VERSION 5.8 ;
BUSBITCHARS "[]" ;
DIVIDERCHAR "/" ;
UNITS
    DATABASE MICRONS 1000 ;
END UNITS

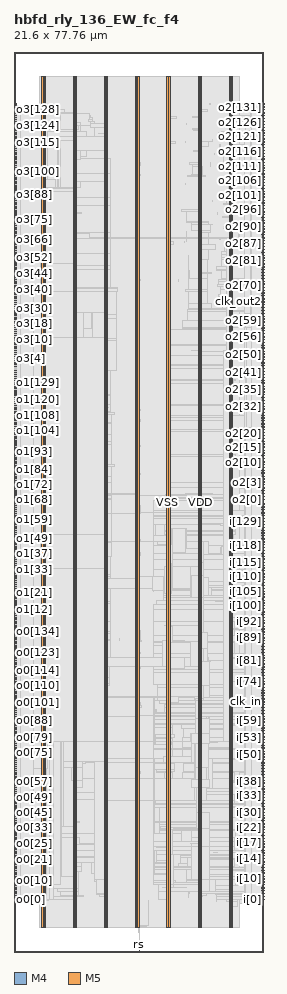
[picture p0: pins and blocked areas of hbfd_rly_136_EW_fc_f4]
MACRO hbfd_rly_136_EW_fc_f4
  FOREIGN hbfd_rly_136_EW_fc_f4 0 0 ;
  CLASS BLOCK ;
  SIZE 21.6 BY 77.76 ;
  PIN clk_in
    DIRECTION INPUT ;
    USE SIGNAL ;
    PORT
      LAYER M4 ;
        RECT  21.408 21.6 21.6 21.624 ;
    END
  END clk_in
  PIN clk_out0
    DIRECTION OUTPUT ;
    USE SIGNAL ;
    PORT
      LAYER M4 ;
        RECT  0 15.84 0.192 15.864 ;
    END
  END clk_out0
  PIN clk_out1
    DIRECTION OUTPUT ;
    USE SIGNAL ;
    PORT
      LAYER M4 ;
        RECT  0 38.88 0.192 38.904 ;
    END
  END clk_out1
  PIN clk_out2
    DIRECTION OUTPUT ;
    USE SIGNAL ;
    PORT
      LAYER M4 ;
        RECT  21.408 56.16 21.6 56.184 ;
    END
  END clk_out2
  PIN clk_out3
    DIRECTION OUTPUT ;
    USE SIGNAL ;
    PORT
      LAYER M4 ;
        RECT  0 61.92 0.192 61.944 ;
    END
  END clk_out3
  PIN i[0]
    DIRECTION INPUT ;
    USE SIGNAL ;
    PORT
      LAYER M4 ;
        RECT  21.408 4.512 21.6 4.536 ;
    END
  END i[0]
  PIN i[100]
    DIRECTION INPUT ;
    USE SIGNAL ;
    PORT
      LAYER M4 ;
        RECT  21.408 29.904 21.6 29.928 ;
    END
  END i[100]
  PIN i[101]
    DIRECTION INPUT ;
    USE SIGNAL ;
    PORT
      LAYER M4 ;
        RECT  21.408 30.144 21.6 30.168 ;
    END
  END i[101]
  PIN i[102]
    DIRECTION INPUT ;
    USE SIGNAL ;
    PORT
      LAYER M4 ;
        RECT  21.408 30.384 21.6 30.408 ;
    END
  END i[102]
  PIN i[103]
    DIRECTION INPUT ;
    USE SIGNAL ;
    PORT
      LAYER M4 ;
        RECT  21.408 30.672 21.6 30.696 ;
    END
  END i[103]
  PIN i[104]
    DIRECTION INPUT ;
    USE SIGNAL ;
    PORT
      LAYER M4 ;
        RECT  21.408 30.912 21.6 30.936 ;
    END
  END i[104]
  PIN i[105]
    DIRECTION INPUT ;
    USE SIGNAL ;
    PORT
      LAYER M4 ;
        RECT  21.408 31.152 21.6 31.176 ;
    END
  END i[105]
  PIN i[106]
    DIRECTION INPUT ;
    USE SIGNAL ;
    PORT
      LAYER M4 ;
        RECT  21.408 31.392 21.6 31.416 ;
    END
  END i[106]
  PIN i[107]
    DIRECTION INPUT ;
    USE SIGNAL ;
    PORT
      LAYER M4 ;
        RECT  21.408 31.68 21.6 31.704 ;
    END
  END i[107]
  PIN i[108]
    DIRECTION INPUT ;
    USE SIGNAL ;
    PORT
      LAYER M4 ;
        RECT  21.408 31.92 21.6 31.944 ;
    END
  END i[108]
  PIN i[109]
    DIRECTION INPUT ;
    USE SIGNAL ;
    PORT
      LAYER M4 ;
        RECT  21.408 32.16 21.6 32.184 ;
    END
  END i[109]
  PIN i[10]
    DIRECTION INPUT ;
    USE SIGNAL ;
    PORT
      LAYER M4 ;
        RECT  21.408 7.056 21.6 7.08 ;
    END
  END i[10]
  PIN i[110]
    DIRECTION INPUT ;
    USE SIGNAL ;
    PORT
      LAYER M4 ;
        RECT  21.408 32.4 21.6 32.424 ;
    END
  END i[110]
  PIN i[111]
    DIRECTION INPUT ;
    USE SIGNAL ;
    PORT
      LAYER M4 ;
        RECT  21.408 32.64 21.6 32.664 ;
    END
  END i[111]
  PIN i[112]
    DIRECTION INPUT ;
    USE SIGNAL ;
    PORT
      LAYER M4 ;
        RECT  21.408 32.928 21.6 32.952 ;
    END
  END i[112]
  PIN i[113]
    DIRECTION INPUT ;
    USE SIGNAL ;
    PORT
      LAYER M4 ;
        RECT  21.408 33.168 21.6 33.192 ;
    END
  END i[113]
  PIN i[114]
    DIRECTION INPUT ;
    USE SIGNAL ;
    PORT
      LAYER M4 ;
        RECT  21.408 33.408 21.6 33.432 ;
    END
  END i[114]
  PIN i[115]
    DIRECTION INPUT ;
    USE SIGNAL ;
    PORT
      LAYER M4 ;
        RECT  21.408 33.648 21.6 33.672 ;
    END
  END i[115]
  PIN i[116]
    DIRECTION INPUT ;
    USE SIGNAL ;
    PORT
      LAYER M4 ;
        RECT  21.408 33.936 21.6 33.96 ;
    END
  END i[116]
  PIN i[117]
    DIRECTION INPUT ;
    USE SIGNAL ;
    PORT
      LAYER M4 ;
        RECT  21.408 34.176 21.6 34.2 ;
    END
  END i[117]
  PIN i[118]
    DIRECTION INPUT ;
    USE SIGNAL ;
    PORT
      LAYER M4 ;
        RECT  21.408 34.416 21.6 34.44 ;
    END
  END i[118]
  PIN i[119]
    DIRECTION INPUT ;
    USE SIGNAL ;
    PORT
      LAYER M4 ;
        RECT  21.408 34.656 21.6 34.68 ;
    END
  END i[119]
  PIN i[11]
    DIRECTION INPUT ;
    USE SIGNAL ;
    PORT
      LAYER M4 ;
        RECT  21.408 7.296 21.6 7.32 ;
    END
  END i[11]
  PIN i[120]
    DIRECTION INPUT ;
    USE SIGNAL ;
    PORT
      LAYER M4 ;
        RECT  21.408 34.944 21.6 34.968 ;
    END
  END i[120]
  PIN i[121]
    DIRECTION INPUT ;
    USE SIGNAL ;
    PORT
      LAYER M4 ;
        RECT  21.408 35.184 21.6 35.208 ;
    END
  END i[121]
  PIN i[122]
    DIRECTION INPUT ;
    USE SIGNAL ;
    PORT
      LAYER M4 ;
        RECT  21.408 35.424 21.6 35.448 ;
    END
  END i[122]
  PIN i[123]
    DIRECTION INPUT ;
    USE SIGNAL ;
    PORT
      LAYER M4 ;
        RECT  21.408 35.664 21.6 35.688 ;
    END
  END i[123]
  PIN i[124]
    DIRECTION INPUT ;
    USE SIGNAL ;
    PORT
      LAYER M4 ;
        RECT  21.408 35.952 21.6 35.976 ;
    END
  END i[124]
  PIN i[125]
    DIRECTION INPUT ;
    USE SIGNAL ;
    PORT
      LAYER M4 ;
        RECT  21.408 36.192 21.6 36.216 ;
    END
  END i[125]
  PIN i[126]
    DIRECTION INPUT ;
    USE SIGNAL ;
    PORT
      LAYER M4 ;
        RECT  21.408 36.432 21.6 36.456 ;
    END
  END i[126]
  PIN i[127]
    DIRECTION INPUT ;
    USE SIGNAL ;
    PORT
      LAYER M4 ;
        RECT  21.408 36.672 21.6 36.696 ;
    END
  END i[127]
  PIN i[128]
    DIRECTION INPUT ;
    USE SIGNAL ;
    PORT
      LAYER M4 ;
        RECT  21.408 36.912 21.6 36.936 ;
    END
  END i[128]
  PIN i[129]
    DIRECTION INPUT ;
    USE SIGNAL ;
    PORT
      LAYER M4 ;
        RECT  21.408 37.2 21.6 37.224 ;
    END
  END i[129]
  PIN i[12]
    DIRECTION INPUT ;
    USE SIGNAL ;
    PORT
      LAYER M4 ;
        RECT  21.408 7.536 21.6 7.56 ;
    END
  END i[12]
  PIN i[130]
    DIRECTION INPUT ;
    USE SIGNAL ;
    PORT
      LAYER M4 ;
        RECT  21.408 37.44 21.6 37.464 ;
    END
  END i[130]
  PIN i[131]
    DIRECTION INPUT ;
    USE SIGNAL ;
    PORT
      LAYER M4 ;
        RECT  21.408 37.68 21.6 37.704 ;
    END
  END i[131]
  PIN i[132]
    DIRECTION INPUT ;
    USE SIGNAL ;
    PORT
      LAYER M4 ;
        RECT  21.408 37.92 21.6 37.944 ;
    END
  END i[132]
  PIN i[133]
    DIRECTION INPUT ;
    USE SIGNAL ;
    PORT
      LAYER M4 ;
        RECT  21.408 38.208 21.6 38.232 ;
    END
  END i[133]
  PIN i[134]
    DIRECTION INPUT ;
    USE SIGNAL ;
    PORT
      LAYER M4 ;
        RECT  21.408 38.448 21.6 38.472 ;
    END
  END i[134]
  PIN i[135]
    DIRECTION INPUT ;
    USE SIGNAL ;
    PORT
      LAYER M4 ;
        RECT  21.408 38.688 21.6 38.712 ;
    END
  END i[135]
  PIN i[13]
    DIRECTION INPUT ;
    USE SIGNAL ;
    PORT
      LAYER M4 ;
        RECT  21.408 7.776 21.6 7.8 ;
    END
  END i[13]
  PIN i[14]
    DIRECTION INPUT ;
    USE SIGNAL ;
    PORT
      LAYER M4 ;
        RECT  21.408 8.064 21.6 8.088 ;
    END
  END i[14]
  PIN i[15]
    DIRECTION INPUT ;
    USE SIGNAL ;
    PORT
      LAYER M4 ;
        RECT  21.408 8.304 21.6 8.328 ;
    END
  END i[15]
  PIN i[16]
    DIRECTION INPUT ;
    USE SIGNAL ;
    PORT
      LAYER M4 ;
        RECT  21.408 8.544 21.6 8.568 ;
    END
  END i[16]
  PIN i[17]
    DIRECTION INPUT ;
    USE SIGNAL ;
    PORT
      LAYER M4 ;
        RECT  21.408 8.784 21.6 8.808 ;
    END
  END i[17]
  PIN i[18]
    DIRECTION INPUT ;
    USE SIGNAL ;
    PORT
      LAYER M4 ;
        RECT  21.408 9.072 21.6 9.096 ;
    END
  END i[18]
  PIN i[19]
    DIRECTION INPUT ;
    USE SIGNAL ;
    PORT
      LAYER M4 ;
        RECT  21.408 9.312 21.6 9.336 ;
    END
  END i[19]
  PIN i[1]
    DIRECTION INPUT ;
    USE SIGNAL ;
    PORT
      LAYER M4 ;
        RECT  21.408 4.8 21.6 4.824 ;
    END
  END i[1]
  PIN i[20]
    DIRECTION INPUT ;
    USE SIGNAL ;
    PORT
      LAYER M4 ;
        RECT  21.408 9.552 21.6 9.576 ;
    END
  END i[20]
  PIN i[21]
    DIRECTION INPUT ;
    USE SIGNAL ;
    PORT
      LAYER M4 ;
        RECT  21.408 9.792 21.6 9.816 ;
    END
  END i[21]
  PIN i[22]
    DIRECTION INPUT ;
    USE SIGNAL ;
    PORT
      LAYER M4 ;
        RECT  21.408 10.08 21.6 10.104 ;
    END
  END i[22]
  PIN i[23]
    DIRECTION INPUT ;
    USE SIGNAL ;
    PORT
      LAYER M4 ;
        RECT  21.408 10.32 21.6 10.344 ;
    END
  END i[23]
  PIN i[24]
    DIRECTION INPUT ;
    USE SIGNAL ;
    PORT
      LAYER M4 ;
        RECT  21.408 10.56 21.6 10.584 ;
    END
  END i[24]
  PIN i[25]
    DIRECTION INPUT ;
    USE SIGNAL ;
    PORT
      LAYER M4 ;
        RECT  21.408 10.8 21.6 10.824 ;
    END
  END i[25]
  PIN i[26]
    DIRECTION INPUT ;
    USE SIGNAL ;
    PORT
      LAYER M4 ;
        RECT  21.408 11.04 21.6 11.064 ;
    END
  END i[26]
  PIN i[27]
    DIRECTION INPUT ;
    USE SIGNAL ;
    PORT
      LAYER M4 ;
        RECT  21.408 11.328 21.6 11.352 ;
    END
  END i[27]
  PIN i[28]
    DIRECTION INPUT ;
    USE SIGNAL ;
    PORT
      LAYER M4 ;
        RECT  21.408 11.568 21.6 11.592 ;
    END
  END i[28]
  PIN i[29]
    DIRECTION INPUT ;
    USE SIGNAL ;
    PORT
      LAYER M4 ;
        RECT  21.408 11.808 21.6 11.832 ;
    END
  END i[29]
  PIN i[2]
    DIRECTION INPUT ;
    USE SIGNAL ;
    PORT
      LAYER M4 ;
        RECT  21.408 5.04 21.6 5.064 ;
    END
  END i[2]
  PIN i[30]
    DIRECTION INPUT ;
    USE SIGNAL ;
    PORT
      LAYER M4 ;
        RECT  21.408 12.048 21.6 12.072 ;
    END
  END i[30]
  PIN i[31]
    DIRECTION INPUT ;
    USE SIGNAL ;
    PORT
      LAYER M4 ;
        RECT  21.408 12.336 21.6 12.36 ;
    END
  END i[31]
  PIN i[32]
    DIRECTION INPUT ;
    USE SIGNAL ;
    PORT
      LAYER M4 ;
        RECT  21.408 12.576 21.6 12.6 ;
    END
  END i[32]
  PIN i[33]
    DIRECTION INPUT ;
    USE SIGNAL ;
    PORT
      LAYER M4 ;
        RECT  21.408 12.816 21.6 12.84 ;
    END
  END i[33]
  PIN i[34]
    DIRECTION INPUT ;
    USE SIGNAL ;
    PORT
      LAYER M4 ;
        RECT  21.408 13.056 21.6 13.08 ;
    END
  END i[34]
  PIN i[35]
    DIRECTION INPUT ;
    USE SIGNAL ;
    PORT
      LAYER M4 ;
        RECT  21.408 13.344 21.6 13.368 ;
    END
  END i[35]
  PIN i[36]
    DIRECTION INPUT ;
    USE SIGNAL ;
    PORT
      LAYER M4 ;
        RECT  21.408 13.584 21.6 13.608 ;
    END
  END i[36]
  PIN i[37]
    DIRECTION INPUT ;
    USE SIGNAL ;
    PORT
      LAYER M4 ;
        RECT  21.408 13.824 21.6 13.848 ;
    END
  END i[37]
  PIN i[38]
    DIRECTION INPUT ;
    USE SIGNAL ;
    PORT
      LAYER M4 ;
        RECT  21.408 14.064 21.6 14.088 ;
    END
  END i[38]
  PIN i[39]
    DIRECTION INPUT ;
    USE SIGNAL ;
    PORT
      LAYER M4 ;
        RECT  21.408 14.304 21.6 14.328 ;
    END
  END i[39]
  PIN i[3]
    DIRECTION INPUT ;
    USE SIGNAL ;
    PORT
      LAYER M4 ;
        RECT  21.408 5.28 21.6 5.304 ;
    END
  END i[3]
  PIN i[40]
    DIRECTION INPUT ;
    USE SIGNAL ;
    PORT
      LAYER M4 ;
        RECT  21.408 14.592 21.6 14.616 ;
    END
  END i[40]
  PIN i[41]
    DIRECTION INPUT ;
    USE SIGNAL ;
    PORT
      LAYER M4 ;
        RECT  21.408 14.832 21.6 14.856 ;
    END
  END i[41]
  PIN i[42]
    DIRECTION INPUT ;
    USE SIGNAL ;
    PORT
      LAYER M4 ;
        RECT  21.408 15.072 21.6 15.096 ;
    END
  END i[42]
  PIN i[43]
    DIRECTION INPUT ;
    USE SIGNAL ;
    PORT
      LAYER M4 ;
        RECT  21.408 15.312 21.6 15.336 ;
    END
  END i[43]
  PIN i[44]
    DIRECTION INPUT ;
    USE SIGNAL ;
    PORT
      LAYER M4 ;
        RECT  21.408 15.6 21.6 15.624 ;
    END
  END i[44]
  PIN i[45]
    DIRECTION INPUT ;
    USE SIGNAL ;
    PORT
      LAYER M4 ;
        RECT  21.408 15.84 21.6 15.864 ;
    END
  END i[45]
  PIN i[46]
    DIRECTION INPUT ;
    USE SIGNAL ;
    PORT
      LAYER M4 ;
        RECT  21.408 16.08 21.6 16.104 ;
    END
  END i[46]
  PIN i[47]
    DIRECTION INPUT ;
    USE SIGNAL ;
    PORT
      LAYER M4 ;
        RECT  21.408 16.32 21.6 16.344 ;
    END
  END i[47]
  PIN i[48]
    DIRECTION INPUT ;
    USE SIGNAL ;
    PORT
      LAYER M4 ;
        RECT  21.408 16.608 21.6 16.632 ;
    END
  END i[48]
  PIN i[49]
    DIRECTION INPUT ;
    USE SIGNAL ;
    PORT
      LAYER M4 ;
        RECT  21.408 16.848 21.6 16.872 ;
    END
  END i[49]
  PIN i[4]
    DIRECTION INPUT ;
    USE SIGNAL ;
    PORT
      LAYER M4 ;
        RECT  21.408 5.52 21.6 5.544 ;
    END
  END i[4]
  PIN i[50]
    DIRECTION INPUT ;
    USE SIGNAL ;
    PORT
      LAYER M4 ;
        RECT  21.408 17.088 21.6 17.112 ;
    END
  END i[50]
  PIN i[51]
    DIRECTION INPUT ;
    USE SIGNAL ;
    PORT
      LAYER M4 ;
        RECT  21.408 17.328 21.6 17.352 ;
    END
  END i[51]
  PIN i[52]
    DIRECTION INPUT ;
    USE SIGNAL ;
    PORT
      LAYER M4 ;
        RECT  21.408 17.616 21.6 17.64 ;
    END
  END i[52]
  PIN i[53]
    DIRECTION INPUT ;
    USE SIGNAL ;
    PORT
      LAYER M4 ;
        RECT  21.408 17.856 21.6 17.88 ;
    END
  END i[53]
  PIN i[54]
    DIRECTION INPUT ;
    USE SIGNAL ;
    PORT
      LAYER M4 ;
        RECT  21.408 18.096 21.6 18.12 ;
    END
  END i[54]
  PIN i[55]
    DIRECTION INPUT ;
    USE SIGNAL ;
    PORT
      LAYER M4 ;
        RECT  21.408 18.336 21.6 18.36 ;
    END
  END i[55]
  PIN i[56]
    DIRECTION INPUT ;
    USE SIGNAL ;
    PORT
      LAYER M4 ;
        RECT  21.408 18.576 21.6 18.6 ;
    END
  END i[56]
  PIN i[57]
    DIRECTION INPUT ;
    USE SIGNAL ;
    PORT
      LAYER M4 ;
        RECT  21.408 18.864 21.6 18.888 ;
    END
  END i[57]
  PIN i[58]
    DIRECTION INPUT ;
    USE SIGNAL ;
    PORT
      LAYER M4 ;
        RECT  21.408 19.104 21.6 19.128 ;
    END
  END i[58]
  PIN i[59]
    DIRECTION INPUT ;
    USE SIGNAL ;
    PORT
      LAYER M4 ;
        RECT  21.408 19.344 21.6 19.368 ;
    END
  END i[59]
  PIN i[5]
    DIRECTION INPUT ;
    USE SIGNAL ;
    PORT
      LAYER M4 ;
        RECT  21.408 5.808 21.6 5.832 ;
    END
  END i[5]
  PIN i[60]
    DIRECTION INPUT ;
    USE SIGNAL ;
    PORT
      LAYER M4 ;
        RECT  21.408 19.584 21.6 19.608 ;
    END
  END i[60]
  PIN i[61]
    DIRECTION INPUT ;
    USE SIGNAL ;
    PORT
      LAYER M4 ;
        RECT  21.408 19.872 21.6 19.896 ;
    END
  END i[61]
  PIN i[62]
    DIRECTION INPUT ;
    USE SIGNAL ;
    PORT
      LAYER M4 ;
        RECT  21.408 20.112 21.6 20.136 ;
    END
  END i[62]
  PIN i[63]
    DIRECTION INPUT ;
    USE SIGNAL ;
    PORT
      LAYER M4 ;
        RECT  21.408 20.352 21.6 20.376 ;
    END
  END i[63]
  PIN i[64]
    DIRECTION INPUT ;
    USE SIGNAL ;
    PORT
      LAYER M4 ;
        RECT  21.408 20.592 21.6 20.616 ;
    END
  END i[64]
  PIN i[65]
    DIRECTION INPUT ;
    USE SIGNAL ;
    PORT
      LAYER M4 ;
        RECT  21.408 20.88 21.6 20.904 ;
    END
  END i[65]
  PIN i[66]
    DIRECTION INPUT ;
    USE SIGNAL ;
    PORT
      LAYER M4 ;
        RECT  21.408 21.12 21.6 21.144 ;
    END
  END i[66]
  PIN i[67]
    DIRECTION INPUT ;
    USE SIGNAL ;
    PORT
      LAYER M4 ;
        RECT  21.408 21.36 21.6 21.384 ;
    END
  END i[67]
  PIN i[68]
    DIRECTION INPUT ;
    USE SIGNAL ;
    PORT
      LAYER M4 ;
        RECT  21.408 21.84 21.6 21.864 ;
    END
  END i[68]
  PIN i[69]
    DIRECTION INPUT ;
    USE SIGNAL ;
    PORT
      LAYER M4 ;
        RECT  21.408 22.128 21.6 22.152 ;
    END
  END i[69]
  PIN i[6]
    DIRECTION INPUT ;
    USE SIGNAL ;
    PORT
      LAYER M4 ;
        RECT  21.408 6.048 21.6 6.072 ;
    END
  END i[6]
  PIN i[70]
    DIRECTION INPUT ;
    USE SIGNAL ;
    PORT
      LAYER M4 ;
        RECT  21.408 22.368 21.6 22.392 ;
    END
  END i[70]
  PIN i[71]
    DIRECTION INPUT ;
    USE SIGNAL ;
    PORT
      LAYER M4 ;
        RECT  21.408 22.608 21.6 22.632 ;
    END
  END i[71]
  PIN i[72]
    DIRECTION INPUT ;
    USE SIGNAL ;
    PORT
      LAYER M4 ;
        RECT  21.408 22.848 21.6 22.872 ;
    END
  END i[72]
  PIN i[73]
    DIRECTION INPUT ;
    USE SIGNAL ;
    PORT
      LAYER M4 ;
        RECT  21.408 23.136 21.6 23.16 ;
    END
  END i[73]
  PIN i[74]
    DIRECTION INPUT ;
    USE SIGNAL ;
    PORT
      LAYER M4 ;
        RECT  21.408 23.376 21.6 23.4 ;
    END
  END i[74]
  PIN i[75]
    DIRECTION INPUT ;
    USE SIGNAL ;
    PORT
      LAYER M4 ;
        RECT  21.408 23.616 21.6 23.64 ;
    END
  END i[75]
  PIN i[76]
    DIRECTION INPUT ;
    USE SIGNAL ;
    PORT
      LAYER M4 ;
        RECT  21.408 23.856 21.6 23.88 ;
    END
  END i[76]
  PIN i[77]
    DIRECTION INPUT ;
    USE SIGNAL ;
    PORT
      LAYER M4 ;
        RECT  21.408 24.144 21.6 24.168 ;
    END
  END i[77]
  PIN i[78]
    DIRECTION INPUT ;
    USE SIGNAL ;
    PORT
      LAYER M4 ;
        RECT  21.408 24.384 21.6 24.408 ;
    END
  END i[78]
  PIN i[79]
    DIRECTION INPUT ;
    USE SIGNAL ;
    PORT
      LAYER M4 ;
        RECT  21.408 24.624 21.6 24.648 ;
    END
  END i[79]
  PIN i[7]
    DIRECTION INPUT ;
    USE SIGNAL ;
    PORT
      LAYER M4 ;
        RECT  21.408 6.288 21.6 6.312 ;
    END
  END i[7]
  PIN i[80]
    DIRECTION INPUT ;
    USE SIGNAL ;
    PORT
      LAYER M4 ;
        RECT  21.408 24.864 21.6 24.888 ;
    END
  END i[80]
  PIN i[81]
    DIRECTION INPUT ;
    USE SIGNAL ;
    PORT
      LAYER M4 ;
        RECT  21.408 25.152 21.6 25.176 ;
    END
  END i[81]
  PIN i[82]
    DIRECTION INPUT ;
    USE SIGNAL ;
    PORT
      LAYER M4 ;
        RECT  21.408 25.392 21.6 25.416 ;
    END
  END i[82]
  PIN i[83]
    DIRECTION INPUT ;
    USE SIGNAL ;
    PORT
      LAYER M4 ;
        RECT  21.408 25.632 21.6 25.656 ;
    END
  END i[83]
  PIN i[84]
    DIRECTION INPUT ;
    USE SIGNAL ;
    PORT
      LAYER M4 ;
        RECT  21.408 25.872 21.6 25.896 ;
    END
  END i[84]
  PIN i[85]
    DIRECTION INPUT ;
    USE SIGNAL ;
    PORT
      LAYER M4 ;
        RECT  21.408 26.112 21.6 26.136 ;
    END
  END i[85]
  PIN i[86]
    DIRECTION INPUT ;
    USE SIGNAL ;
    PORT
      LAYER M4 ;
        RECT  21.408 26.4 21.6 26.424 ;
    END
  END i[86]
  PIN i[87]
    DIRECTION INPUT ;
    USE SIGNAL ;
    PORT
      LAYER M4 ;
        RECT  21.408 26.64 21.6 26.664 ;
    END
  END i[87]
  PIN i[88]
    DIRECTION INPUT ;
    USE SIGNAL ;
    PORT
      LAYER M4 ;
        RECT  21.408 26.88 21.6 26.904 ;
    END
  END i[88]
  PIN i[89]
    DIRECTION INPUT ;
    USE SIGNAL ;
    PORT
      LAYER M4 ;
        RECT  21.408 27.12 21.6 27.144 ;
    END
  END i[89]
  PIN i[8]
    DIRECTION INPUT ;
    USE SIGNAL ;
    PORT
      LAYER M4 ;
        RECT  21.408 6.528 21.6 6.552 ;
    END
  END i[8]
  PIN i[90]
    DIRECTION INPUT ;
    USE SIGNAL ;
    PORT
      LAYER M4 ;
        RECT  21.408 27.408 21.6 27.432 ;
    END
  END i[90]
  PIN i[91]
    DIRECTION INPUT ;
    USE SIGNAL ;
    PORT
      LAYER M4 ;
        RECT  21.408 27.648 21.6 27.672 ;
    END
  END i[91]
  PIN i[92]
    DIRECTION INPUT ;
    USE SIGNAL ;
    PORT
      LAYER M4 ;
        RECT  21.408 27.888 21.6 27.912 ;
    END
  END i[92]
  PIN i[93]
    DIRECTION INPUT ;
    USE SIGNAL ;
    PORT
      LAYER M4 ;
        RECT  21.408 28.128 21.6 28.152 ;
    END
  END i[93]
  PIN i[94]
    DIRECTION INPUT ;
    USE SIGNAL ;
    PORT
      LAYER M4 ;
        RECT  21.408 28.416 21.6 28.44 ;
    END
  END i[94]
  PIN i[95]
    DIRECTION INPUT ;
    USE SIGNAL ;
    PORT
      LAYER M4 ;
        RECT  21.408 28.656 21.6 28.68 ;
    END
  END i[95]
  PIN i[96]
    DIRECTION INPUT ;
    USE SIGNAL ;
    PORT
      LAYER M4 ;
        RECT  21.408 28.896 21.6 28.92 ;
    END
  END i[96]
  PIN i[97]
    DIRECTION INPUT ;
    USE SIGNAL ;
    PORT
      LAYER M4 ;
        RECT  21.408 29.136 21.6 29.16 ;
    END
  END i[97]
  PIN i[98]
    DIRECTION INPUT ;
    USE SIGNAL ;
    PORT
      LAYER M4 ;
        RECT  21.408 29.376 21.6 29.4 ;
    END
  END i[98]
  PIN i[99]
    DIRECTION INPUT ;
    USE SIGNAL ;
    PORT
      LAYER M4 ;
        RECT  21.408 29.664 21.6 29.688 ;
    END
  END i[99]
  PIN i[9]
    DIRECTION INPUT ;
    USE SIGNAL ;
    PORT
      LAYER M4 ;
        RECT  21.408 6.816 21.6 6.84 ;
    END
  END i[9]
  PIN o0[0]
    DIRECTION OUTPUT ;
    USE SIGNAL ;
    PORT
      LAYER M4 ;
        RECT  0 4.512 0.192 4.536 ;
    END
  END o0[0]
  PIN o0[100]
    DIRECTION OUTPUT ;
    USE SIGNAL ;
    PORT
      LAYER M4 ;
        RECT  0 21.36 0.192 21.384 ;
    END
  END o0[100]
  PIN o0[101]
    DIRECTION OUTPUT ;
    USE SIGNAL ;
    PORT
      LAYER M4 ;
        RECT  0 21.504 0.192 21.528 ;
    END
  END o0[101]
  PIN o0[102]
    DIRECTION OUTPUT ;
    USE SIGNAL ;
    PORT
      LAYER M4 ;
        RECT  0 21.696 0.192 21.72 ;
    END
  END o0[102]
  PIN o0[103]
    DIRECTION OUTPUT ;
    USE SIGNAL ;
    PORT
      LAYER M4 ;
        RECT  0 21.84 0.192 21.864 ;
    END
  END o0[103]
  PIN o0[104]
    DIRECTION OUTPUT ;
    USE SIGNAL ;
    PORT
      LAYER M4 ;
        RECT  0 22.032 0.192 22.056 ;
    END
  END o0[104]
  PIN o0[105]
    DIRECTION OUTPUT ;
    USE SIGNAL ;
    PORT
      LAYER M4 ;
        RECT  0 22.176 0.192 22.2 ;
    END
  END o0[105]
  PIN o0[106]
    DIRECTION OUTPUT ;
    USE SIGNAL ;
    PORT
      LAYER M4 ;
        RECT  0 22.368 0.192 22.392 ;
    END
  END o0[106]
  PIN o0[107]
    DIRECTION OUTPUT ;
    USE SIGNAL ;
    PORT
      LAYER M4 ;
        RECT  0 22.512 0.192 22.536 ;
    END
  END o0[107]
  PIN o0[108]
    DIRECTION OUTPUT ;
    USE SIGNAL ;
    PORT
      LAYER M4 ;
        RECT  0 22.656 0.192 22.68 ;
    END
  END o0[108]
  PIN o0[109]
    DIRECTION OUTPUT ;
    USE SIGNAL ;
    PORT
      LAYER M4 ;
        RECT  0 22.848 0.192 22.872 ;
    END
  END o0[109]
  PIN o0[10]
    DIRECTION OUTPUT ;
    USE SIGNAL ;
    PORT
      LAYER M4 ;
        RECT  0 6.192 0.192 6.216 ;
    END
  END o0[10]
  PIN o0[110]
    DIRECTION OUTPUT ;
    USE SIGNAL ;
    PORT
      LAYER M4 ;
        RECT  0 22.992 0.192 23.016 ;
    END
  END o0[110]
  PIN o0[111]
    DIRECTION OUTPUT ;
    USE SIGNAL ;
    PORT
      LAYER M4 ;
        RECT  0 23.184 0.192 23.208 ;
    END
  END o0[111]
  PIN o0[112]
    DIRECTION OUTPUT ;
    USE SIGNAL ;
    PORT
      LAYER M4 ;
        RECT  0 23.328 0.192 23.352 ;
    END
  END o0[112]
  PIN o0[113]
    DIRECTION OUTPUT ;
    USE SIGNAL ;
    PORT
      LAYER M4 ;
        RECT  0 23.52 0.192 23.544 ;
    END
  END o0[113]
  PIN o0[114]
    DIRECTION OUTPUT ;
    USE SIGNAL ;
    PORT
      LAYER M4 ;
        RECT  0 23.664 0.192 23.688 ;
    END
  END o0[114]
  PIN o0[115]
    DIRECTION OUTPUT ;
    USE SIGNAL ;
    PORT
      LAYER M4 ;
        RECT  0 23.856 0.192 23.88 ;
    END
  END o0[115]
  PIN o0[116]
    DIRECTION OUTPUT ;
    USE SIGNAL ;
    PORT
      LAYER M4 ;
        RECT  0 24 0.192 24.024 ;
    END
  END o0[116]
  PIN o0[117]
    DIRECTION OUTPUT ;
    USE SIGNAL ;
    PORT
      LAYER M4 ;
        RECT  0 24.192 0.192 24.216 ;
    END
  END o0[117]
  PIN o0[118]
    DIRECTION OUTPUT ;
    USE SIGNAL ;
    PORT
      LAYER M4 ;
        RECT  0 24.336 0.192 24.36 ;
    END
  END o0[118]
  PIN o0[119]
    DIRECTION OUTPUT ;
    USE SIGNAL ;
    PORT
      LAYER M4 ;
        RECT  0 24.528 0.192 24.552 ;
    END
  END o0[119]
  PIN o0[11]
    DIRECTION OUTPUT ;
    USE SIGNAL ;
    PORT
      LAYER M4 ;
        RECT  0 6.384 0.192 6.408 ;
    END
  END o0[11]
  PIN o0[120]
    DIRECTION OUTPUT ;
    USE SIGNAL ;
    PORT
      LAYER M4 ;
        RECT  0 24.672 0.192 24.696 ;
    END
  END o0[120]
  PIN o0[121]
    DIRECTION OUTPUT ;
    USE SIGNAL ;
    PORT
      LAYER M4 ;
        RECT  0 24.864 0.192 24.888 ;
    END
  END o0[121]
  PIN o0[122]
    DIRECTION OUTPUT ;
    USE SIGNAL ;
    PORT
      LAYER M4 ;
        RECT  0 25.008 0.192 25.032 ;
    END
  END o0[122]
  PIN o0[123]
    DIRECTION OUTPUT ;
    USE SIGNAL ;
    PORT
      LAYER M4 ;
        RECT  0 25.152 0.192 25.176 ;
    END
  END o0[123]
  PIN o0[124]
    DIRECTION OUTPUT ;
    USE SIGNAL ;
    PORT
      LAYER M4 ;
        RECT  0 25.344 0.192 25.368 ;
    END
  END o0[124]
  PIN o0[125]
    DIRECTION OUTPUT ;
    USE SIGNAL ;
    PORT
      LAYER M4 ;
        RECT  0 25.488 0.192 25.512 ;
    END
  END o0[125]
  PIN o0[126]
    DIRECTION OUTPUT ;
    USE SIGNAL ;
    PORT
      LAYER M4 ;
        RECT  0 25.68 0.192 25.704 ;
    END
  END o0[126]
  PIN o0[127]
    DIRECTION OUTPUT ;
    USE SIGNAL ;
    PORT
      LAYER M4 ;
        RECT  0 25.824 0.192 25.848 ;
    END
  END o0[127]
  PIN o0[128]
    DIRECTION OUTPUT ;
    USE SIGNAL ;
    PORT
      LAYER M4 ;
        RECT  0 26.016 0.192 26.04 ;
    END
  END o0[128]
  PIN o0[129]
    DIRECTION OUTPUT ;
    USE SIGNAL ;
    PORT
      LAYER M4 ;
        RECT  0 26.16 0.192 26.184 ;
    END
  END o0[129]
  PIN o0[12]
    DIRECTION OUTPUT ;
    USE SIGNAL ;
    PORT
      LAYER M4 ;
        RECT  0 6.528 0.192 6.552 ;
    END
  END o0[12]
  PIN o0[130]
    DIRECTION OUTPUT ;
    USE SIGNAL ;
    PORT
      LAYER M4 ;
        RECT  0 26.352 0.192 26.376 ;
    END
  END o0[130]
  PIN o0[131]
    DIRECTION OUTPUT ;
    USE SIGNAL ;
    PORT
      LAYER M4 ;
        RECT  0 26.496 0.192 26.52 ;
    END
  END o0[131]
  PIN o0[132]
    DIRECTION OUTPUT ;
    USE SIGNAL ;
    PORT
      LAYER M4 ;
        RECT  0 26.688 0.192 26.712 ;
    END
  END o0[132]
  PIN o0[133]
    DIRECTION OUTPUT ;
    USE SIGNAL ;
    PORT
      LAYER M4 ;
        RECT  0 26.832 0.192 26.856 ;
    END
  END o0[133]
  PIN o0[134]
    DIRECTION OUTPUT ;
    USE SIGNAL ;
    PORT
      LAYER M4 ;
        RECT  0 27.024 0.192 27.048 ;
    END
  END o0[134]
  PIN o0[135]
    DIRECTION OUTPUT ;
    USE SIGNAL ;
    PORT
      LAYER M4 ;
        RECT  0 27.168 0.192 27.192 ;
    END
  END o0[135]
  PIN o0[13]
    DIRECTION OUTPUT ;
    USE SIGNAL ;
    PORT
      LAYER M4 ;
        RECT  0 6.72 0.192 6.744 ;
    END
  END o0[13]
  PIN o0[14]
    DIRECTION OUTPUT ;
    USE SIGNAL ;
    PORT
      LAYER M4 ;
        RECT  0 6.864 0.192 6.888 ;
    END
  END o0[14]
  PIN o0[15]
    DIRECTION OUTPUT ;
    USE SIGNAL ;
    PORT
      LAYER M4 ;
        RECT  0 7.008 0.192 7.032 ;
    END
  END o0[15]
  PIN o0[16]
    DIRECTION OUTPUT ;
    USE SIGNAL ;
    PORT
      LAYER M4 ;
        RECT  0 7.2 0.192 7.224 ;
    END
  END o0[16]
  PIN o0[17]
    DIRECTION OUTPUT ;
    USE SIGNAL ;
    PORT
      LAYER M4 ;
        RECT  0 7.344 0.192 7.368 ;
    END
  END o0[17]
  PIN o0[18]
    DIRECTION OUTPUT ;
    USE SIGNAL ;
    PORT
      LAYER M4 ;
        RECT  0 7.536 0.192 7.56 ;
    END
  END o0[18]
  PIN o0[19]
    DIRECTION OUTPUT ;
    USE SIGNAL ;
    PORT
      LAYER M4 ;
        RECT  0 7.68 0.192 7.704 ;
    END
  END o0[19]
  PIN o0[1]
    DIRECTION OUTPUT ;
    USE SIGNAL ;
    PORT
      LAYER M4 ;
        RECT  0 4.704 0.192 4.728 ;
    END
  END o0[1]
  PIN o0[20]
    DIRECTION OUTPUT ;
    USE SIGNAL ;
    PORT
      LAYER M4 ;
        RECT  0 7.872 0.192 7.896 ;
    END
  END o0[20]
  PIN o0[21]
    DIRECTION OUTPUT ;
    USE SIGNAL ;
    PORT
      LAYER M4 ;
        RECT  0 8.016 0.192 8.04 ;
    END
  END o0[21]
  PIN o0[22]
    DIRECTION OUTPUT ;
    USE SIGNAL ;
    PORT
      LAYER M4 ;
        RECT  0 8.208 0.192 8.232 ;
    END
  END o0[22]
  PIN o0[23]
    DIRECTION OUTPUT ;
    USE SIGNAL ;
    PORT
      LAYER M4 ;
        RECT  0 8.352 0.192 8.376 ;
    END
  END o0[23]
  PIN o0[24]
    DIRECTION OUTPUT ;
    USE SIGNAL ;
    PORT
      LAYER M4 ;
        RECT  0 8.544 0.192 8.568 ;
    END
  END o0[24]
  PIN o0[25]
    DIRECTION OUTPUT ;
    USE SIGNAL ;
    PORT
      LAYER M4 ;
        RECT  0 8.688 0.192 8.712 ;
    END
  END o0[25]
  PIN o0[26]
    DIRECTION OUTPUT ;
    USE SIGNAL ;
    PORT
      LAYER M4 ;
        RECT  0 8.88 0.192 8.904 ;
    END
  END o0[26]
  PIN o0[27]
    DIRECTION OUTPUT ;
    USE SIGNAL ;
    PORT
      LAYER M4 ;
        RECT  0 9.024 0.192 9.048 ;
    END
  END o0[27]
  PIN o0[28]
    DIRECTION OUTPUT ;
    USE SIGNAL ;
    PORT
      LAYER M4 ;
        RECT  0 9.216 0.192 9.24 ;
    END
  END o0[28]
  PIN o0[29]
    DIRECTION OUTPUT ;
    USE SIGNAL ;
    PORT
      LAYER M4 ;
        RECT  0 9.36 0.192 9.384 ;
    END
  END o0[29]
  PIN o0[2]
    DIRECTION OUTPUT ;
    USE SIGNAL ;
    PORT
      LAYER M4 ;
        RECT  0 4.848 0.192 4.872 ;
    END
  END o0[2]
  PIN o0[30]
    DIRECTION OUTPUT ;
    USE SIGNAL ;
    PORT
      LAYER M4 ;
        RECT  0 9.504 0.192 9.528 ;
    END
  END o0[30]
  PIN o0[31]
    DIRECTION OUTPUT ;
    USE SIGNAL ;
    PORT
      LAYER M4 ;
        RECT  0 9.696 0.192 9.72 ;
    END
  END o0[31]
  PIN o0[32]
    DIRECTION OUTPUT ;
    USE SIGNAL ;
    PORT
      LAYER M4 ;
        RECT  0 9.84 0.192 9.864 ;
    END
  END o0[32]
  PIN o0[33]
    DIRECTION OUTPUT ;
    USE SIGNAL ;
    PORT
      LAYER M4 ;
        RECT  0 10.032 0.192 10.056 ;
    END
  END o0[33]
  PIN o0[34]
    DIRECTION OUTPUT ;
    USE SIGNAL ;
    PORT
      LAYER M4 ;
        RECT  0 10.176 0.192 10.2 ;
    END
  END o0[34]
  PIN o0[35]
    DIRECTION OUTPUT ;
    USE SIGNAL ;
    PORT
      LAYER M4 ;
        RECT  0 10.368 0.192 10.392 ;
    END
  END o0[35]
  PIN o0[36]
    DIRECTION OUTPUT ;
    USE SIGNAL ;
    PORT
      LAYER M4 ;
        RECT  0 10.512 0.192 10.536 ;
    END
  END o0[36]
  PIN o0[37]
    DIRECTION OUTPUT ;
    USE SIGNAL ;
    PORT
      LAYER M4 ;
        RECT  0 10.704 0.192 10.728 ;
    END
  END o0[37]
  PIN o0[38]
    DIRECTION OUTPUT ;
    USE SIGNAL ;
    PORT
      LAYER M4 ;
        RECT  0 10.848 0.192 10.872 ;
    END
  END o0[38]
  PIN o0[39]
    DIRECTION OUTPUT ;
    USE SIGNAL ;
    PORT
      LAYER M4 ;
        RECT  0 11.04 0.192 11.064 ;
    END
  END o0[39]
  PIN o0[3]
    DIRECTION OUTPUT ;
    USE SIGNAL ;
    PORT
      LAYER M4 ;
        RECT  0 5.04 0.192 5.064 ;
    END
  END o0[3]
  PIN o0[40]
    DIRECTION OUTPUT ;
    USE SIGNAL ;
    PORT
      LAYER M4 ;
        RECT  0 11.184 0.192 11.208 ;
    END
  END o0[40]
  PIN o0[41]
    DIRECTION OUTPUT ;
    USE SIGNAL ;
    PORT
      LAYER M4 ;
        RECT  0 11.376 0.192 11.4 ;
    END
  END o0[41]
  PIN o0[42]
    DIRECTION OUTPUT ;
    USE SIGNAL ;
    PORT
      LAYER M4 ;
        RECT  0 11.52 0.192 11.544 ;
    END
  END o0[42]
  PIN o0[43]
    DIRECTION OUTPUT ;
    USE SIGNAL ;
    PORT
      LAYER M4 ;
        RECT  0 11.712 0.192 11.736 ;
    END
  END o0[43]
  PIN o0[44]
    DIRECTION OUTPUT ;
    USE SIGNAL ;
    PORT
      LAYER M4 ;
        RECT  0 11.856 0.192 11.88 ;
    END
  END o0[44]
  PIN o0[45]
    DIRECTION OUTPUT ;
    USE SIGNAL ;
    PORT
      LAYER M4 ;
        RECT  0 12 0.192 12.024 ;
    END
  END o0[45]
  PIN o0[46]
    DIRECTION OUTPUT ;
    USE SIGNAL ;
    PORT
      LAYER M4 ;
        RECT  0 12.192 0.192 12.216 ;
    END
  END o0[46]
  PIN o0[47]
    DIRECTION OUTPUT ;
    USE SIGNAL ;
    PORT
      LAYER M4 ;
        RECT  0 12.336 0.192 12.36 ;
    END
  END o0[47]
  PIN o0[48]
    DIRECTION OUTPUT ;
    USE SIGNAL ;
    PORT
      LAYER M4 ;
        RECT  0 12.528 0.192 12.552 ;
    END
  END o0[48]
  PIN o0[49]
    DIRECTION OUTPUT ;
    USE SIGNAL ;
    PORT
      LAYER M4 ;
        RECT  0 12.672 0.192 12.696 ;
    END
  END o0[49]
  PIN o0[4]
    DIRECTION OUTPUT ;
    USE SIGNAL ;
    PORT
      LAYER M4 ;
        RECT  0 5.184 0.192 5.208 ;
    END
  END o0[4]
  PIN o0[50]
    DIRECTION OUTPUT ;
    USE SIGNAL ;
    PORT
      LAYER M4 ;
        RECT  0 12.864 0.192 12.888 ;
    END
  END o0[50]
  PIN o0[51]
    DIRECTION OUTPUT ;
    USE SIGNAL ;
    PORT
      LAYER M4 ;
        RECT  0 13.008 0.192 13.032 ;
    END
  END o0[51]
  PIN o0[52]
    DIRECTION OUTPUT ;
    USE SIGNAL ;
    PORT
      LAYER M4 ;
        RECT  0 13.2 0.192 13.224 ;
    END
  END o0[52]
  PIN o0[53]
    DIRECTION OUTPUT ;
    USE SIGNAL ;
    PORT
      LAYER M4 ;
        RECT  0 13.344 0.192 13.368 ;
    END
  END o0[53]
  PIN o0[54]
    DIRECTION OUTPUT ;
    USE SIGNAL ;
    PORT
      LAYER M4 ;
        RECT  0 13.536 0.192 13.56 ;
    END
  END o0[54]
  PIN o0[55]
    DIRECTION OUTPUT ;
    USE SIGNAL ;
    PORT
      LAYER M4 ;
        RECT  0 13.68 0.192 13.704 ;
    END
  END o0[55]
  PIN o0[56]
    DIRECTION OUTPUT ;
    USE SIGNAL ;
    PORT
      LAYER M4 ;
        RECT  0 13.872 0.192 13.896 ;
    END
  END o0[56]
  PIN o0[57]
    DIRECTION OUTPUT ;
    USE SIGNAL ;
    PORT
      LAYER M4 ;
        RECT  0 14.016 0.192 14.04 ;
    END
  END o0[57]
  PIN o0[58]
    DIRECTION OUTPUT ;
    USE SIGNAL ;
    PORT
      LAYER M4 ;
        RECT  0 14.208 0.192 14.232 ;
    END
  END o0[58]
  PIN o0[59]
    DIRECTION OUTPUT ;
    USE SIGNAL ;
    PORT
      LAYER M4 ;
        RECT  0 14.352 0.192 14.376 ;
    END
  END o0[59]
  PIN o0[5]
    DIRECTION OUTPUT ;
    USE SIGNAL ;
    PORT
      LAYER M4 ;
        RECT  0 5.376 0.192 5.4 ;
    END
  END o0[5]
  PIN o0[60]
    DIRECTION OUTPUT ;
    USE SIGNAL ;
    PORT
      LAYER M4 ;
        RECT  0 14.544 0.192 14.568 ;
    END
  END o0[60]
  PIN o0[61]
    DIRECTION OUTPUT ;
    USE SIGNAL ;
    PORT
      LAYER M4 ;
        RECT  0 14.688 0.192 14.712 ;
    END
  END o0[61]
  PIN o0[62]
    DIRECTION OUTPUT ;
    USE SIGNAL ;
    PORT
      LAYER M4 ;
        RECT  0 14.832 0.192 14.856 ;
    END
  END o0[62]
  PIN o0[63]
    DIRECTION OUTPUT ;
    USE SIGNAL ;
    PORT
      LAYER M4 ;
        RECT  0 15.024 0.192 15.048 ;
    END
  END o0[63]
  PIN o0[64]
    DIRECTION OUTPUT ;
    USE SIGNAL ;
    PORT
      LAYER M4 ;
        RECT  0 15.168 0.192 15.192 ;
    END
  END o0[64]
  PIN o0[65]
    DIRECTION OUTPUT ;
    USE SIGNAL ;
    PORT
      LAYER M4 ;
        RECT  0 15.36 0.192 15.384 ;
    END
  END o0[65]
  PIN o0[66]
    DIRECTION OUTPUT ;
    USE SIGNAL ;
    PORT
      LAYER M4 ;
        RECT  0 15.504 0.192 15.528 ;
    END
  END o0[66]
  PIN o0[67]
    DIRECTION OUTPUT ;
    USE SIGNAL ;
    PORT
      LAYER M4 ;
        RECT  0 15.696 0.192 15.72 ;
    END
  END o0[67]
  PIN o0[68]
    DIRECTION OUTPUT ;
    USE SIGNAL ;
    PORT
      LAYER M4 ;
        RECT  0 16.032 0.192 16.056 ;
    END
  END o0[68]
  PIN o0[69]
    DIRECTION OUTPUT ;
    USE SIGNAL ;
    PORT
      LAYER M4 ;
        RECT  0 16.176 0.192 16.2 ;
    END
  END o0[69]
  PIN o0[6]
    DIRECTION OUTPUT ;
    USE SIGNAL ;
    PORT
      LAYER M4 ;
        RECT  0 5.52 0.192 5.544 ;
    END
  END o0[6]
  PIN o0[70]
    DIRECTION OUTPUT ;
    USE SIGNAL ;
    PORT
      LAYER M4 ;
        RECT  0 16.368 0.192 16.392 ;
    END
  END o0[70]
  PIN o0[71]
    DIRECTION OUTPUT ;
    USE SIGNAL ;
    PORT
      LAYER M4 ;
        RECT  0 16.512 0.192 16.536 ;
    END
  END o0[71]
  PIN o0[72]
    DIRECTION OUTPUT ;
    USE SIGNAL ;
    PORT
      LAYER M4 ;
        RECT  0 16.704 0.192 16.728 ;
    END
  END o0[72]
  PIN o0[73]
    DIRECTION OUTPUT ;
    USE SIGNAL ;
    PORT
      LAYER M4 ;
        RECT  0 16.848 0.192 16.872 ;
    END
  END o0[73]
  PIN o0[74]
    DIRECTION OUTPUT ;
    USE SIGNAL ;
    PORT
      LAYER M4 ;
        RECT  0 17.04 0.192 17.064 ;
    END
  END o0[74]
  PIN o0[75]
    DIRECTION OUTPUT ;
    USE SIGNAL ;
    PORT
      LAYER M4 ;
        RECT  0 17.184 0.192 17.208 ;
    END
  END o0[75]
  PIN o0[76]
    DIRECTION OUTPUT ;
    USE SIGNAL ;
    PORT
      LAYER M4 ;
        RECT  0 17.328 0.192 17.352 ;
    END
  END o0[76]
  PIN o0[77]
    DIRECTION OUTPUT ;
    USE SIGNAL ;
    PORT
      LAYER M4 ;
        RECT  0 17.52 0.192 17.544 ;
    END
  END o0[77]
  PIN o0[78]
    DIRECTION OUTPUT ;
    USE SIGNAL ;
    PORT
      LAYER M4 ;
        RECT  0 17.664 0.192 17.688 ;
    END
  END o0[78]
  PIN o0[79]
    DIRECTION OUTPUT ;
    USE SIGNAL ;
    PORT
      LAYER M4 ;
        RECT  0 17.856 0.192 17.88 ;
    END
  END o0[79]
  PIN o0[7]
    DIRECTION OUTPUT ;
    USE SIGNAL ;
    PORT
      LAYER M4 ;
        RECT  0 5.712 0.192 5.736 ;
    END
  END o0[7]
  PIN o0[80]
    DIRECTION OUTPUT ;
    USE SIGNAL ;
    PORT
      LAYER M4 ;
        RECT  0 18 0.192 18.024 ;
    END
  END o0[80]
  PIN o0[81]
    DIRECTION OUTPUT ;
    USE SIGNAL ;
    PORT
      LAYER M4 ;
        RECT  0 18.192 0.192 18.216 ;
    END
  END o0[81]
  PIN o0[82]
    DIRECTION OUTPUT ;
    USE SIGNAL ;
    PORT
      LAYER M4 ;
        RECT  0 18.336 0.192 18.36 ;
    END
  END o0[82]
  PIN o0[83]
    DIRECTION OUTPUT ;
    USE SIGNAL ;
    PORT
      LAYER M4 ;
        RECT  0 18.528 0.192 18.552 ;
    END
  END o0[83]
  PIN o0[84]
    DIRECTION OUTPUT ;
    USE SIGNAL ;
    PORT
      LAYER M4 ;
        RECT  0 18.672 0.192 18.696 ;
    END
  END o0[84]
  PIN o0[85]
    DIRECTION OUTPUT ;
    USE SIGNAL ;
    PORT
      LAYER M4 ;
        RECT  0 18.864 0.192 18.888 ;
    END
  END o0[85]
  PIN o0[86]
    DIRECTION OUTPUT ;
    USE SIGNAL ;
    PORT
      LAYER M4 ;
        RECT  0 19.008 0.192 19.032 ;
    END
  END o0[86]
  PIN o0[87]
    DIRECTION OUTPUT ;
    USE SIGNAL ;
    PORT
      LAYER M4 ;
        RECT  0 19.2 0.192 19.224 ;
    END
  END o0[87]
  PIN o0[88]
    DIRECTION OUTPUT ;
    USE SIGNAL ;
    PORT
      LAYER M4 ;
        RECT  0 19.344 0.192 19.368 ;
    END
  END o0[88]
  PIN o0[89]
    DIRECTION OUTPUT ;
    USE SIGNAL ;
    PORT
      LAYER M4 ;
        RECT  0 19.536 0.192 19.56 ;
    END
  END o0[89]
  PIN o0[8]
    DIRECTION OUTPUT ;
    USE SIGNAL ;
    PORT
      LAYER M4 ;
        RECT  0 5.856 0.192 5.88 ;
    END
  END o0[8]
  PIN o0[90]
    DIRECTION OUTPUT ;
    USE SIGNAL ;
    PORT
      LAYER M4 ;
        RECT  0 19.68 0.192 19.704 ;
    END
  END o0[90]
  PIN o0[91]
    DIRECTION OUTPUT ;
    USE SIGNAL ;
    PORT
      LAYER M4 ;
        RECT  0 19.824 0.192 19.848 ;
    END
  END o0[91]
  PIN o0[92]
    DIRECTION OUTPUT ;
    USE SIGNAL ;
    PORT
      LAYER M4 ;
        RECT  0 20.016 0.192 20.04 ;
    END
  END o0[92]
  PIN o0[93]
    DIRECTION OUTPUT ;
    USE SIGNAL ;
    PORT
      LAYER M4 ;
        RECT  0 20.16 0.192 20.184 ;
    END
  END o0[93]
  PIN o0[94]
    DIRECTION OUTPUT ;
    USE SIGNAL ;
    PORT
      LAYER M4 ;
        RECT  0 20.352 0.192 20.376 ;
    END
  END o0[94]
  PIN o0[95]
    DIRECTION OUTPUT ;
    USE SIGNAL ;
    PORT
      LAYER M4 ;
        RECT  0 20.496 0.192 20.52 ;
    END
  END o0[95]
  PIN o0[96]
    DIRECTION OUTPUT ;
    USE SIGNAL ;
    PORT
      LAYER M4 ;
        RECT  0 20.688 0.192 20.712 ;
    END
  END o0[96]
  PIN o0[97]
    DIRECTION OUTPUT ;
    USE SIGNAL ;
    PORT
      LAYER M4 ;
        RECT  0 20.832 0.192 20.856 ;
    END
  END o0[97]
  PIN o0[98]
    DIRECTION OUTPUT ;
    USE SIGNAL ;
    PORT
      LAYER M4 ;
        RECT  0 21.024 0.192 21.048 ;
    END
  END o0[98]
  PIN o0[99]
    DIRECTION OUTPUT ;
    USE SIGNAL ;
    PORT
      LAYER M4 ;
        RECT  0 21.168 0.192 21.192 ;
    END
  END o0[99]
  PIN o0[9]
    DIRECTION OUTPUT ;
    USE SIGNAL ;
    PORT
      LAYER M4 ;
        RECT  0 6.048 0.192 6.072 ;
    END
  END o0[9]
  PIN o1[0]
    DIRECTION OUTPUT ;
    USE SIGNAL ;
    PORT
      LAYER M4 ;
        RECT  0 27.552 0.192 27.576 ;
    END
  END o1[0]
  PIN o1[100]
    DIRECTION OUTPUT ;
    USE SIGNAL ;
    PORT
      LAYER M4 ;
        RECT  0 44.4 0.192 44.424 ;
    END
  END o1[100]
  PIN o1[101]
    DIRECTION OUTPUT ;
    USE SIGNAL ;
    PORT
      LAYER M4 ;
        RECT  0 44.544 0.192 44.568 ;
    END
  END o1[101]
  PIN o1[102]
    DIRECTION OUTPUT ;
    USE SIGNAL ;
    PORT
      LAYER M4 ;
        RECT  0 44.736 0.192 44.76 ;
    END
  END o1[102]
  PIN o1[103]
    DIRECTION OUTPUT ;
    USE SIGNAL ;
    PORT
      LAYER M4 ;
        RECT  0 44.88 0.192 44.904 ;
    END
  END o1[103]
  PIN o1[104]
    DIRECTION OUTPUT ;
    USE SIGNAL ;
    PORT
      LAYER M4 ;
        RECT  0 45.072 0.192 45.096 ;
    END
  END o1[104]
  PIN o1[105]
    DIRECTION OUTPUT ;
    USE SIGNAL ;
    PORT
      LAYER M4 ;
        RECT  0 45.216 0.192 45.24 ;
    END
  END o1[105]
  PIN o1[106]
    DIRECTION OUTPUT ;
    USE SIGNAL ;
    PORT
      LAYER M4 ;
        RECT  0 45.408 0.192 45.432 ;
    END
  END o1[106]
  PIN o1[107]
    DIRECTION OUTPUT ;
    USE SIGNAL ;
    PORT
      LAYER M4 ;
        RECT  0 45.552 0.192 45.576 ;
    END
  END o1[107]
  PIN o1[108]
    DIRECTION OUTPUT ;
    USE SIGNAL ;
    PORT
      LAYER M4 ;
        RECT  0 45.696 0.192 45.72 ;
    END
  END o1[108]
  PIN o1[109]
    DIRECTION OUTPUT ;
    USE SIGNAL ;
    PORT
      LAYER M4 ;
        RECT  0 45.888 0.192 45.912 ;
    END
  END o1[109]
  PIN o1[10]
    DIRECTION OUTPUT ;
    USE SIGNAL ;
    PORT
      LAYER M4 ;
        RECT  0 29.232 0.192 29.256 ;
    END
  END o1[10]
  PIN o1[110]
    DIRECTION OUTPUT ;
    USE SIGNAL ;
    PORT
      LAYER M4 ;
        RECT  0 46.032 0.192 46.056 ;
    END
  END o1[110]
  PIN o1[111]
    DIRECTION OUTPUT ;
    USE SIGNAL ;
    PORT
      LAYER M4 ;
        RECT  0 46.224 0.192 46.248 ;
    END
  END o1[111]
  PIN o1[112]
    DIRECTION OUTPUT ;
    USE SIGNAL ;
    PORT
      LAYER M4 ;
        RECT  0 46.368 0.192 46.392 ;
    END
  END o1[112]
  PIN o1[113]
    DIRECTION OUTPUT ;
    USE SIGNAL ;
    PORT
      LAYER M4 ;
        RECT  0 46.56 0.192 46.584 ;
    END
  END o1[113]
  PIN o1[114]
    DIRECTION OUTPUT ;
    USE SIGNAL ;
    PORT
      LAYER M4 ;
        RECT  0 46.704 0.192 46.728 ;
    END
  END o1[114]
  PIN o1[115]
    DIRECTION OUTPUT ;
    USE SIGNAL ;
    PORT
      LAYER M4 ;
        RECT  0 46.896 0.192 46.92 ;
    END
  END o1[115]
  PIN o1[116]
    DIRECTION OUTPUT ;
    USE SIGNAL ;
    PORT
      LAYER M4 ;
        RECT  0 47.04 0.192 47.064 ;
    END
  END o1[116]
  PIN o1[117]
    DIRECTION OUTPUT ;
    USE SIGNAL ;
    PORT
      LAYER M4 ;
        RECT  0 47.232 0.192 47.256 ;
    END
  END o1[117]
  PIN o1[118]
    DIRECTION OUTPUT ;
    USE SIGNAL ;
    PORT
      LAYER M4 ;
        RECT  0 47.376 0.192 47.4 ;
    END
  END o1[118]
  PIN o1[119]
    DIRECTION OUTPUT ;
    USE SIGNAL ;
    PORT
      LAYER M4 ;
        RECT  0 47.568 0.192 47.592 ;
    END
  END o1[119]
  PIN o1[11]
    DIRECTION OUTPUT ;
    USE SIGNAL ;
    PORT
      LAYER M4 ;
        RECT  0 29.424 0.192 29.448 ;
    END
  END o1[11]
  PIN o1[120]
    DIRECTION OUTPUT ;
    USE SIGNAL ;
    PORT
      LAYER M4 ;
        RECT  0 47.712 0.192 47.736 ;
    END
  END o1[120]
  PIN o1[121]
    DIRECTION OUTPUT ;
    USE SIGNAL ;
    PORT
      LAYER M4 ;
        RECT  0 47.904 0.192 47.928 ;
    END
  END o1[121]
  PIN o1[122]
    DIRECTION OUTPUT ;
    USE SIGNAL ;
    PORT
      LAYER M4 ;
        RECT  0 48.048 0.192 48.072 ;
    END
  END o1[122]
  PIN o1[123]
    DIRECTION OUTPUT ;
    USE SIGNAL ;
    PORT
      LAYER M4 ;
        RECT  0 48.192 0.192 48.216 ;
    END
  END o1[123]
  PIN o1[124]
    DIRECTION OUTPUT ;
    USE SIGNAL ;
    PORT
      LAYER M4 ;
        RECT  0 48.384 0.192 48.408 ;
    END
  END o1[124]
  PIN o1[125]
    DIRECTION OUTPUT ;
    USE SIGNAL ;
    PORT
      LAYER M4 ;
        RECT  0 48.528 0.192 48.552 ;
    END
  END o1[125]
  PIN o1[126]
    DIRECTION OUTPUT ;
    USE SIGNAL ;
    PORT
      LAYER M4 ;
        RECT  0 48.72 0.192 48.744 ;
    END
  END o1[126]
  PIN o1[127]
    DIRECTION OUTPUT ;
    USE SIGNAL ;
    PORT
      LAYER M4 ;
        RECT  0 48.864 0.192 48.888 ;
    END
  END o1[127]
  PIN o1[128]
    DIRECTION OUTPUT ;
    USE SIGNAL ;
    PORT
      LAYER M4 ;
        RECT  0 49.056 0.192 49.08 ;
    END
  END o1[128]
  PIN o1[129]
    DIRECTION OUTPUT ;
    USE SIGNAL ;
    PORT
      LAYER M4 ;
        RECT  0 49.2 0.192 49.224 ;
    END
  END o1[129]
  PIN o1[12]
    DIRECTION OUTPUT ;
    USE SIGNAL ;
    PORT
      LAYER M4 ;
        RECT  0 29.568 0.192 29.592 ;
    END
  END o1[12]
  PIN o1[130]
    DIRECTION OUTPUT ;
    USE SIGNAL ;
    PORT
      LAYER M4 ;
        RECT  0 49.392 0.192 49.416 ;
    END
  END o1[130]
  PIN o1[131]
    DIRECTION OUTPUT ;
    USE SIGNAL ;
    PORT
      LAYER M4 ;
        RECT  0 49.536 0.192 49.56 ;
    END
  END o1[131]
  PIN o1[132]
    DIRECTION OUTPUT ;
    USE SIGNAL ;
    PORT
      LAYER M4 ;
        RECT  0 49.728 0.192 49.752 ;
    END
  END o1[132]
  PIN o1[133]
    DIRECTION OUTPUT ;
    USE SIGNAL ;
    PORT
      LAYER M4 ;
        RECT  0 49.872 0.192 49.896 ;
    END
  END o1[133]
  PIN o1[134]
    DIRECTION OUTPUT ;
    USE SIGNAL ;
    PORT
      LAYER M4 ;
        RECT  0 50.064 0.192 50.088 ;
    END
  END o1[134]
  PIN o1[135]
    DIRECTION OUTPUT ;
    USE SIGNAL ;
    PORT
      LAYER M4 ;
        RECT  0 50.208 0.192 50.232 ;
    END
  END o1[135]
  PIN o1[13]
    DIRECTION OUTPUT ;
    USE SIGNAL ;
    PORT
      LAYER M4 ;
        RECT  0 29.76 0.192 29.784 ;
    END
  END o1[13]
  PIN o1[14]
    DIRECTION OUTPUT ;
    USE SIGNAL ;
    PORT
      LAYER M4 ;
        RECT  0 29.904 0.192 29.928 ;
    END
  END o1[14]
  PIN o1[15]
    DIRECTION OUTPUT ;
    USE SIGNAL ;
    PORT
      LAYER M4 ;
        RECT  0 30.048 0.192 30.072 ;
    END
  END o1[15]
  PIN o1[16]
    DIRECTION OUTPUT ;
    USE SIGNAL ;
    PORT
      LAYER M4 ;
        RECT  0 30.24 0.192 30.264 ;
    END
  END o1[16]
  PIN o1[17]
    DIRECTION OUTPUT ;
    USE SIGNAL ;
    PORT
      LAYER M4 ;
        RECT  0 30.384 0.192 30.408 ;
    END
  END o1[17]
  PIN o1[18]
    DIRECTION OUTPUT ;
    USE SIGNAL ;
    PORT
      LAYER M4 ;
        RECT  0 30.576 0.192 30.6 ;
    END
  END o1[18]
  PIN o1[19]
    DIRECTION OUTPUT ;
    USE SIGNAL ;
    PORT
      LAYER M4 ;
        RECT  0 30.72 0.192 30.744 ;
    END
  END o1[19]
  PIN o1[1]
    DIRECTION OUTPUT ;
    USE SIGNAL ;
    PORT
      LAYER M4 ;
        RECT  0 27.744 0.192 27.768 ;
    END
  END o1[1]
  PIN o1[20]
    DIRECTION OUTPUT ;
    USE SIGNAL ;
    PORT
      LAYER M4 ;
        RECT  0 30.912 0.192 30.936 ;
    END
  END o1[20]
  PIN o1[21]
    DIRECTION OUTPUT ;
    USE SIGNAL ;
    PORT
      LAYER M4 ;
        RECT  0 31.056 0.192 31.08 ;
    END
  END o1[21]
  PIN o1[22]
    DIRECTION OUTPUT ;
    USE SIGNAL ;
    PORT
      LAYER M4 ;
        RECT  0 31.248 0.192 31.272 ;
    END
  END o1[22]
  PIN o1[23]
    DIRECTION OUTPUT ;
    USE SIGNAL ;
    PORT
      LAYER M4 ;
        RECT  0 31.392 0.192 31.416 ;
    END
  END o1[23]
  PIN o1[24]
    DIRECTION OUTPUT ;
    USE SIGNAL ;
    PORT
      LAYER M4 ;
        RECT  0 31.584 0.192 31.608 ;
    END
  END o1[24]
  PIN o1[25]
    DIRECTION OUTPUT ;
    USE SIGNAL ;
    PORT
      LAYER M4 ;
        RECT  0 31.728 0.192 31.752 ;
    END
  END o1[25]
  PIN o1[26]
    DIRECTION OUTPUT ;
    USE SIGNAL ;
    PORT
      LAYER M4 ;
        RECT  0 31.92 0.192 31.944 ;
    END
  END o1[26]
  PIN o1[27]
    DIRECTION OUTPUT ;
    USE SIGNAL ;
    PORT
      LAYER M4 ;
        RECT  0 32.064 0.192 32.088 ;
    END
  END o1[27]
  PIN o1[28]
    DIRECTION OUTPUT ;
    USE SIGNAL ;
    PORT
      LAYER M4 ;
        RECT  0 32.256 0.192 32.28 ;
    END
  END o1[28]
  PIN o1[29]
    DIRECTION OUTPUT ;
    USE SIGNAL ;
    PORT
      LAYER M4 ;
        RECT  0 32.4 0.192 32.424 ;
    END
  END o1[29]
  PIN o1[2]
    DIRECTION OUTPUT ;
    USE SIGNAL ;
    PORT
      LAYER M4 ;
        RECT  0 27.888 0.192 27.912 ;
    END
  END o1[2]
  PIN o1[30]
    DIRECTION OUTPUT ;
    USE SIGNAL ;
    PORT
      LAYER M4 ;
        RECT  0 32.544 0.192 32.568 ;
    END
  END o1[30]
  PIN o1[31]
    DIRECTION OUTPUT ;
    USE SIGNAL ;
    PORT
      LAYER M4 ;
        RECT  0 32.736 0.192 32.76 ;
    END
  END o1[31]
  PIN o1[32]
    DIRECTION OUTPUT ;
    USE SIGNAL ;
    PORT
      LAYER M4 ;
        RECT  0 32.88 0.192 32.904 ;
    END
  END o1[32]
  PIN o1[33]
    DIRECTION OUTPUT ;
    USE SIGNAL ;
    PORT
      LAYER M4 ;
        RECT  0 33.072 0.192 33.096 ;
    END
  END o1[33]
  PIN o1[34]
    DIRECTION OUTPUT ;
    USE SIGNAL ;
    PORT
      LAYER M4 ;
        RECT  0 33.216 0.192 33.24 ;
    END
  END o1[34]
  PIN o1[35]
    DIRECTION OUTPUT ;
    USE SIGNAL ;
    PORT
      LAYER M4 ;
        RECT  0 33.408 0.192 33.432 ;
    END
  END o1[35]
  PIN o1[36]
    DIRECTION OUTPUT ;
    USE SIGNAL ;
    PORT
      LAYER M4 ;
        RECT  0 33.552 0.192 33.576 ;
    END
  END o1[36]
  PIN o1[37]
    DIRECTION OUTPUT ;
    USE SIGNAL ;
    PORT
      LAYER M4 ;
        RECT  0 33.744 0.192 33.768 ;
    END
  END o1[37]
  PIN o1[38]
    DIRECTION OUTPUT ;
    USE SIGNAL ;
    PORT
      LAYER M4 ;
        RECT  0 33.888 0.192 33.912 ;
    END
  END o1[38]
  PIN o1[39]
    DIRECTION OUTPUT ;
    USE SIGNAL ;
    PORT
      LAYER M4 ;
        RECT  0 34.08 0.192 34.104 ;
    END
  END o1[39]
  PIN o1[3]
    DIRECTION OUTPUT ;
    USE SIGNAL ;
    PORT
      LAYER M4 ;
        RECT  0 28.08 0.192 28.104 ;
    END
  END o1[3]
  PIN o1[40]
    DIRECTION OUTPUT ;
    USE SIGNAL ;
    PORT
      LAYER M4 ;
        RECT  0 34.224 0.192 34.248 ;
    END
  END o1[40]
  PIN o1[41]
    DIRECTION OUTPUT ;
    USE SIGNAL ;
    PORT
      LAYER M4 ;
        RECT  0 34.416 0.192 34.44 ;
    END
  END o1[41]
  PIN o1[42]
    DIRECTION OUTPUT ;
    USE SIGNAL ;
    PORT
      LAYER M4 ;
        RECT  0 34.56 0.192 34.584 ;
    END
  END o1[42]
  PIN o1[43]
    DIRECTION OUTPUT ;
    USE SIGNAL ;
    PORT
      LAYER M4 ;
        RECT  0 34.752 0.192 34.776 ;
    END
  END o1[43]
  PIN o1[44]
    DIRECTION OUTPUT ;
    USE SIGNAL ;
    PORT
      LAYER M4 ;
        RECT  0 34.896 0.192 34.92 ;
    END
  END o1[44]
  PIN o1[45]
    DIRECTION OUTPUT ;
    USE SIGNAL ;
    PORT
      LAYER M4 ;
        RECT  0 35.04 0.192 35.064 ;
    END
  END o1[45]
  PIN o1[46]
    DIRECTION OUTPUT ;
    USE SIGNAL ;
    PORT
      LAYER M4 ;
        RECT  0 35.232 0.192 35.256 ;
    END
  END o1[46]
  PIN o1[47]
    DIRECTION OUTPUT ;
    USE SIGNAL ;
    PORT
      LAYER M4 ;
        RECT  0 35.376 0.192 35.4 ;
    END
  END o1[47]
  PIN o1[48]
    DIRECTION OUTPUT ;
    USE SIGNAL ;
    PORT
      LAYER M4 ;
        RECT  0 35.568 0.192 35.592 ;
    END
  END o1[48]
  PIN o1[49]
    DIRECTION OUTPUT ;
    USE SIGNAL ;
    PORT
      LAYER M4 ;
        RECT  0 35.712 0.192 35.736 ;
    END
  END o1[49]
  PIN o1[4]
    DIRECTION OUTPUT ;
    USE SIGNAL ;
    PORT
      LAYER M4 ;
        RECT  0 28.224 0.192 28.248 ;
    END
  END o1[4]
  PIN o1[50]
    DIRECTION OUTPUT ;
    USE SIGNAL ;
    PORT
      LAYER M4 ;
        RECT  0 35.904 0.192 35.928 ;
    END
  END o1[50]
  PIN o1[51]
    DIRECTION OUTPUT ;
    USE SIGNAL ;
    PORT
      LAYER M4 ;
        RECT  0 36.048 0.192 36.072 ;
    END
  END o1[51]
  PIN o1[52]
    DIRECTION OUTPUT ;
    USE SIGNAL ;
    PORT
      LAYER M4 ;
        RECT  0 36.24 0.192 36.264 ;
    END
  END o1[52]
  PIN o1[53]
    DIRECTION OUTPUT ;
    USE SIGNAL ;
    PORT
      LAYER M4 ;
        RECT  0 36.384 0.192 36.408 ;
    END
  END o1[53]
  PIN o1[54]
    DIRECTION OUTPUT ;
    USE SIGNAL ;
    PORT
      LAYER M4 ;
        RECT  0 36.576 0.192 36.6 ;
    END
  END o1[54]
  PIN o1[55]
    DIRECTION OUTPUT ;
    USE SIGNAL ;
    PORT
      LAYER M4 ;
        RECT  0 36.72 0.192 36.744 ;
    END
  END o1[55]
  PIN o1[56]
    DIRECTION OUTPUT ;
    USE SIGNAL ;
    PORT
      LAYER M4 ;
        RECT  0 36.912 0.192 36.936 ;
    END
  END o1[56]
  PIN o1[57]
    DIRECTION OUTPUT ;
    USE SIGNAL ;
    PORT
      LAYER M4 ;
        RECT  0 37.056 0.192 37.08 ;
    END
  END o1[57]
  PIN o1[58]
    DIRECTION OUTPUT ;
    USE SIGNAL ;
    PORT
      LAYER M4 ;
        RECT  0 37.248 0.192 37.272 ;
    END
  END o1[58]
  PIN o1[59]
    DIRECTION OUTPUT ;
    USE SIGNAL ;
    PORT
      LAYER M4 ;
        RECT  0 37.392 0.192 37.416 ;
    END
  END o1[59]
  PIN o1[5]
    DIRECTION OUTPUT ;
    USE SIGNAL ;
    PORT
      LAYER M4 ;
        RECT  0 28.416 0.192 28.44 ;
    END
  END o1[5]
  PIN o1[60]
    DIRECTION OUTPUT ;
    USE SIGNAL ;
    PORT
      LAYER M4 ;
        RECT  0 37.584 0.192 37.608 ;
    END
  END o1[60]
  PIN o1[61]
    DIRECTION OUTPUT ;
    USE SIGNAL ;
    PORT
      LAYER M4 ;
        RECT  0 37.728 0.192 37.752 ;
    END
  END o1[61]
  PIN o1[62]
    DIRECTION OUTPUT ;
    USE SIGNAL ;
    PORT
      LAYER M4 ;
        RECT  0 37.872 0.192 37.896 ;
    END
  END o1[62]
  PIN o1[63]
    DIRECTION OUTPUT ;
    USE SIGNAL ;
    PORT
      LAYER M4 ;
        RECT  0 38.064 0.192 38.088 ;
    END
  END o1[63]
  PIN o1[64]
    DIRECTION OUTPUT ;
    USE SIGNAL ;
    PORT
      LAYER M4 ;
        RECT  0 38.208 0.192 38.232 ;
    END
  END o1[64]
  PIN o1[65]
    DIRECTION OUTPUT ;
    USE SIGNAL ;
    PORT
      LAYER M4 ;
        RECT  0 38.4 0.192 38.424 ;
    END
  END o1[65]
  PIN o1[66]
    DIRECTION OUTPUT ;
    USE SIGNAL ;
    PORT
      LAYER M4 ;
        RECT  0 38.544 0.192 38.568 ;
    END
  END o1[66]
  PIN o1[67]
    DIRECTION OUTPUT ;
    USE SIGNAL ;
    PORT
      LAYER M4 ;
        RECT  0 38.736 0.192 38.76 ;
    END
  END o1[67]
  PIN o1[68]
    DIRECTION OUTPUT ;
    USE SIGNAL ;
    PORT
      LAYER M4 ;
        RECT  0 39.072 0.192 39.096 ;
    END
  END o1[68]
  PIN o1[69]
    DIRECTION OUTPUT ;
    USE SIGNAL ;
    PORT
      LAYER M4 ;
        RECT  0 39.216 0.192 39.24 ;
    END
  END o1[69]
  PIN o1[6]
    DIRECTION OUTPUT ;
    USE SIGNAL ;
    PORT
      LAYER M4 ;
        RECT  0 28.56 0.192 28.584 ;
    END
  END o1[6]
  PIN o1[70]
    DIRECTION OUTPUT ;
    USE SIGNAL ;
    PORT
      LAYER M4 ;
        RECT  0 39.408 0.192 39.432 ;
    END
  END o1[70]
  PIN o1[71]
    DIRECTION OUTPUT ;
    USE SIGNAL ;
    PORT
      LAYER M4 ;
        RECT  0 39.552 0.192 39.576 ;
    END
  END o1[71]
  PIN o1[72]
    DIRECTION OUTPUT ;
    USE SIGNAL ;
    PORT
      LAYER M4 ;
        RECT  0 39.744 0.192 39.768 ;
    END
  END o1[72]
  PIN o1[73]
    DIRECTION OUTPUT ;
    USE SIGNAL ;
    PORT
      LAYER M4 ;
        RECT  0 39.888 0.192 39.912 ;
    END
  END o1[73]
  PIN o1[74]
    DIRECTION OUTPUT ;
    USE SIGNAL ;
    PORT
      LAYER M4 ;
        RECT  0 40.08 0.192 40.104 ;
    END
  END o1[74]
  PIN o1[75]
    DIRECTION OUTPUT ;
    USE SIGNAL ;
    PORT
      LAYER M4 ;
        RECT  0 40.224 0.192 40.248 ;
    END
  END o1[75]
  PIN o1[76]
    DIRECTION OUTPUT ;
    USE SIGNAL ;
    PORT
      LAYER M4 ;
        RECT  0 40.368 0.192 40.392 ;
    END
  END o1[76]
  PIN o1[77]
    DIRECTION OUTPUT ;
    USE SIGNAL ;
    PORT
      LAYER M4 ;
        RECT  0 40.56 0.192 40.584 ;
    END
  END o1[77]
  PIN o1[78]
    DIRECTION OUTPUT ;
    USE SIGNAL ;
    PORT
      LAYER M4 ;
        RECT  0 40.704 0.192 40.728 ;
    END
  END o1[78]
  PIN o1[79]
    DIRECTION OUTPUT ;
    USE SIGNAL ;
    PORT
      LAYER M4 ;
        RECT  0 40.896 0.192 40.92 ;
    END
  END o1[79]
  PIN o1[7]
    DIRECTION OUTPUT ;
    USE SIGNAL ;
    PORT
      LAYER M4 ;
        RECT  0 28.752 0.192 28.776 ;
    END
  END o1[7]
  PIN o1[80]
    DIRECTION OUTPUT ;
    USE SIGNAL ;
    PORT
      LAYER M4 ;
        RECT  0 41.04 0.192 41.064 ;
    END
  END o1[80]
  PIN o1[81]
    DIRECTION OUTPUT ;
    USE SIGNAL ;
    PORT
      LAYER M4 ;
        RECT  0 41.232 0.192 41.256 ;
    END
  END o1[81]
  PIN o1[82]
    DIRECTION OUTPUT ;
    USE SIGNAL ;
    PORT
      LAYER M4 ;
        RECT  0 41.376 0.192 41.4 ;
    END
  END o1[82]
  PIN o1[83]
    DIRECTION OUTPUT ;
    USE SIGNAL ;
    PORT
      LAYER M4 ;
        RECT  0 41.568 0.192 41.592 ;
    END
  END o1[83]
  PIN o1[84]
    DIRECTION OUTPUT ;
    USE SIGNAL ;
    PORT
      LAYER M4 ;
        RECT  0 41.712 0.192 41.736 ;
    END
  END o1[84]
  PIN o1[85]
    DIRECTION OUTPUT ;
    USE SIGNAL ;
    PORT
      LAYER M4 ;
        RECT  0 41.904 0.192 41.928 ;
    END
  END o1[85]
  PIN o1[86]
    DIRECTION OUTPUT ;
    USE SIGNAL ;
    PORT
      LAYER M4 ;
        RECT  0 42.048 0.192 42.072 ;
    END
  END o1[86]
  PIN o1[87]
    DIRECTION OUTPUT ;
    USE SIGNAL ;
    PORT
      LAYER M4 ;
        RECT  0 42.24 0.192 42.264 ;
    END
  END o1[87]
  PIN o1[88]
    DIRECTION OUTPUT ;
    USE SIGNAL ;
    PORT
      LAYER M4 ;
        RECT  0 42.384 0.192 42.408 ;
    END
  END o1[88]
  PIN o1[89]
    DIRECTION OUTPUT ;
    USE SIGNAL ;
    PORT
      LAYER M4 ;
        RECT  0 42.576 0.192 42.6 ;
    END
  END o1[89]
  PIN o1[8]
    DIRECTION OUTPUT ;
    USE SIGNAL ;
    PORT
      LAYER M4 ;
        RECT  0 28.896 0.192 28.92 ;
    END
  END o1[8]
  PIN o1[90]
    DIRECTION OUTPUT ;
    USE SIGNAL ;
    PORT
      LAYER M4 ;
        RECT  0 42.72 0.192 42.744 ;
    END
  END o1[90]
  PIN o1[91]
    DIRECTION OUTPUT ;
    USE SIGNAL ;
    PORT
      LAYER M4 ;
        RECT  0 42.864 0.192 42.888 ;
    END
  END o1[91]
  PIN o1[92]
    DIRECTION OUTPUT ;
    USE SIGNAL ;
    PORT
      LAYER M4 ;
        RECT  0 43.056 0.192 43.08 ;
    END
  END o1[92]
  PIN o1[93]
    DIRECTION OUTPUT ;
    USE SIGNAL ;
    PORT
      LAYER M4 ;
        RECT  0 43.2 0.192 43.224 ;
    END
  END o1[93]
  PIN o1[94]
    DIRECTION OUTPUT ;
    USE SIGNAL ;
    PORT
      LAYER M4 ;
        RECT  0 43.392 0.192 43.416 ;
    END
  END o1[94]
  PIN o1[95]
    DIRECTION OUTPUT ;
    USE SIGNAL ;
    PORT
      LAYER M4 ;
        RECT  0 43.536 0.192 43.56 ;
    END
  END o1[95]
  PIN o1[96]
    DIRECTION OUTPUT ;
    USE SIGNAL ;
    PORT
      LAYER M4 ;
        RECT  0 43.728 0.192 43.752 ;
    END
  END o1[96]
  PIN o1[97]
    DIRECTION OUTPUT ;
    USE SIGNAL ;
    PORT
      LAYER M4 ;
        RECT  0 43.872 0.192 43.896 ;
    END
  END o1[97]
  PIN o1[98]
    DIRECTION OUTPUT ;
    USE SIGNAL ;
    PORT
      LAYER M4 ;
        RECT  0 44.064 0.192 44.088 ;
    END
  END o1[98]
  PIN o1[99]
    DIRECTION OUTPUT ;
    USE SIGNAL ;
    PORT
      LAYER M4 ;
        RECT  0 44.208 0.192 44.232 ;
    END
  END o1[99]
  PIN o1[9]
    DIRECTION OUTPUT ;
    USE SIGNAL ;
    PORT
      LAYER M4 ;
        RECT  0 29.088 0.192 29.112 ;
    END
  END o1[9]
  PIN o2[0]
    DIRECTION OUTPUT ;
    USE SIGNAL ;
    PORT
      LAYER M4 ;
        RECT  21.408 39.072 21.6 39.096 ;
    END
  END o2[0]
  PIN o2[100]
    DIRECTION OUTPUT ;
    USE SIGNAL ;
    PORT
      LAYER M4 ;
        RECT  21.408 64.464 21.6 64.488 ;
    END
  END o2[100]
  PIN o2[101]
    DIRECTION OUTPUT ;
    USE SIGNAL ;
    PORT
      LAYER M4 ;
        RECT  21.408 64.704 21.6 64.728 ;
    END
  END o2[101]
  PIN o2[102]
    DIRECTION OUTPUT ;
    USE SIGNAL ;
    PORT
      LAYER M4 ;
        RECT  21.408 64.944 21.6 64.968 ;
    END
  END o2[102]
  PIN o2[103]
    DIRECTION OUTPUT ;
    USE SIGNAL ;
    PORT
      LAYER M4 ;
        RECT  21.408 65.232 21.6 65.256 ;
    END
  END o2[103]
  PIN o2[104]
    DIRECTION OUTPUT ;
    USE SIGNAL ;
    PORT
      LAYER M4 ;
        RECT  21.408 65.472 21.6 65.496 ;
    END
  END o2[104]
  PIN o2[105]
    DIRECTION OUTPUT ;
    USE SIGNAL ;
    PORT
      LAYER M4 ;
        RECT  21.408 65.712 21.6 65.736 ;
    END
  END o2[105]
  PIN o2[106]
    DIRECTION OUTPUT ;
    USE SIGNAL ;
    PORT
      LAYER M4 ;
        RECT  21.408 65.952 21.6 65.976 ;
    END
  END o2[106]
  PIN o2[107]
    DIRECTION OUTPUT ;
    USE SIGNAL ;
    PORT
      LAYER M4 ;
        RECT  21.408 66.24 21.6 66.264 ;
    END
  END o2[107]
  PIN o2[108]
    DIRECTION OUTPUT ;
    USE SIGNAL ;
    PORT
      LAYER M4 ;
        RECT  21.408 66.48 21.6 66.504 ;
    END
  END o2[108]
  PIN o2[109]
    DIRECTION OUTPUT ;
    USE SIGNAL ;
    PORT
      LAYER M4 ;
        RECT  21.408 66.72 21.6 66.744 ;
    END
  END o2[109]
  PIN o2[10]
    DIRECTION OUTPUT ;
    USE SIGNAL ;
    PORT
      LAYER M4 ;
        RECT  21.408 41.616 21.6 41.64 ;
    END
  END o2[10]
  PIN o2[110]
    DIRECTION OUTPUT ;
    USE SIGNAL ;
    PORT
      LAYER M4 ;
        RECT  21.408 66.96 21.6 66.984 ;
    END
  END o2[110]
  PIN o2[111]
    DIRECTION OUTPUT ;
    USE SIGNAL ;
    PORT
      LAYER M4 ;
        RECT  21.408 67.2 21.6 67.224 ;
    END
  END o2[111]
  PIN o2[112]
    DIRECTION OUTPUT ;
    USE SIGNAL ;
    PORT
      LAYER M4 ;
        RECT  21.408 67.488 21.6 67.512 ;
    END
  END o2[112]
  PIN o2[113]
    DIRECTION OUTPUT ;
    USE SIGNAL ;
    PORT
      LAYER M4 ;
        RECT  21.408 67.728 21.6 67.752 ;
    END
  END o2[113]
  PIN o2[114]
    DIRECTION OUTPUT ;
    USE SIGNAL ;
    PORT
      LAYER M4 ;
        RECT  21.408 67.968 21.6 67.992 ;
    END
  END o2[114]
  PIN o2[115]
    DIRECTION OUTPUT ;
    USE SIGNAL ;
    PORT
      LAYER M4 ;
        RECT  21.408 68.208 21.6 68.232 ;
    END
  END o2[115]
  PIN o2[116]
    DIRECTION OUTPUT ;
    USE SIGNAL ;
    PORT
      LAYER M4 ;
        RECT  21.408 68.496 21.6 68.52 ;
    END
  END o2[116]
  PIN o2[117]
    DIRECTION OUTPUT ;
    USE SIGNAL ;
    PORT
      LAYER M4 ;
        RECT  21.408 68.736 21.6 68.76 ;
    END
  END o2[117]
  PIN o2[118]
    DIRECTION OUTPUT ;
    USE SIGNAL ;
    PORT
      LAYER M4 ;
        RECT  21.408 68.976 21.6 69 ;
    END
  END o2[118]
  PIN o2[119]
    DIRECTION OUTPUT ;
    USE SIGNAL ;
    PORT
      LAYER M4 ;
        RECT  21.408 69.216 21.6 69.24 ;
    END
  END o2[119]
  PIN o2[11]
    DIRECTION OUTPUT ;
    USE SIGNAL ;
    PORT
      LAYER M4 ;
        RECT  21.408 41.856 21.6 41.88 ;
    END
  END o2[11]
  PIN o2[120]
    DIRECTION OUTPUT ;
    USE SIGNAL ;
    PORT
      LAYER M4 ;
        RECT  21.408 69.504 21.6 69.528 ;
    END
  END o2[120]
  PIN o2[121]
    DIRECTION OUTPUT ;
    USE SIGNAL ;
    PORT
      LAYER M4 ;
        RECT  21.408 69.744 21.6 69.768 ;
    END
  END o2[121]
  PIN o2[122]
    DIRECTION OUTPUT ;
    USE SIGNAL ;
    PORT
      LAYER M4 ;
        RECT  21.408 69.984 21.6 70.008 ;
    END
  END o2[122]
  PIN o2[123]
    DIRECTION OUTPUT ;
    USE SIGNAL ;
    PORT
      LAYER M4 ;
        RECT  21.408 70.224 21.6 70.248 ;
    END
  END o2[123]
  PIN o2[124]
    DIRECTION OUTPUT ;
    USE SIGNAL ;
    PORT
      LAYER M4 ;
        RECT  21.408 70.512 21.6 70.536 ;
    END
  END o2[124]
  PIN o2[125]
    DIRECTION OUTPUT ;
    USE SIGNAL ;
    PORT
      LAYER M4 ;
        RECT  21.408 70.752 21.6 70.776 ;
    END
  END o2[125]
  PIN o2[126]
    DIRECTION OUTPUT ;
    USE SIGNAL ;
    PORT
      LAYER M4 ;
        RECT  21.408 70.992 21.6 71.016 ;
    END
  END o2[126]
  PIN o2[127]
    DIRECTION OUTPUT ;
    USE SIGNAL ;
    PORT
      LAYER M4 ;
        RECT  21.408 71.232 21.6 71.256 ;
    END
  END o2[127]
  PIN o2[128]
    DIRECTION OUTPUT ;
    USE SIGNAL ;
    PORT
      LAYER M4 ;
        RECT  21.408 71.472 21.6 71.496 ;
    END
  END o2[128]
  PIN o2[129]
    DIRECTION OUTPUT ;
    USE SIGNAL ;
    PORT
      LAYER M4 ;
        RECT  21.408 71.76 21.6 71.784 ;
    END
  END o2[129]
  PIN o2[12]
    DIRECTION OUTPUT ;
    USE SIGNAL ;
    PORT
      LAYER M4 ;
        RECT  21.408 42.096 21.6 42.12 ;
    END
  END o2[12]
  PIN o2[130]
    DIRECTION OUTPUT ;
    USE SIGNAL ;
    PORT
      LAYER M4 ;
        RECT  21.408 72 21.6 72.024 ;
    END
  END o2[130]
  PIN o2[131]
    DIRECTION OUTPUT ;
    USE SIGNAL ;
    PORT
      LAYER M4 ;
        RECT  21.408 72.24 21.6 72.264 ;
    END
  END o2[131]
  PIN o2[132]
    DIRECTION OUTPUT ;
    USE SIGNAL ;
    PORT
      LAYER M4 ;
        RECT  21.408 72.48 21.6 72.504 ;
    END
  END o2[132]
  PIN o2[133]
    DIRECTION OUTPUT ;
    USE SIGNAL ;
    PORT
      LAYER M4 ;
        RECT  21.408 72.768 21.6 72.792 ;
    END
  END o2[133]
  PIN o2[134]
    DIRECTION OUTPUT ;
    USE SIGNAL ;
    PORT
      LAYER M4 ;
        RECT  21.408 73.008 21.6 73.032 ;
    END
  END o2[134]
  PIN o2[135]
    DIRECTION OUTPUT ;
    USE SIGNAL ;
    PORT
      LAYER M4 ;
        RECT  21.408 73.248 21.6 73.272 ;
    END
  END o2[135]
  PIN o2[13]
    DIRECTION OUTPUT ;
    USE SIGNAL ;
    PORT
      LAYER M4 ;
        RECT  21.408 42.336 21.6 42.36 ;
    END
  END o2[13]
  PIN o2[14]
    DIRECTION OUTPUT ;
    USE SIGNAL ;
    PORT
      LAYER M4 ;
        RECT  21.408 42.624 21.6 42.648 ;
    END
  END o2[14]
  PIN o2[15]
    DIRECTION OUTPUT ;
    USE SIGNAL ;
    PORT
      LAYER M4 ;
        RECT  21.408 42.864 21.6 42.888 ;
    END
  END o2[15]
  PIN o2[16]
    DIRECTION OUTPUT ;
    USE SIGNAL ;
    PORT
      LAYER M4 ;
        RECT  21.408 43.104 21.6 43.128 ;
    END
  END o2[16]
  PIN o2[17]
    DIRECTION OUTPUT ;
    USE SIGNAL ;
    PORT
      LAYER M4 ;
        RECT  21.408 43.344 21.6 43.368 ;
    END
  END o2[17]
  PIN o2[18]
    DIRECTION OUTPUT ;
    USE SIGNAL ;
    PORT
      LAYER M4 ;
        RECT  21.408 43.632 21.6 43.656 ;
    END
  END o2[18]
  PIN o2[19]
    DIRECTION OUTPUT ;
    USE SIGNAL ;
    PORT
      LAYER M4 ;
        RECT  21.408 43.872 21.6 43.896 ;
    END
  END o2[19]
  PIN o2[1]
    DIRECTION OUTPUT ;
    USE SIGNAL ;
    PORT
      LAYER M4 ;
        RECT  21.408 39.36 21.6 39.384 ;
    END
  END o2[1]
  PIN o2[20]
    DIRECTION OUTPUT ;
    USE SIGNAL ;
    PORT
      LAYER M4 ;
        RECT  21.408 44.112 21.6 44.136 ;
    END
  END o2[20]
  PIN o2[21]
    DIRECTION OUTPUT ;
    USE SIGNAL ;
    PORT
      LAYER M4 ;
        RECT  21.408 44.352 21.6 44.376 ;
    END
  END o2[21]
  PIN o2[22]
    DIRECTION OUTPUT ;
    USE SIGNAL ;
    PORT
      LAYER M4 ;
        RECT  21.408 44.64 21.6 44.664 ;
    END
  END o2[22]
  PIN o2[23]
    DIRECTION OUTPUT ;
    USE SIGNAL ;
    PORT
      LAYER M4 ;
        RECT  21.408 44.88 21.6 44.904 ;
    END
  END o2[23]
  PIN o2[24]
    DIRECTION OUTPUT ;
    USE SIGNAL ;
    PORT
      LAYER M4 ;
        RECT  21.408 45.12 21.6 45.144 ;
    END
  END o2[24]
  PIN o2[25]
    DIRECTION OUTPUT ;
    USE SIGNAL ;
    PORT
      LAYER M4 ;
        RECT  21.408 45.36 21.6 45.384 ;
    END
  END o2[25]
  PIN o2[26]
    DIRECTION OUTPUT ;
    USE SIGNAL ;
    PORT
      LAYER M4 ;
        RECT  21.408 45.6 21.6 45.624 ;
    END
  END o2[26]
  PIN o2[27]
    DIRECTION OUTPUT ;
    USE SIGNAL ;
    PORT
      LAYER M4 ;
        RECT  21.408 45.888 21.6 45.912 ;
    END
  END o2[27]
  PIN o2[28]
    DIRECTION OUTPUT ;
    USE SIGNAL ;
    PORT
      LAYER M4 ;
        RECT  21.408 46.128 21.6 46.152 ;
    END
  END o2[28]
  PIN o2[29]
    DIRECTION OUTPUT ;
    USE SIGNAL ;
    PORT
      LAYER M4 ;
        RECT  21.408 46.368 21.6 46.392 ;
    END
  END o2[29]
  PIN o2[2]
    DIRECTION OUTPUT ;
    USE SIGNAL ;
    PORT
      LAYER M4 ;
        RECT  21.408 39.6 21.6 39.624 ;
    END
  END o2[2]
  PIN o2[30]
    DIRECTION OUTPUT ;
    USE SIGNAL ;
    PORT
      LAYER M4 ;
        RECT  21.408 46.608 21.6 46.632 ;
    END
  END o2[30]
  PIN o2[31]
    DIRECTION OUTPUT ;
    USE SIGNAL ;
    PORT
      LAYER M4 ;
        RECT  21.408 46.896 21.6 46.92 ;
    END
  END o2[31]
  PIN o2[32]
    DIRECTION OUTPUT ;
    USE SIGNAL ;
    PORT
      LAYER M4 ;
        RECT  21.408 47.136 21.6 47.16 ;
    END
  END o2[32]
  PIN o2[33]
    DIRECTION OUTPUT ;
    USE SIGNAL ;
    PORT
      LAYER M4 ;
        RECT  21.408 47.376 21.6 47.4 ;
    END
  END o2[33]
  PIN o2[34]
    DIRECTION OUTPUT ;
    USE SIGNAL ;
    PORT
      LAYER M4 ;
        RECT  21.408 47.616 21.6 47.64 ;
    END
  END o2[34]
  PIN o2[35]
    DIRECTION OUTPUT ;
    USE SIGNAL ;
    PORT
      LAYER M4 ;
        RECT  21.408 47.904 21.6 47.928 ;
    END
  END o2[35]
  PIN o2[36]
    DIRECTION OUTPUT ;
    USE SIGNAL ;
    PORT
      LAYER M4 ;
        RECT  21.408 48.144 21.6 48.168 ;
    END
  END o2[36]
  PIN o2[37]
    DIRECTION OUTPUT ;
    USE SIGNAL ;
    PORT
      LAYER M4 ;
        RECT  21.408 48.384 21.6 48.408 ;
    END
  END o2[37]
  PIN o2[38]
    DIRECTION OUTPUT ;
    USE SIGNAL ;
    PORT
      LAYER M4 ;
        RECT  21.408 48.624 21.6 48.648 ;
    END
  END o2[38]
  PIN o2[39]
    DIRECTION OUTPUT ;
    USE SIGNAL ;
    PORT
      LAYER M4 ;
        RECT  21.408 48.864 21.6 48.888 ;
    END
  END o2[39]
  PIN o2[3]
    DIRECTION OUTPUT ;
    USE SIGNAL ;
    PORT
      LAYER M4 ;
        RECT  21.408 39.84 21.6 39.864 ;
    END
  END o2[3]
  PIN o2[40]
    DIRECTION OUTPUT ;
    USE SIGNAL ;
    PORT
      LAYER M4 ;
        RECT  21.408 49.152 21.6 49.176 ;
    END
  END o2[40]
  PIN o2[41]
    DIRECTION OUTPUT ;
    USE SIGNAL ;
    PORT
      LAYER M4 ;
        RECT  21.408 49.392 21.6 49.416 ;
    END
  END o2[41]
  PIN o2[42]
    DIRECTION OUTPUT ;
    USE SIGNAL ;
    PORT
      LAYER M4 ;
        RECT  21.408 49.632 21.6 49.656 ;
    END
  END o2[42]
  PIN o2[43]
    DIRECTION OUTPUT ;
    USE SIGNAL ;
    PORT
      LAYER M4 ;
        RECT  21.408 49.872 21.6 49.896 ;
    END
  END o2[43]
  PIN o2[44]
    DIRECTION OUTPUT ;
    USE SIGNAL ;
    PORT
      LAYER M4 ;
        RECT  21.408 50.16 21.6 50.184 ;
    END
  END o2[44]
  PIN o2[45]
    DIRECTION OUTPUT ;
    USE SIGNAL ;
    PORT
      LAYER M4 ;
        RECT  21.408 50.4 21.6 50.424 ;
    END
  END o2[45]
  PIN o2[46]
    DIRECTION OUTPUT ;
    USE SIGNAL ;
    PORT
      LAYER M4 ;
        RECT  21.408 50.64 21.6 50.664 ;
    END
  END o2[46]
  PIN o2[47]
    DIRECTION OUTPUT ;
    USE SIGNAL ;
    PORT
      LAYER M4 ;
        RECT  21.408 50.88 21.6 50.904 ;
    END
  END o2[47]
  PIN o2[48]
    DIRECTION OUTPUT ;
    USE SIGNAL ;
    PORT
      LAYER M4 ;
        RECT  21.408 51.168 21.6 51.192 ;
    END
  END o2[48]
  PIN o2[49]
    DIRECTION OUTPUT ;
    USE SIGNAL ;
    PORT
      LAYER M4 ;
        RECT  21.408 51.408 21.6 51.432 ;
    END
  END o2[49]
  PIN o2[4]
    DIRECTION OUTPUT ;
    USE SIGNAL ;
    PORT
      LAYER M4 ;
        RECT  21.408 40.08 21.6 40.104 ;
    END
  END o2[4]
  PIN o2[50]
    DIRECTION OUTPUT ;
    USE SIGNAL ;
    PORT
      LAYER M4 ;
        RECT  21.408 51.648 21.6 51.672 ;
    END
  END o2[50]
  PIN o2[51]
    DIRECTION OUTPUT ;
    USE SIGNAL ;
    PORT
      LAYER M4 ;
        RECT  21.408 51.888 21.6 51.912 ;
    END
  END o2[51]
  PIN o2[52]
    DIRECTION OUTPUT ;
    USE SIGNAL ;
    PORT
      LAYER M4 ;
        RECT  21.408 52.176 21.6 52.2 ;
    END
  END o2[52]
  PIN o2[53]
    DIRECTION OUTPUT ;
    USE SIGNAL ;
    PORT
      LAYER M4 ;
        RECT  21.408 52.416 21.6 52.44 ;
    END
  END o2[53]
  PIN o2[54]
    DIRECTION OUTPUT ;
    USE SIGNAL ;
    PORT
      LAYER M4 ;
        RECT  21.408 52.656 21.6 52.68 ;
    END
  END o2[54]
  PIN o2[55]
    DIRECTION OUTPUT ;
    USE SIGNAL ;
    PORT
      LAYER M4 ;
        RECT  21.408 52.896 21.6 52.92 ;
    END
  END o2[55]
  PIN o2[56]
    DIRECTION OUTPUT ;
    USE SIGNAL ;
    PORT
      LAYER M4 ;
        RECT  21.408 53.136 21.6 53.16 ;
    END
  END o2[56]
  PIN o2[57]
    DIRECTION OUTPUT ;
    USE SIGNAL ;
    PORT
      LAYER M4 ;
        RECT  21.408 53.424 21.6 53.448 ;
    END
  END o2[57]
  PIN o2[58]
    DIRECTION OUTPUT ;
    USE SIGNAL ;
    PORT
      LAYER M4 ;
        RECT  21.408 53.664 21.6 53.688 ;
    END
  END o2[58]
  PIN o2[59]
    DIRECTION OUTPUT ;
    USE SIGNAL ;
    PORT
      LAYER M4 ;
        RECT  21.408 53.904 21.6 53.928 ;
    END
  END o2[59]
  PIN o2[5]
    DIRECTION OUTPUT ;
    USE SIGNAL ;
    PORT
      LAYER M4 ;
        RECT  21.408 40.368 21.6 40.392 ;
    END
  END o2[5]
  PIN o2[60]
    DIRECTION OUTPUT ;
    USE SIGNAL ;
    PORT
      LAYER M4 ;
        RECT  21.408 54.144 21.6 54.168 ;
    END
  END o2[60]
  PIN o2[61]
    DIRECTION OUTPUT ;
    USE SIGNAL ;
    PORT
      LAYER M4 ;
        RECT  21.408 54.432 21.6 54.456 ;
    END
  END o2[61]
  PIN o2[62]
    DIRECTION OUTPUT ;
    USE SIGNAL ;
    PORT
      LAYER M4 ;
        RECT  21.408 54.672 21.6 54.696 ;
    END
  END o2[62]
  PIN o2[63]
    DIRECTION OUTPUT ;
    USE SIGNAL ;
    PORT
      LAYER M4 ;
        RECT  21.408 54.912 21.6 54.936 ;
    END
  END o2[63]
  PIN o2[64]
    DIRECTION OUTPUT ;
    USE SIGNAL ;
    PORT
      LAYER M4 ;
        RECT  21.408 55.152 21.6 55.176 ;
    END
  END o2[64]
  PIN o2[65]
    DIRECTION OUTPUT ;
    USE SIGNAL ;
    PORT
      LAYER M4 ;
        RECT  21.408 55.44 21.6 55.464 ;
    END
  END o2[65]
  PIN o2[66]
    DIRECTION OUTPUT ;
    USE SIGNAL ;
    PORT
      LAYER M4 ;
        RECT  21.408 55.68 21.6 55.704 ;
    END
  END o2[66]
  PIN o2[67]
    DIRECTION OUTPUT ;
    USE SIGNAL ;
    PORT
      LAYER M4 ;
        RECT  21.408 55.92 21.6 55.944 ;
    END
  END o2[67]
  PIN o2[68]
    DIRECTION OUTPUT ;
    USE SIGNAL ;
    PORT
      LAYER M4 ;
        RECT  21.408 56.4 21.6 56.424 ;
    END
  END o2[68]
  PIN o2[69]
    DIRECTION OUTPUT ;
    USE SIGNAL ;
    PORT
      LAYER M4 ;
        RECT  21.408 56.688 21.6 56.712 ;
    END
  END o2[69]
  PIN o2[6]
    DIRECTION OUTPUT ;
    USE SIGNAL ;
    PORT
      LAYER M4 ;
        RECT  21.408 40.608 21.6 40.632 ;
    END
  END o2[6]
  PIN o2[70]
    DIRECTION OUTPUT ;
    USE SIGNAL ;
    PORT
      LAYER M4 ;
        RECT  21.408 56.928 21.6 56.952 ;
    END
  END o2[70]
  PIN o2[71]
    DIRECTION OUTPUT ;
    USE SIGNAL ;
    PORT
      LAYER M4 ;
        RECT  21.408 57.168 21.6 57.192 ;
    END
  END o2[71]
  PIN o2[72]
    DIRECTION OUTPUT ;
    USE SIGNAL ;
    PORT
      LAYER M4 ;
        RECT  21.408 57.408 21.6 57.432 ;
    END
  END o2[72]
  PIN o2[73]
    DIRECTION OUTPUT ;
    USE SIGNAL ;
    PORT
      LAYER M4 ;
        RECT  21.408 57.696 21.6 57.72 ;
    END
  END o2[73]
  PIN o2[74]
    DIRECTION OUTPUT ;
    USE SIGNAL ;
    PORT
      LAYER M4 ;
        RECT  21.408 57.936 21.6 57.96 ;
    END
  END o2[74]
  PIN o2[75]
    DIRECTION OUTPUT ;
    USE SIGNAL ;
    PORT
      LAYER M4 ;
        RECT  21.408 58.176 21.6 58.2 ;
    END
  END o2[75]
  PIN o2[76]
    DIRECTION OUTPUT ;
    USE SIGNAL ;
    PORT
      LAYER M4 ;
        RECT  21.408 58.416 21.6 58.44 ;
    END
  END o2[76]
  PIN o2[77]
    DIRECTION OUTPUT ;
    USE SIGNAL ;
    PORT
      LAYER M4 ;
        RECT  21.408 58.704 21.6 58.728 ;
    END
  END o2[77]
  PIN o2[78]
    DIRECTION OUTPUT ;
    USE SIGNAL ;
    PORT
      LAYER M4 ;
        RECT  21.408 58.944 21.6 58.968 ;
    END
  END o2[78]
  PIN o2[79]
    DIRECTION OUTPUT ;
    USE SIGNAL ;
    PORT
      LAYER M4 ;
        RECT  21.408 59.184 21.6 59.208 ;
    END
  END o2[79]
  PIN o2[7]
    DIRECTION OUTPUT ;
    USE SIGNAL ;
    PORT
      LAYER M4 ;
        RECT  21.408 40.848 21.6 40.872 ;
    END
  END o2[7]
  PIN o2[80]
    DIRECTION OUTPUT ;
    USE SIGNAL ;
    PORT
      LAYER M4 ;
        RECT  21.408 59.424 21.6 59.448 ;
    END
  END o2[80]
  PIN o2[81]
    DIRECTION OUTPUT ;
    USE SIGNAL ;
    PORT
      LAYER M4 ;
        RECT  21.408 59.712 21.6 59.736 ;
    END
  END o2[81]
  PIN o2[82]
    DIRECTION OUTPUT ;
    USE SIGNAL ;
    PORT
      LAYER M4 ;
        RECT  21.408 59.952 21.6 59.976 ;
    END
  END o2[82]
  PIN o2[83]
    DIRECTION OUTPUT ;
    USE SIGNAL ;
    PORT
      LAYER M4 ;
        RECT  21.408 60.192 21.6 60.216 ;
    END
  END o2[83]
  PIN o2[84]
    DIRECTION OUTPUT ;
    USE SIGNAL ;
    PORT
      LAYER M4 ;
        RECT  21.408 60.432 21.6 60.456 ;
    END
  END o2[84]
  PIN o2[85]
    DIRECTION OUTPUT ;
    USE SIGNAL ;
    PORT
      LAYER M4 ;
        RECT  21.408 60.672 21.6 60.696 ;
    END
  END o2[85]
  PIN o2[86]
    DIRECTION OUTPUT ;
    USE SIGNAL ;
    PORT
      LAYER M4 ;
        RECT  21.408 60.96 21.6 60.984 ;
    END
  END o2[86]
  PIN o2[87]
    DIRECTION OUTPUT ;
    USE SIGNAL ;
    PORT
      LAYER M4 ;
        RECT  21.408 61.2 21.6 61.224 ;
    END
  END o2[87]
  PIN o2[88]
    DIRECTION OUTPUT ;
    USE SIGNAL ;
    PORT
      LAYER M4 ;
        RECT  21.408 61.44 21.6 61.464 ;
    END
  END o2[88]
  PIN o2[89]
    DIRECTION OUTPUT ;
    USE SIGNAL ;
    PORT
      LAYER M4 ;
        RECT  21.408 61.68 21.6 61.704 ;
    END
  END o2[89]
  PIN o2[8]
    DIRECTION OUTPUT ;
    USE SIGNAL ;
    PORT
      LAYER M4 ;
        RECT  21.408 41.088 21.6 41.112 ;
    END
  END o2[8]
  PIN o2[90]
    DIRECTION OUTPUT ;
    USE SIGNAL ;
    PORT
      LAYER M4 ;
        RECT  21.408 61.968 21.6 61.992 ;
    END
  END o2[90]
  PIN o2[91]
    DIRECTION OUTPUT ;
    USE SIGNAL ;
    PORT
      LAYER M4 ;
        RECT  21.408 62.208 21.6 62.232 ;
    END
  END o2[91]
  PIN o2[92]
    DIRECTION OUTPUT ;
    USE SIGNAL ;
    PORT
      LAYER M4 ;
        RECT  21.408 62.448 21.6 62.472 ;
    END
  END o2[92]
  PIN o2[93]
    DIRECTION OUTPUT ;
    USE SIGNAL ;
    PORT
      LAYER M4 ;
        RECT  21.408 62.688 21.6 62.712 ;
    END
  END o2[93]
  PIN o2[94]
    DIRECTION OUTPUT ;
    USE SIGNAL ;
    PORT
      LAYER M4 ;
        RECT  21.408 62.976 21.6 63 ;
    END
  END o2[94]
  PIN o2[95]
    DIRECTION OUTPUT ;
    USE SIGNAL ;
    PORT
      LAYER M4 ;
        RECT  21.408 63.216 21.6 63.24 ;
    END
  END o2[95]
  PIN o2[96]
    DIRECTION OUTPUT ;
    USE SIGNAL ;
    PORT
      LAYER M4 ;
        RECT  21.408 63.456 21.6 63.48 ;
    END
  END o2[96]
  PIN o2[97]
    DIRECTION OUTPUT ;
    USE SIGNAL ;
    PORT
      LAYER M4 ;
        RECT  21.408 63.696 21.6 63.72 ;
    END
  END o2[97]
  PIN o2[98]
    DIRECTION OUTPUT ;
    USE SIGNAL ;
    PORT
      LAYER M4 ;
        RECT  21.408 63.936 21.6 63.96 ;
    END
  END o2[98]
  PIN o2[99]
    DIRECTION OUTPUT ;
    USE SIGNAL ;
    PORT
      LAYER M4 ;
        RECT  21.408 64.224 21.6 64.248 ;
    END
  END o2[99]
  PIN o2[9]
    DIRECTION OUTPUT ;
    USE SIGNAL ;
    PORT
      LAYER M4 ;
        RECT  21.408 41.376 21.6 41.4 ;
    END
  END o2[9]
  PIN o3[0]
    DIRECTION OUTPUT ;
    USE SIGNAL ;
    PORT
      LAYER M4 ;
        RECT  0 50.592 0.192 50.616 ;
    END
  END o3[0]
  PIN o3[100]
    DIRECTION OUTPUT ;
    USE SIGNAL ;
    PORT
      LAYER M4 ;
        RECT  0 67.44 0.192 67.464 ;
    END
  END o3[100]
  PIN o3[101]
    DIRECTION OUTPUT ;
    USE SIGNAL ;
    PORT
      LAYER M4 ;
        RECT  0 67.584 0.192 67.608 ;
    END
  END o3[101]
  PIN o3[102]
    DIRECTION OUTPUT ;
    USE SIGNAL ;
    PORT
      LAYER M4 ;
        RECT  0 67.776 0.192 67.8 ;
    END
  END o3[102]
  PIN o3[103]
    DIRECTION OUTPUT ;
    USE SIGNAL ;
    PORT
      LAYER M4 ;
        RECT  0 67.92 0.192 67.944 ;
    END
  END o3[103]
  PIN o3[104]
    DIRECTION OUTPUT ;
    USE SIGNAL ;
    PORT
      LAYER M4 ;
        RECT  0 68.112 0.192 68.136 ;
    END
  END o3[104]
  PIN o3[105]
    DIRECTION OUTPUT ;
    USE SIGNAL ;
    PORT
      LAYER M4 ;
        RECT  0 68.256 0.192 68.28 ;
    END
  END o3[105]
  PIN o3[106]
    DIRECTION OUTPUT ;
    USE SIGNAL ;
    PORT
      LAYER M4 ;
        RECT  0 68.448 0.192 68.472 ;
    END
  END o3[106]
  PIN o3[107]
    DIRECTION OUTPUT ;
    USE SIGNAL ;
    PORT
      LAYER M4 ;
        RECT  0 68.592 0.192 68.616 ;
    END
  END o3[107]
  PIN o3[108]
    DIRECTION OUTPUT ;
    USE SIGNAL ;
    PORT
      LAYER M4 ;
        RECT  0 68.736 0.192 68.76 ;
    END
  END o3[108]
  PIN o3[109]
    DIRECTION OUTPUT ;
    USE SIGNAL ;
    PORT
      LAYER M4 ;
        RECT  0 68.928 0.192 68.952 ;
    END
  END o3[109]
  PIN o3[10]
    DIRECTION OUTPUT ;
    USE SIGNAL ;
    PORT
      LAYER M4 ;
        RECT  0 52.272 0.192 52.296 ;
    END
  END o3[10]
  PIN o3[110]
    DIRECTION OUTPUT ;
    USE SIGNAL ;
    PORT
      LAYER M4 ;
        RECT  0 69.072 0.192 69.096 ;
    END
  END o3[110]
  PIN o3[111]
    DIRECTION OUTPUT ;
    USE SIGNAL ;
    PORT
      LAYER M4 ;
        RECT  0 69.264 0.192 69.288 ;
    END
  END o3[111]
  PIN o3[112]
    DIRECTION OUTPUT ;
    USE SIGNAL ;
    PORT
      LAYER M4 ;
        RECT  0 69.408 0.192 69.432 ;
    END
  END o3[112]
  PIN o3[113]
    DIRECTION OUTPUT ;
    USE SIGNAL ;
    PORT
      LAYER M4 ;
        RECT  0 69.6 0.192 69.624 ;
    END
  END o3[113]
  PIN o3[114]
    DIRECTION OUTPUT ;
    USE SIGNAL ;
    PORT
      LAYER M4 ;
        RECT  0 69.744 0.192 69.768 ;
    END
  END o3[114]
  PIN o3[115]
    DIRECTION OUTPUT ;
    USE SIGNAL ;
    PORT
      LAYER M4 ;
        RECT  0 69.936 0.192 69.96 ;
    END
  END o3[115]
  PIN o3[116]
    DIRECTION OUTPUT ;
    USE SIGNAL ;
    PORT
      LAYER M4 ;
        RECT  0 70.08 0.192 70.104 ;
    END
  END o3[116]
  PIN o3[117]
    DIRECTION OUTPUT ;
    USE SIGNAL ;
    PORT
      LAYER M4 ;
        RECT  0 70.272 0.192 70.296 ;
    END
  END o3[117]
  PIN o3[118]
    DIRECTION OUTPUT ;
    USE SIGNAL ;
    PORT
      LAYER M4 ;
        RECT  0 70.416 0.192 70.44 ;
    END
  END o3[118]
  PIN o3[119]
    DIRECTION OUTPUT ;
    USE SIGNAL ;
    PORT
      LAYER M4 ;
        RECT  0 70.608 0.192 70.632 ;
    END
  END o3[119]
  PIN o3[11]
    DIRECTION OUTPUT ;
    USE SIGNAL ;
    PORT
      LAYER M4 ;
        RECT  0 52.464 0.192 52.488 ;
    END
  END o3[11]
  PIN o3[120]
    DIRECTION OUTPUT ;
    USE SIGNAL ;
    PORT
      LAYER M4 ;
        RECT  0 70.752 0.192 70.776 ;
    END
  END o3[120]
  PIN o3[121]
    DIRECTION OUTPUT ;
    USE SIGNAL ;
    PORT
      LAYER M4 ;
        RECT  0 70.944 0.192 70.968 ;
    END
  END o3[121]
  PIN o3[122]
    DIRECTION OUTPUT ;
    USE SIGNAL ;
    PORT
      LAYER M4 ;
        RECT  0 71.088 0.192 71.112 ;
    END
  END o3[122]
  PIN o3[123]
    DIRECTION OUTPUT ;
    USE SIGNAL ;
    PORT
      LAYER M4 ;
        RECT  0 71.232 0.192 71.256 ;
    END
  END o3[123]
  PIN o3[124]
    DIRECTION OUTPUT ;
    USE SIGNAL ;
    PORT
      LAYER M4 ;
        RECT  0 71.424 0.192 71.448 ;
    END
  END o3[124]
  PIN o3[125]
    DIRECTION OUTPUT ;
    USE SIGNAL ;
    PORT
      LAYER M4 ;
        RECT  0 71.568 0.192 71.592 ;
    END
  END o3[125]
  PIN o3[126]
    DIRECTION OUTPUT ;
    USE SIGNAL ;
    PORT
      LAYER M4 ;
        RECT  0 71.76 0.192 71.784 ;
    END
  END o3[126]
  PIN o3[127]
    DIRECTION OUTPUT ;
    USE SIGNAL ;
    PORT
      LAYER M4 ;
        RECT  0 71.904 0.192 71.928 ;
    END
  END o3[127]
  PIN o3[128]
    DIRECTION OUTPUT ;
    USE SIGNAL ;
    PORT
      LAYER M4 ;
        RECT  0 72.096 0.192 72.12 ;
    END
  END o3[128]
  PIN o3[129]
    DIRECTION OUTPUT ;
    USE SIGNAL ;
    PORT
      LAYER M4 ;
        RECT  0 72.24 0.192 72.264 ;
    END
  END o3[129]
  PIN o3[12]
    DIRECTION OUTPUT ;
    USE SIGNAL ;
    PORT
      LAYER M4 ;
        RECT  0 52.608 0.192 52.632 ;
    END
  END o3[12]
  PIN o3[130]
    DIRECTION OUTPUT ;
    USE SIGNAL ;
    PORT
      LAYER M4 ;
        RECT  0 72.432 0.192 72.456 ;
    END
  END o3[130]
  PIN o3[131]
    DIRECTION OUTPUT ;
    USE SIGNAL ;
    PORT
      LAYER M4 ;
        RECT  0 72.576 0.192 72.6 ;
    END
  END o3[131]
  PIN o3[132]
    DIRECTION OUTPUT ;
    USE SIGNAL ;
    PORT
      LAYER M4 ;
        RECT  0 72.768 0.192 72.792 ;
    END
  END o3[132]
  PIN o3[133]
    DIRECTION OUTPUT ;
    USE SIGNAL ;
    PORT
      LAYER M4 ;
        RECT  0 72.912 0.192 72.936 ;
    END
  END o3[133]
  PIN o3[134]
    DIRECTION OUTPUT ;
    USE SIGNAL ;
    PORT
      LAYER M4 ;
        RECT  0 73.104 0.192 73.128 ;
    END
  END o3[134]
  PIN o3[135]
    DIRECTION OUTPUT ;
    USE SIGNAL ;
    PORT
      LAYER M4 ;
        RECT  0 73.248 0.192 73.272 ;
    END
  END o3[135]
  PIN o3[13]
    DIRECTION OUTPUT ;
    USE SIGNAL ;
    PORT
      LAYER M4 ;
        RECT  0 52.8 0.192 52.824 ;
    END
  END o3[13]
  PIN o3[14]
    DIRECTION OUTPUT ;
    USE SIGNAL ;
    PORT
      LAYER M4 ;
        RECT  0 52.944 0.192 52.968 ;
    END
  END o3[14]
  PIN o3[15]
    DIRECTION OUTPUT ;
    USE SIGNAL ;
    PORT
      LAYER M4 ;
        RECT  0 53.088 0.192 53.112 ;
    END
  END o3[15]
  PIN o3[16]
    DIRECTION OUTPUT ;
    USE SIGNAL ;
    PORT
      LAYER M4 ;
        RECT  0 53.28 0.192 53.304 ;
    END
  END o3[16]
  PIN o3[17]
    DIRECTION OUTPUT ;
    USE SIGNAL ;
    PORT
      LAYER M4 ;
        RECT  0 53.424 0.192 53.448 ;
    END
  END o3[17]
  PIN o3[18]
    DIRECTION OUTPUT ;
    USE SIGNAL ;
    PORT
      LAYER M4 ;
        RECT  0 53.616 0.192 53.64 ;
    END
  END o3[18]
  PIN o3[19]
    DIRECTION OUTPUT ;
    USE SIGNAL ;
    PORT
      LAYER M4 ;
        RECT  0 53.76 0.192 53.784 ;
    END
  END o3[19]
  PIN o3[1]
    DIRECTION OUTPUT ;
    USE SIGNAL ;
    PORT
      LAYER M4 ;
        RECT  0 50.784 0.192 50.808 ;
    END
  END o3[1]
  PIN o3[20]
    DIRECTION OUTPUT ;
    USE SIGNAL ;
    PORT
      LAYER M4 ;
        RECT  0 53.952 0.192 53.976 ;
    END
  END o3[20]
  PIN o3[21]
    DIRECTION OUTPUT ;
    USE SIGNAL ;
    PORT
      LAYER M4 ;
        RECT  0 54.096 0.192 54.12 ;
    END
  END o3[21]
  PIN o3[22]
    DIRECTION OUTPUT ;
    USE SIGNAL ;
    PORT
      LAYER M4 ;
        RECT  0 54.288 0.192 54.312 ;
    END
  END o3[22]
  PIN o3[23]
    DIRECTION OUTPUT ;
    USE SIGNAL ;
    PORT
      LAYER M4 ;
        RECT  0 54.432 0.192 54.456 ;
    END
  END o3[23]
  PIN o3[24]
    DIRECTION OUTPUT ;
    USE SIGNAL ;
    PORT
      LAYER M4 ;
        RECT  0 54.624 0.192 54.648 ;
    END
  END o3[24]
  PIN o3[25]
    DIRECTION OUTPUT ;
    USE SIGNAL ;
    PORT
      LAYER M4 ;
        RECT  0 54.768 0.192 54.792 ;
    END
  END o3[25]
  PIN o3[26]
    DIRECTION OUTPUT ;
    USE SIGNAL ;
    PORT
      LAYER M4 ;
        RECT  0 54.96 0.192 54.984 ;
    END
  END o3[26]
  PIN o3[27]
    DIRECTION OUTPUT ;
    USE SIGNAL ;
    PORT
      LAYER M4 ;
        RECT  0 55.104 0.192 55.128 ;
    END
  END o3[27]
  PIN o3[28]
    DIRECTION OUTPUT ;
    USE SIGNAL ;
    PORT
      LAYER M4 ;
        RECT  0 55.296 0.192 55.32 ;
    END
  END o3[28]
  PIN o3[29]
    DIRECTION OUTPUT ;
    USE SIGNAL ;
    PORT
      LAYER M4 ;
        RECT  0 55.44 0.192 55.464 ;
    END
  END o3[29]
  PIN o3[2]
    DIRECTION OUTPUT ;
    USE SIGNAL ;
    PORT
      LAYER M4 ;
        RECT  0 50.928 0.192 50.952 ;
    END
  END o3[2]
  PIN o3[30]
    DIRECTION OUTPUT ;
    USE SIGNAL ;
    PORT
      LAYER M4 ;
        RECT  0 55.584 0.192 55.608 ;
    END
  END o3[30]
  PIN o3[31]
    DIRECTION OUTPUT ;
    USE SIGNAL ;
    PORT
      LAYER M4 ;
        RECT  0 55.776 0.192 55.8 ;
    END
  END o3[31]
  PIN o3[32]
    DIRECTION OUTPUT ;
    USE SIGNAL ;
    PORT
      LAYER M4 ;
        RECT  0 55.92 0.192 55.944 ;
    END
  END o3[32]
  PIN o3[33]
    DIRECTION OUTPUT ;
    USE SIGNAL ;
    PORT
      LAYER M4 ;
        RECT  0 56.112 0.192 56.136 ;
    END
  END o3[33]
  PIN o3[34]
    DIRECTION OUTPUT ;
    USE SIGNAL ;
    PORT
      LAYER M4 ;
        RECT  0 56.256 0.192 56.28 ;
    END
  END o3[34]
  PIN o3[35]
    DIRECTION OUTPUT ;
    USE SIGNAL ;
    PORT
      LAYER M4 ;
        RECT  0 56.448 0.192 56.472 ;
    END
  END o3[35]
  PIN o3[36]
    DIRECTION OUTPUT ;
    USE SIGNAL ;
    PORT
      LAYER M4 ;
        RECT  0 56.592 0.192 56.616 ;
    END
  END o3[36]
  PIN o3[37]
    DIRECTION OUTPUT ;
    USE SIGNAL ;
    PORT
      LAYER M4 ;
        RECT  0 56.784 0.192 56.808 ;
    END
  END o3[37]
  PIN o3[38]
    DIRECTION OUTPUT ;
    USE SIGNAL ;
    PORT
      LAYER M4 ;
        RECT  0 56.928 0.192 56.952 ;
    END
  END o3[38]
  PIN o3[39]
    DIRECTION OUTPUT ;
    USE SIGNAL ;
    PORT
      LAYER M4 ;
        RECT  0 57.12 0.192 57.144 ;
    END
  END o3[39]
  PIN o3[3]
    DIRECTION OUTPUT ;
    USE SIGNAL ;
    PORT
      LAYER M4 ;
        RECT  0 51.12 0.192 51.144 ;
    END
  END o3[3]
  PIN o3[40]
    DIRECTION OUTPUT ;
    USE SIGNAL ;
    PORT
      LAYER M4 ;
        RECT  0 57.264 0.192 57.288 ;
    END
  END o3[40]
  PIN o3[41]
    DIRECTION OUTPUT ;
    USE SIGNAL ;
    PORT
      LAYER M4 ;
        RECT  0 57.456 0.192 57.48 ;
    END
  END o3[41]
  PIN o3[42]
    DIRECTION OUTPUT ;
    USE SIGNAL ;
    PORT
      LAYER M4 ;
        RECT  0 57.6 0.192 57.624 ;
    END
  END o3[42]
  PIN o3[43]
    DIRECTION OUTPUT ;
    USE SIGNAL ;
    PORT
      LAYER M4 ;
        RECT  0 57.792 0.192 57.816 ;
    END
  END o3[43]
  PIN o3[44]
    DIRECTION OUTPUT ;
    USE SIGNAL ;
    PORT
      LAYER M4 ;
        RECT  0 57.936 0.192 57.96 ;
    END
  END o3[44]
  PIN o3[45]
    DIRECTION OUTPUT ;
    USE SIGNAL ;
    PORT
      LAYER M4 ;
        RECT  0 58.08 0.192 58.104 ;
    END
  END o3[45]
  PIN o3[46]
    DIRECTION OUTPUT ;
    USE SIGNAL ;
    PORT
      LAYER M4 ;
        RECT  0 58.272 0.192 58.296 ;
    END
  END o3[46]
  PIN o3[47]
    DIRECTION OUTPUT ;
    USE SIGNAL ;
    PORT
      LAYER M4 ;
        RECT  0 58.416 0.192 58.44 ;
    END
  END o3[47]
  PIN o3[48]
    DIRECTION OUTPUT ;
    USE SIGNAL ;
    PORT
      LAYER M4 ;
        RECT  0 58.608 0.192 58.632 ;
    END
  END o3[48]
  PIN o3[49]
    DIRECTION OUTPUT ;
    USE SIGNAL ;
    PORT
      LAYER M4 ;
        RECT  0 58.752 0.192 58.776 ;
    END
  END o3[49]
  PIN o3[4]
    DIRECTION OUTPUT ;
    USE SIGNAL ;
    PORT
      LAYER M4 ;
        RECT  0 51.264 0.192 51.288 ;
    END
  END o3[4]
  PIN o3[50]
    DIRECTION OUTPUT ;
    USE SIGNAL ;
    PORT
      LAYER M4 ;
        RECT  0 58.944 0.192 58.968 ;
    END
  END o3[50]
  PIN o3[51]
    DIRECTION OUTPUT ;
    USE SIGNAL ;
    PORT
      LAYER M4 ;
        RECT  0 59.088 0.192 59.112 ;
    END
  END o3[51]
  PIN o3[52]
    DIRECTION OUTPUT ;
    USE SIGNAL ;
    PORT
      LAYER M4 ;
        RECT  0 59.28 0.192 59.304 ;
    END
  END o3[52]
  PIN o3[53]
    DIRECTION OUTPUT ;
    USE SIGNAL ;
    PORT
      LAYER M4 ;
        RECT  0 59.424 0.192 59.448 ;
    END
  END o3[53]
  PIN o3[54]
    DIRECTION OUTPUT ;
    USE SIGNAL ;
    PORT
      LAYER M4 ;
        RECT  0 59.616 0.192 59.64 ;
    END
  END o3[54]
  PIN o3[55]
    DIRECTION OUTPUT ;
    USE SIGNAL ;
    PORT
      LAYER M4 ;
        RECT  0 59.76 0.192 59.784 ;
    END
  END o3[55]
  PIN o3[56]
    DIRECTION OUTPUT ;
    USE SIGNAL ;
    PORT
      LAYER M4 ;
        RECT  0 59.952 0.192 59.976 ;
    END
  END o3[56]
  PIN o3[57]
    DIRECTION OUTPUT ;
    USE SIGNAL ;
    PORT
      LAYER M4 ;
        RECT  0 60.096 0.192 60.12 ;
    END
  END o3[57]
  PIN o3[58]
    DIRECTION OUTPUT ;
    USE SIGNAL ;
    PORT
      LAYER M4 ;
        RECT  0 60.288 0.192 60.312 ;
    END
  END o3[58]
  PIN o3[59]
    DIRECTION OUTPUT ;
    USE SIGNAL ;
    PORT
      LAYER M4 ;
        RECT  0 60.432 0.192 60.456 ;
    END
  END o3[59]
  PIN o3[5]
    DIRECTION OUTPUT ;
    USE SIGNAL ;
    PORT
      LAYER M4 ;
        RECT  0 51.456 0.192 51.48 ;
    END
  END o3[5]
  PIN o3[60]
    DIRECTION OUTPUT ;
    USE SIGNAL ;
    PORT
      LAYER M4 ;
        RECT  0 60.624 0.192 60.648 ;
    END
  END o3[60]
  PIN o3[61]
    DIRECTION OUTPUT ;
    USE SIGNAL ;
    PORT
      LAYER M4 ;
        RECT  0 60.768 0.192 60.792 ;
    END
  END o3[61]
  PIN o3[62]
    DIRECTION OUTPUT ;
    USE SIGNAL ;
    PORT
      LAYER M4 ;
        RECT  0 60.912 0.192 60.936 ;
    END
  END o3[62]
  PIN o3[63]
    DIRECTION OUTPUT ;
    USE SIGNAL ;
    PORT
      LAYER M4 ;
        RECT  0 61.104 0.192 61.128 ;
    END
  END o3[63]
  PIN o3[64]
    DIRECTION OUTPUT ;
    USE SIGNAL ;
    PORT
      LAYER M4 ;
        RECT  0 61.248 0.192 61.272 ;
    END
  END o3[64]
  PIN o3[65]
    DIRECTION OUTPUT ;
    USE SIGNAL ;
    PORT
      LAYER M4 ;
        RECT  0 61.44 0.192 61.464 ;
    END
  END o3[65]
  PIN o3[66]
    DIRECTION OUTPUT ;
    USE SIGNAL ;
    PORT
      LAYER M4 ;
        RECT  0 61.584 0.192 61.608 ;
    END
  END o3[66]
  PIN o3[67]
    DIRECTION OUTPUT ;
    USE SIGNAL ;
    PORT
      LAYER M4 ;
        RECT  0 61.776 0.192 61.8 ;
    END
  END o3[67]
  PIN o3[68]
    DIRECTION OUTPUT ;
    USE SIGNAL ;
    PORT
      LAYER M4 ;
        RECT  0 62.112 0.192 62.136 ;
    END
  END o3[68]
  PIN o3[69]
    DIRECTION OUTPUT ;
    USE SIGNAL ;
    PORT
      LAYER M4 ;
        RECT  0 62.256 0.192 62.28 ;
    END
  END o3[69]
  PIN o3[6]
    DIRECTION OUTPUT ;
    USE SIGNAL ;
    PORT
      LAYER M4 ;
        RECT  0 51.6 0.192 51.624 ;
    END
  END o3[6]
  PIN o3[70]
    DIRECTION OUTPUT ;
    USE SIGNAL ;
    PORT
      LAYER M4 ;
        RECT  0 62.448 0.192 62.472 ;
    END
  END o3[70]
  PIN o3[71]
    DIRECTION OUTPUT ;
    USE SIGNAL ;
    PORT
      LAYER M4 ;
        RECT  0 62.592 0.192 62.616 ;
    END
  END o3[71]
  PIN o3[72]
    DIRECTION OUTPUT ;
    USE SIGNAL ;
    PORT
      LAYER M4 ;
        RECT  0 62.784 0.192 62.808 ;
    END
  END o3[72]
  PIN o3[73]
    DIRECTION OUTPUT ;
    USE SIGNAL ;
    PORT
      LAYER M4 ;
        RECT  0 62.928 0.192 62.952 ;
    END
  END o3[73]
  PIN o3[74]
    DIRECTION OUTPUT ;
    USE SIGNAL ;
    PORT
      LAYER M4 ;
        RECT  0 63.12 0.192 63.144 ;
    END
  END o3[74]
  PIN o3[75]
    DIRECTION OUTPUT ;
    USE SIGNAL ;
    PORT
      LAYER M4 ;
        RECT  0 63.264 0.192 63.288 ;
    END
  END o3[75]
  PIN o3[76]
    DIRECTION OUTPUT ;
    USE SIGNAL ;
    PORT
      LAYER M4 ;
        RECT  0 63.408 0.192 63.432 ;
    END
  END o3[76]
  PIN o3[77]
    DIRECTION OUTPUT ;
    USE SIGNAL ;
    PORT
      LAYER M4 ;
        RECT  0 63.6 0.192 63.624 ;
    END
  END o3[77]
  PIN o3[78]
    DIRECTION OUTPUT ;
    USE SIGNAL ;
    PORT
      LAYER M4 ;
        RECT  0 63.744 0.192 63.768 ;
    END
  END o3[78]
  PIN o3[79]
    DIRECTION OUTPUT ;
    USE SIGNAL ;
    PORT
      LAYER M4 ;
        RECT  0 63.936 0.192 63.96 ;
    END
  END o3[79]
  PIN o3[7]
    DIRECTION OUTPUT ;
    USE SIGNAL ;
    PORT
      LAYER M4 ;
        RECT  0 51.792 0.192 51.816 ;
    END
  END o3[7]
  PIN o3[80]
    DIRECTION OUTPUT ;
    USE SIGNAL ;
    PORT
      LAYER M4 ;
        RECT  0 64.08 0.192 64.104 ;
    END
  END o3[80]
  PIN o3[81]
    DIRECTION OUTPUT ;
    USE SIGNAL ;
    PORT
      LAYER M4 ;
        RECT  0 64.272 0.192 64.296 ;
    END
  END o3[81]
  PIN o3[82]
    DIRECTION OUTPUT ;
    USE SIGNAL ;
    PORT
      LAYER M4 ;
        RECT  0 64.416 0.192 64.44 ;
    END
  END o3[82]
  PIN o3[83]
    DIRECTION OUTPUT ;
    USE SIGNAL ;
    PORT
      LAYER M4 ;
        RECT  0 64.608 0.192 64.632 ;
    END
  END o3[83]
  PIN o3[84]
    DIRECTION OUTPUT ;
    USE SIGNAL ;
    PORT
      LAYER M4 ;
        RECT  0 64.752 0.192 64.776 ;
    END
  END o3[84]
  PIN o3[85]
    DIRECTION OUTPUT ;
    USE SIGNAL ;
    PORT
      LAYER M4 ;
        RECT  0 64.944 0.192 64.968 ;
    END
  END o3[85]
  PIN o3[86]
    DIRECTION OUTPUT ;
    USE SIGNAL ;
    PORT
      LAYER M4 ;
        RECT  0 65.088 0.192 65.112 ;
    END
  END o3[86]
  PIN o3[87]
    DIRECTION OUTPUT ;
    USE SIGNAL ;
    PORT
      LAYER M4 ;
        RECT  0 65.28 0.192 65.304 ;
    END
  END o3[87]
  PIN o3[88]
    DIRECTION OUTPUT ;
    USE SIGNAL ;
    PORT
      LAYER M4 ;
        RECT  0 65.424 0.192 65.448 ;
    END
  END o3[88]
  PIN o3[89]
    DIRECTION OUTPUT ;
    USE SIGNAL ;
    PORT
      LAYER M4 ;
        RECT  0 65.616 0.192 65.64 ;
    END
  END o3[89]
  PIN o3[8]
    DIRECTION OUTPUT ;
    USE SIGNAL ;
    PORT
      LAYER M4 ;
        RECT  0 51.936 0.192 51.96 ;
    END
  END o3[8]
  PIN o3[90]
    DIRECTION OUTPUT ;
    USE SIGNAL ;
    PORT
      LAYER M4 ;
        RECT  0 65.76 0.192 65.784 ;
    END
  END o3[90]
  PIN o3[91]
    DIRECTION OUTPUT ;
    USE SIGNAL ;
    PORT
      LAYER M4 ;
        RECT  0 65.904 0.192 65.928 ;
    END
  END o3[91]
  PIN o3[92]
    DIRECTION OUTPUT ;
    USE SIGNAL ;
    PORT
      LAYER M4 ;
        RECT  0 66.096 0.192 66.12 ;
    END
  END o3[92]
  PIN o3[93]
    DIRECTION OUTPUT ;
    USE SIGNAL ;
    PORT
      LAYER M4 ;
        RECT  0 66.24 0.192 66.264 ;
    END
  END o3[93]
  PIN o3[94]
    DIRECTION OUTPUT ;
    USE SIGNAL ;
    PORT
      LAYER M4 ;
        RECT  0 66.432 0.192 66.456 ;
    END
  END o3[94]
  PIN o3[95]
    DIRECTION OUTPUT ;
    USE SIGNAL ;
    PORT
      LAYER M4 ;
        RECT  0 66.576 0.192 66.6 ;
    END
  END o3[95]
  PIN o3[96]
    DIRECTION OUTPUT ;
    USE SIGNAL ;
    PORT
      LAYER M4 ;
        RECT  0 66.768 0.192 66.792 ;
    END
  END o3[96]
  PIN o3[97]
    DIRECTION OUTPUT ;
    USE SIGNAL ;
    PORT
      LAYER M4 ;
        RECT  0 66.912 0.192 66.936 ;
    END
  END o3[97]
  PIN o3[98]
    DIRECTION OUTPUT ;
    USE SIGNAL ;
    PORT
      LAYER M4 ;
        RECT  0 67.104 0.192 67.128 ;
    END
  END o3[98]
  PIN o3[99]
    DIRECTION OUTPUT ;
    USE SIGNAL ;
    PORT
      LAYER M4 ;
        RECT  0 67.248 0.192 67.272 ;
    END
  END o3[99]
  PIN o3[9]
    DIRECTION OUTPUT ;
    USE SIGNAL ;
    PORT
      LAYER M4 ;
        RECT  0 52.128 0.192 52.152 ;
    END
  END o3[9]
  PIN rs
    DIRECTION INPUT ;
    USE SIGNAL ;
    PORT
      LAYER M5 ;
        RECT  10.8 0 10.824 0.192 ;
    END
  END rs
  PIN VDD
    DIRECTION INOUT ;
    USE POWER ;
    PORT
      LAYER M5 ;
        RECT  18.792 2.151 18.912 75.609 ;
        RECT  16.092 2.151 16.212 75.609 ;
        RECT  13.392 2.151 13.512 75.609 ;
        RECT  10.692 2.151 10.812 75.609 ;
        RECT  7.992 2.151 8.112 75.609 ;
        RECT  5.292 2.151 5.412 75.609 ;
        RECT  2.592 2.151 2.712 75.609 ;
    END
  END VDD
  PIN VSS
    DIRECTION INOUT ;
    USE GROUND ;
    PORT
      LAYER M5 ;
        RECT  18.6 2.137 18.72 75.623 ;
        RECT  15.9 2.137 16.02 75.623 ;
        RECT  13.2 2.137 13.32 75.623 ;
        RECT  10.5 2.137 10.62 75.623 ;
        RECT  7.8 2.137 7.92 75.623 ;
        RECT  5.1 2.137 5.22 75.623 ;
        RECT  2.4 2.137 2.52 75.623 ;
    END
  END VSS
  OBS
    LAYER RVTN ;
     RECT  2.16 2.16 19.44 2.295 ;
     RECT  2.16 2.565 19.44 2.835 ;
     RECT  2.16 3.105 19.44 3.375 ;
     RECT  2.16 3.645 19.44 3.915 ;
     RECT  2.16 4.185 19.44 4.455 ;
     RECT  2.16 4.725 19.44 4.995 ;
     RECT  2.16 5.265 19.44 5.535 ;
     RECT  2.16 5.805 19.44 6.075 ;
     RECT  2.16 6.345 19.44 6.615 ;
     RECT  2.16 6.885 19.44 7.155 ;
     RECT  2.16 7.425 19.44 7.695 ;
     RECT  2.16 7.965 19.44 8.235 ;
     RECT  2.16 8.505 19.44 8.775 ;
     RECT  2.16 9.045 19.44 9.315 ;
     RECT  2.16 9.585 19.44 9.855 ;
     RECT  2.16 10.125 19.44 10.395 ;
     RECT  2.16 10.665 19.44 10.935 ;
     RECT  2.16 11.205 19.44 11.475 ;
     RECT  2.16 11.745 19.44 12.015 ;
     RECT  2.16 12.285 19.44 12.555 ;
     RECT  2.16 12.825 19.44 13.095 ;
     RECT  2.16 13.365 19.44 13.635 ;
     RECT  2.16 13.905 19.44 14.175 ;
     RECT  2.16 14.445 19.44 14.715 ;
     RECT  2.16 14.985 19.44 15.255 ;
     RECT  2.16 15.525 19.44 15.795 ;
     RECT  2.16 16.065 19.44 16.335 ;
     RECT  2.16 16.605 19.44 16.875 ;
     RECT  2.16 17.145 19.44 17.415 ;
     RECT  2.16 17.685 19.44 17.955 ;
     RECT  2.16 18.225 19.44 18.495 ;
     RECT  2.16 18.765 19.44 19.035 ;
     RECT  2.16 19.305 19.44 19.575 ;
     RECT  2.16 19.845 19.44 20.115 ;
     RECT  2.16 20.385 19.44 20.655 ;
     RECT  2.16 20.925 19.44 21.195 ;
     RECT  2.16 21.465 19.44 21.735 ;
     RECT  2.16 22.005 19.44 22.275 ;
     RECT  2.16 22.545 19.44 22.815 ;
     RECT  2.16 23.085 19.44 23.355 ;
     RECT  2.16 23.625 19.44 23.895 ;
     RECT  2.16 24.165 19.44 24.435 ;
     RECT  2.16 24.705 19.44 24.975 ;
     RECT  2.16 25.245 19.44 25.515 ;
     RECT  2.16 25.785 19.44 26.055 ;
     RECT  2.16 26.325 19.44 26.595 ;
     RECT  2.16 26.865 19.44 27.135 ;
     RECT  2.16 27.405 19.44 27.675 ;
     RECT  2.16 27.945 19.44 28.215 ;
     RECT  2.16 28.485 19.44 28.755 ;
     RECT  2.16 29.025 19.44 29.295 ;
     RECT  2.16 29.565 19.44 29.835 ;
     RECT  2.16 30.105 19.44 30.375 ;
     RECT  2.16 30.645 19.44 30.915 ;
     RECT  2.16 31.185 19.44 31.455 ;
     RECT  2.16 31.725 19.44 31.995 ;
     RECT  2.16 32.265 19.44 32.535 ;
     RECT  2.16 32.805 19.44 33.075 ;
     RECT  2.16 33.345 19.44 33.615 ;
     RECT  2.16 33.885 19.44 34.155 ;
     RECT  2.16 34.425 19.44 34.695 ;
     RECT  2.16 34.965 19.44 35.235 ;
     RECT  2.16 35.505 19.44 35.775 ;
     RECT  2.16 36.045 19.44 36.315 ;
     RECT  2.16 36.585 19.44 36.855 ;
     RECT  2.16 37.125 19.44 37.395 ;
     RECT  2.16 37.665 19.44 37.935 ;
     RECT  2.16 38.205 19.44 38.475 ;
     RECT  2.16 38.745 19.44 39.015 ;
     RECT  2.16 39.285 19.44 39.555 ;
     RECT  2.16 39.825 19.44 40.095 ;
     RECT  2.16 40.365 19.44 40.635 ;
     RECT  2.16 40.905 19.44 41.175 ;
     RECT  2.16 41.445 19.44 41.715 ;
     RECT  2.16 41.985 19.44 42.255 ;
     RECT  2.16 42.525 19.44 42.795 ;
     RECT  2.16 43.065 19.44 43.335 ;
     RECT  2.16 43.605 19.44 43.875 ;
     RECT  2.16 44.145 19.44 44.415 ;
     RECT  2.16 44.685 19.44 44.955 ;
     RECT  2.16 45.225 19.44 45.495 ;
     RECT  2.16 45.765 19.44 46.035 ;
     RECT  2.16 46.305 19.44 46.575 ;
     RECT  2.16 46.845 19.44 47.115 ;
     RECT  2.16 47.385 19.44 47.655 ;
     RECT  2.16 47.925 19.44 48.195 ;
     RECT  2.16 48.465 19.44 48.735 ;
     RECT  2.16 49.005 19.44 49.275 ;
     RECT  2.16 49.545 19.44 49.815 ;
     RECT  2.16 50.085 19.44 50.355 ;
     RECT  2.16 50.625 19.44 50.895 ;
     RECT  2.16 51.165 19.44 51.435 ;
     RECT  2.16 51.705 19.44 51.975 ;
     RECT  2.16 52.245 19.44 52.515 ;
     RECT  2.16 52.785 19.44 53.055 ;
     RECT  2.16 53.325 19.44 53.595 ;
     RECT  2.16 53.865 19.44 54.135 ;
     RECT  2.16 54.405 19.44 54.675 ;
     RECT  2.16 54.945 19.44 55.215 ;
     RECT  2.16 55.485 19.44 55.755 ;
     RECT  2.16 56.025 19.44 56.295 ;
     RECT  2.16 56.565 19.44 56.835 ;
     RECT  2.16 57.105 19.44 57.375 ;
     RECT  2.16 57.645 19.44 57.915 ;
     RECT  2.16 58.185 19.44 58.455 ;
     RECT  2.16 58.725 19.44 58.995 ;
     RECT  2.16 59.265 19.44 59.535 ;
     RECT  2.16 59.805 19.44 60.075 ;
     RECT  2.16 60.345 19.44 60.615 ;
     RECT  2.16 60.885 19.44 61.155 ;
     RECT  2.16 61.425 19.44 61.695 ;
     RECT  2.16 61.965 19.44 62.235 ;
     RECT  2.16 62.505 19.44 62.775 ;
     RECT  2.16 63.045 19.44 63.315 ;
     RECT  2.16 63.585 19.44 63.855 ;
     RECT  2.16 64.125 19.44 64.395 ;
     RECT  2.16 64.665 19.44 64.935 ;
     RECT  2.16 65.205 19.44 65.475 ;
     RECT  2.16 65.745 19.44 66.015 ;
     RECT  2.16 66.285 19.44 66.555 ;
     RECT  2.16 66.825 19.44 67.095 ;
     RECT  2.16 67.365 19.44 67.635 ;
     RECT  2.16 67.905 19.44 68.175 ;
     RECT  2.16 68.445 19.44 68.715 ;
     RECT  2.16 68.985 19.44 69.255 ;
     RECT  2.16 69.525 19.44 69.795 ;
     RECT  2.16 70.065 19.44 70.335 ;
     RECT  2.16 70.605 19.44 70.875 ;
     RECT  2.16 71.145 19.44 71.415 ;
     RECT  2.16 71.685 19.44 71.955 ;
     RECT  2.16 72.225 19.44 72.495 ;
     RECT  2.16 72.765 19.44 73.035 ;
     RECT  2.16 73.305 19.44 73.575 ;
     RECT  2.16 73.845 19.44 74.115 ;
     RECT  2.16 74.385 19.44 74.655 ;
     RECT  2.16 74.925 19.44 75.195 ;
     RECT  2.16 75.465 19.44 75.6 ;
    LAYER RVTP ;
     RECT  2.16 2.295 19.44 2.565 ;
     RECT  2.16 2.835 19.44 3.105 ;
     RECT  2.16 3.375 19.44 3.645 ;
     RECT  2.16 3.915 19.44 4.185 ;
     RECT  2.16 4.455 19.44 4.725 ;
     RECT  2.16 4.995 19.44 5.265 ;
     RECT  2.16 5.535 19.44 5.805 ;
     RECT  2.16 6.075 19.44 6.345 ;
     RECT  2.16 6.615 19.44 6.885 ;
     RECT  2.16 7.155 19.44 7.425 ;
     RECT  2.16 7.695 19.44 7.965 ;
     RECT  2.16 8.235 19.44 8.505 ;
     RECT  2.16 8.775 19.44 9.045 ;
     RECT  2.16 9.315 19.44 9.585 ;
     RECT  2.16 9.855 19.44 10.125 ;
     RECT  2.16 10.395 19.44 10.665 ;
     RECT  2.16 10.935 19.44 11.205 ;
     RECT  2.16 11.475 19.44 11.745 ;
     RECT  2.16 12.015 19.44 12.285 ;
     RECT  2.16 12.555 19.44 12.825 ;
     RECT  2.16 13.095 19.44 13.365 ;
     RECT  2.16 13.635 19.44 13.905 ;
     RECT  2.16 14.175 19.44 14.445 ;
     RECT  2.16 14.715 19.44 14.985 ;
     RECT  2.16 15.255 19.44 15.525 ;
     RECT  2.16 15.795 19.44 16.065 ;
     RECT  2.16 16.335 19.44 16.605 ;
     RECT  2.16 16.875 19.44 17.145 ;
     RECT  2.16 17.415 19.44 17.685 ;
     RECT  2.16 17.955 19.44 18.225 ;
     RECT  2.16 18.495 19.44 18.765 ;
     RECT  2.16 19.035 19.44 19.305 ;
     RECT  2.16 19.575 19.44 19.845 ;
     RECT  2.16 20.115 19.44 20.385 ;
     RECT  2.16 20.655 19.44 20.925 ;
     RECT  2.16 21.195 19.44 21.465 ;
     RECT  2.16 21.735 19.44 22.005 ;
     RECT  2.16 22.275 19.44 22.545 ;
     RECT  2.16 22.815 19.44 23.085 ;
     RECT  2.16 23.355 19.44 23.625 ;
     RECT  2.16 23.895 19.44 24.165 ;
     RECT  2.16 24.435 19.44 24.705 ;
     RECT  2.16 24.975 19.44 25.245 ;
     RECT  2.16 25.515 19.44 25.785 ;
     RECT  2.16 26.055 19.44 26.325 ;
     RECT  2.16 26.595 19.44 26.865 ;
     RECT  2.16 27.135 19.44 27.405 ;
     RECT  2.16 27.675 19.44 27.945 ;
     RECT  2.16 28.215 19.44 28.485 ;
     RECT  2.16 28.755 19.44 29.025 ;
     RECT  2.16 29.295 19.44 29.565 ;
     RECT  2.16 29.835 19.44 30.105 ;
     RECT  2.16 30.375 19.44 30.645 ;
     RECT  2.16 30.915 19.44 31.185 ;
     RECT  2.16 31.455 19.44 31.725 ;
     RECT  2.16 31.995 19.44 32.265 ;
     RECT  2.16 32.535 19.44 32.805 ;
     RECT  2.16 33.075 19.44 33.345 ;
     RECT  2.16 33.615 19.44 33.885 ;
     RECT  2.16 34.155 19.44 34.425 ;
     RECT  2.16 34.695 19.44 34.965 ;
     RECT  2.16 35.235 19.44 35.505 ;
     RECT  2.16 35.775 19.44 36.045 ;
     RECT  2.16 36.315 19.44 36.585 ;
     RECT  2.16 36.855 19.44 37.125 ;
     RECT  2.16 37.395 19.44 37.665 ;
     RECT  2.16 37.935 19.44 38.205 ;
     RECT  2.16 38.475 19.44 38.745 ;
     RECT  2.16 39.015 19.44 39.285 ;
     RECT  2.16 39.555 19.44 39.825 ;
     RECT  2.16 40.095 19.44 40.365 ;
     RECT  2.16 40.635 19.44 40.905 ;
     RECT  2.16 41.175 19.44 41.445 ;
     RECT  2.16 41.715 19.44 41.985 ;
     RECT  2.16 42.255 19.44 42.525 ;
     RECT  2.16 42.795 19.44 43.065 ;
     RECT  2.16 43.335 19.44 43.605 ;
     RECT  2.16 43.875 19.44 44.145 ;
     RECT  2.16 44.415 19.44 44.685 ;
     RECT  2.16 44.955 19.44 45.225 ;
     RECT  2.16 45.495 19.44 45.765 ;
     RECT  2.16 46.035 19.44 46.305 ;
     RECT  2.16 46.575 19.44 46.845 ;
     RECT  2.16 47.115 19.44 47.385 ;
     RECT  2.16 47.655 19.44 47.925 ;
     RECT  2.16 48.195 19.44 48.465 ;
     RECT  2.16 48.735 19.44 49.005 ;
     RECT  2.16 49.275 19.44 49.545 ;
     RECT  2.16 49.815 19.44 50.085 ;
     RECT  2.16 50.355 19.44 50.625 ;
     RECT  2.16 50.895 19.44 51.165 ;
     RECT  2.16 51.435 19.44 51.705 ;
     RECT  2.16 51.975 19.44 52.245 ;
     RECT  2.16 52.515 19.44 52.785 ;
     RECT  2.16 53.055 19.44 53.325 ;
     RECT  2.16 53.595 19.44 53.865 ;
     RECT  2.16 54.135 19.44 54.405 ;
     RECT  2.16 54.675 19.44 54.945 ;
     RECT  2.16 55.215 19.44 55.485 ;
     RECT  2.16 55.755 19.44 56.025 ;
     RECT  2.16 56.295 19.44 56.565 ;
     RECT  2.16 56.835 19.44 57.105 ;
     RECT  2.16 57.375 19.44 57.645 ;
     RECT  2.16 57.915 19.44 58.185 ;
     RECT  2.16 58.455 19.44 58.725 ;
     RECT  2.16 58.995 19.44 59.265 ;
     RECT  2.16 59.535 19.44 59.805 ;
     RECT  2.16 60.075 19.44 60.345 ;
     RECT  2.16 60.615 19.44 60.885 ;
     RECT  2.16 61.155 19.44 61.425 ;
     RECT  2.16 61.695 19.44 61.965 ;
     RECT  2.16 62.235 19.44 62.505 ;
     RECT  2.16 62.775 19.44 63.045 ;
     RECT  2.16 63.315 19.44 63.585 ;
     RECT  2.16 63.855 19.44 64.125 ;
     RECT  2.16 64.395 19.44 64.665 ;
     RECT  2.16 64.935 19.44 65.205 ;
     RECT  2.16 65.475 19.44 65.745 ;
     RECT  2.16 66.015 19.44 66.285 ;
     RECT  2.16 66.555 19.44 66.825 ;
     RECT  2.16 67.095 19.44 67.365 ;
     RECT  2.16 67.635 19.44 67.905 ;
     RECT  2.16 68.175 19.44 68.445 ;
     RECT  2.16 68.715 19.44 68.985 ;
     RECT  2.16 69.255 19.44 69.525 ;
     RECT  2.16 69.795 19.44 70.065 ;
     RECT  2.16 70.335 19.44 70.605 ;
     RECT  2.16 70.875 19.44 71.145 ;
     RECT  2.16 71.415 19.44 71.685 ;
     RECT  2.16 71.955 19.44 72.225 ;
     RECT  2.16 72.495 19.44 72.765 ;
     RECT  2.16 73.035 19.44 73.305 ;
     RECT  2.16 73.575 19.44 73.845 ;
     RECT  2.16 74.115 19.44 74.385 ;
     RECT  2.16 74.655 19.44 74.925 ;
     RECT  2.16 75.195 19.44 75.465 ;
    LAYER M1 ;
     RECT  2.16 2.151 19.44 75.609 ;
    LAYER M2 ;
     RECT  0.211 14.256 0.247 14.274 ;
     RECT  0.067 50.4 0.247 50.418 ;
     RECT  0.211 34.74 0.283 34.758 ;
     RECT  0.211 35.856 0.283 35.874 ;
     RECT  0.211 6.696 0.311 6.804 ;
     RECT  0.211 15.336 0.311 15.354 ;
     RECT  0.031 44.622 0.319 44.64 ;
     RECT  0.283 34.74 0.383 35.874 ;
     RECT  0.211 66.024 0.427 66.042 ;
     RECT  0.427 55.998 0.463 56.016 ;
     RECT  0.427 58.392 0.463 58.41 ;
     RECT  0.427 66.024 0.463 66.618 ;
     RECT  0.031 54.414 0.499 54.432 ;
     RECT  0.463 55.998 0.499 56.124 ;
     RECT  0.463 58.122 0.499 58.41 ;
     RECT  0.247 61.704 0.499 61.722 ;
     RECT  0.211 62.631 0.499 62.649 ;
     RECT  0.211 64.836 0.499 64.854 ;
     RECT  0.463 65.646 0.499 66.618 ;
     RECT  0.211 69.876 0.499 69.894 ;
     RECT  0.499 27.846 0.535 27.864 ;
     RECT  0.211 32.436 0.535 32.454 ;
     RECT  0.211 39.186 0.535 39.204 ;
     RECT  0.499 40.608 0.535 40.626 ;
     RECT  0.499 42.57 0.535 43.164 ;
     RECT  0.319 43.956 0.535 44.64 ;
     RECT  0.211 52.956 0.535 52.974 ;
     RECT  0.499 55.764 0.535 56.124 ;
     RECT  0.499 57.546 0.535 58.644 ;
     RECT  0.499 61.326 0.535 61.722 ;
     RECT  0.499 62.478 0.535 62.649 ;
     RECT  0.247 63.756 0.535 63.774 ;
     RECT  0.499 64.836 0.535 66.654 ;
     RECT  0.211 68.886 0.535 68.904 ;
     RECT  0.499 69.768 0.535 69.894 ;
     RECT  0.211 71.154 0.535 71.172 ;
     RECT  0.211 72.936 0.535 72.954 ;
     RECT  0.535 39.096 1.075 39.204 ;
     RECT  0.211 20.16 1.111 20.646 ;
     RECT  1.075 39.096 1.111 39.348 ;
     RECT  0.535 40.104 1.111 41.094 ;
     RECT  0.535 55.764 1.111 58.644 ;
     RECT  0.535 59.616 1.111 59.634 ;
     RECT  0.535 42.066 1.147 44.64 ;
     RECT  0.499 54.414 1.183 54.774 ;
     RECT  1.111 55.764 1.183 59.634 ;
     RECT  0.535 27.846 1.219 28.44 ;
     RECT  1.111 38.286 1.219 38.304 ;
     RECT  0.535 31.806 1.255 32.454 ;
     RECT  0.535 13.446 1.291 13.464 ;
     RECT  1.255 31.77 1.291 32.454 ;
     RECT  0.211 33.516 1.291 33.534 ;
     RECT  0.211 37.026 1.291 37.044 ;
     RECT  0.247 50.094 1.363 50.418 ;
     RECT  1.291 31.77 1.399 33.534 ;
     RECT  0.383 34.74 1.435 34.758 ;
     RECT  0.383 35.856 1.435 35.874 ;
     RECT  1.291 36.756 1.435 37.044 ;
     RECT  1.111 20.16 1.471 20.754 ;
     RECT  1.435 35.856 1.471 37.044 ;
     RECT  1.219 38.214 1.471 38.304 ;
     RECT  0.535 26.946 1.507 26.964 ;
     RECT  1.219 27.756 1.507 28.44 ;
     RECT  1.399 45.846 1.507 45.864 ;
     RECT  1.147 46.746 1.507 46.764 ;
     RECT  1.147 17.766 1.543 17.784 ;
     RECT  1.435 34.74 1.543 34.794 ;
     RECT  1.471 35.856 1.543 38.304 ;
     RECT  1.111 39.096 1.543 41.094 ;
     RECT  1.183 54.414 1.543 59.634 ;
     RECT  0.535 60.39 1.543 60.408 ;
     RECT  1.543 17.19 1.579 17.784 ;
     RECT  1.435 25.101 1.615 25.119 ;
     RECT  0.535 30.078 1.651 30.096 ;
     RECT  1.543 54.414 1.687 60.408 ;
     RECT  1.543 34.74 1.723 41.094 ;
     RECT  1.435 51.408 1.723 51.426 ;
     RECT  0.535 52.416 1.723 52.974 ;
     RECT  1.363 50.094 1.759 50.544 ;
     RECT  1.651 30.078 1.795 30.744 ;
     RECT  1.723 34.74 1.795 41.166 ;
     RECT  1.147 42.066 1.795 44.712 ;
     RECT  1.795 29.466 1.831 30.744 ;
     RECT  1.399 31.698 1.831 33.534 ;
     RECT  1.507 45.846 1.831 46.764 ;
     RECT  1.795 34.74 1.867 44.712 ;
     RECT  1.831 45.576 1.867 46.764 ;
     RECT  0.311 6.786 1.903 6.804 ;
     RECT  0.211 48.546 1.903 48.564 ;
     RECT  1.867 8.748 1.939 8.766 ;
     RECT  1.723 51.408 1.939 52.974 ;
     RECT  1.615 25.101 1.975 25.2 ;
     RECT  1.867 34.74 1.975 46.764 ;
     RECT  1.831 29.466 2.011 33.534 ;
     RECT  1.975 34.74 2.011 47.304 ;
     RECT  0.571 23.706 2.083 23.724 ;
     RECT  0.535 61.326 2.083 66.744 ;
     RECT  1.075 22.518 2.119 22.536 ;
     RECT  0.211 4.356 2.16 4.374 ;
     RECT  1.903 6.786 2.16 7.452 ;
     RECT  1.939 8.748 2.16 9.306 ;
     RECT  1.687 10.206 2.16 10.224 ;
     RECT  1.291 13.176 2.16 13.464 ;
     RECT  0.247 14.256 2.16 14.436 ;
     RECT  1.579 17.19 2.16 18.288 ;
     RECT  1.471 19.656 2.16 20.754 ;
     RECT  2.119 21.942 2.16 22.536 ;
     RECT  2.083 23.328 2.16 23.724 ;
     RECT  1.975 25.101 2.16 26.082 ;
     RECT  1.507 26.946 2.16 28.44 ;
     RECT  2.011 29.466 2.16 47.304 ;
     RECT  1.903 48.096 2.16 48.564 ;
     RECT  1.759 50.022 2.16 50.544 ;
     RECT  1.939 51.408 2.16 53.244 ;
     RECT  1.687 54.306 2.16 60.408 ;
     RECT  2.083 61.326 2.16 67.284 ;
     RECT  0.535 68.346 2.16 70.092 ;
     RECT  0.535 71.154 2.16 71.604 ;
     RECT  0.535 72.774 2.16 72.954 ;
     RECT  2.16 2.151 19.44 75.609 ;
     RECT  19.44 4.23 19.463 18.486 ;
     RECT  19.463 4.23 19.967 15.516 ;
     RECT  19.463 16.308 19.967 18.486 ;
     RECT  19.44 19.278 19.967 20.646 ;
     RECT  19.44 21.438 19.967 40.014 ;
     RECT  19.44 40.806 19.967 52.074 ;
     RECT  19.44 52.83 19.967 56.394 ;
     RECT  19.44 57.15 19.967 58.644 ;
     RECT  19.44 59.436 19.967 60.714 ;
     RECT  19.44 61.596 19.967 65.502 ;
     RECT  19.44 66.456 19.967 71.514 ;
     RECT  19.967 6.318 20.003 6.408 ;
     RECT  19.967 8.28 20.003 8.298 ;
     RECT  19.967 9.558 20.003 9.576 ;
     RECT  19.967 10.98 20.003 10.998 ;
     RECT  19.967 13.338 20.003 13.356 ;
     RECT  19.967 16.578 20.003 17.676 ;
     RECT  19.967 20.358 20.003 20.376 ;
     RECT  19.967 21.438 20.003 21.996 ;
     RECT  19.967 22.788 20.003 22.806 ;
     RECT  19.967 24.408 20.003 24.426 ;
     RECT  19.967 27.18 20.003 27.936 ;
     RECT  19.967 28.728 20.003 28.746 ;
     RECT  19.967 29.574 20.003 29.592 ;
     RECT  19.967 31.968 20.003 31.986 ;
     RECT  19.967 34.668 20.003 37.62 ;
     RECT  19.967 41.076 20.003 42.75 ;
     RECT  19.967 63.216 20.003 65.502 ;
     RECT  20.003 6.318 20.039 6.336 ;
     RECT  20.003 21.438 20.039 21.456 ;
     RECT  19.967 30.771 20.039 30.789 ;
     RECT  20.003 35.82 20.039 36.846 ;
     RECT  20.003 42.156 20.039 42.75 ;
     RECT  19.967 48.132 20.147 51.732 ;
     RECT  20.003 41.076 20.507 41.4 ;
     RECT  20.039 42.156 20.507 42.714 ;
     RECT  19.967 44.586 20.507 46.8 ;
     RECT  20.147 48.132 20.507 49.464 ;
     RECT  20.147 50.256 20.507 51.732 ;
     RECT  19.967 52.83 20.507 54.936 ;
     RECT  19.967 57.15 20.507 58.104 ;
     RECT  19.967 59.436 20.507 59.724 ;
     RECT  19.967 60.516 20.507 60.714 ;
     RECT  19.967 61.596 20.507 62.334 ;
     RECT  20.003 63.216 20.507 64.89 ;
     RECT  19.967 66.456 20.507 67.122 ;
     RECT  19.967 4.23 20.543 4.248 ;
     RECT  20.039 36.558 20.543 36.576 ;
     RECT  20.003 37.602 20.543 37.62 ;
     RECT  19.967 38.718 20.543 39.744 ;
     RECT  20.507 42.696 20.543 42.714 ;
     RECT  19.967 43.776 20.543 43.794 ;
     RECT  20.507 44.586 20.543 45.684 ;
     RECT  20.507 46.656 20.543 46.8 ;
     RECT  20.507 48.942 20.543 48.96 ;
     RECT  20.507 51.714 20.543 51.732 ;
     RECT  20.507 52.83 20.543 52.848 ;
     RECT  20.507 53.946 20.543 54.774 ;
     RECT  20.507 57.15 20.543 57.168 ;
     RECT  20.507 57.996 20.543 58.104 ;
     RECT  20.507 60.696 20.543 60.714 ;
     RECT  20.507 62.28 20.543 62.298 ;
     RECT  20.507 63.216 20.543 63.234 ;
     RECT  20.507 64.026 20.543 64.89 ;
     RECT  20.507 67.104 20.543 67.122 ;
     RECT  19.967 67.986 20.543 68.4 ;
     RECT  19.967 69.3 20.543 70.02 ;
     RECT  19.967 70.956 20.543 71.244 ;
     RECT  19.44 72.306 20.543 72.954 ;
     RECT  20.543 44.856 20.579 44.874 ;
     RECT  20.543 54.486 20.579 54.504 ;
     RECT  20.543 71.226 20.579 71.244 ;
     RECT  20.003 17.001 21.407 17.019 ;
    LAYER M3 ;
     RECT  10.8 1.723 10.818 2.143 ;
     RECT  10.515 2.143 10.818 2.191 ;
     RECT  10.515 2.191 11.43 2.263 ;
     RECT  10.515 2.263 11.646 2.291 ;
     RECT  2.415 2.143 2.505 2.413 ;
     RECT  5.115 2.143 5.205 2.413 ;
     RECT  7.815 2.143 7.905 2.413 ;
     RECT  13.215 2.143 13.305 2.413 ;
     RECT  15.915 2.143 16.005 2.413 ;
     RECT  18.615 2.143 18.705 2.413 ;
     RECT  18.615 2.413 18.897 3.955 ;
     RECT  18.615 3.955 19.314 4.351 ;
     RECT  11.628 2.291 11.646 4.415 ;
     RECT  2.415 2.413 2.697 4.459 ;
     RECT  17.46 4.351 17.478 4.495 ;
     RECT  18.36 4.351 19.314 4.495 ;
     RECT  5.115 2.413 5.397 4.507 ;
     RECT  17.46 4.495 19.314 4.507 ;
     RECT  20.52 4.225 20.538 4.507 ;
     RECT  13.215 2.413 13.497 4.531 ;
     RECT  4.644 4.507 5.397 4.621 ;
     RECT  4.14 4.621 5.397 4.657 ;
     RECT  15.084 4.693 15.102 4.729 ;
     RECT  0.216 4.351 0.234 4.733 ;
     RECT  4.032 4.657 5.397 4.765 ;
     RECT  2.415 4.459 3.006 4.801 ;
     RECT  7.815 2.413 8.097 4.801 ;
     RECT  15.915 2.413 16.197 4.801 ;
     RECT  17.46 4.507 20.538 4.829 ;
     RECT  15.915 4.801 16.254 4.891 ;
     RECT  4.032 4.765 6.03 4.919 ;
     RECT  7.38 4.801 8.097 4.963 ;
     RECT  17.46 4.829 19.962 4.999 ;
     RECT  15.915 4.891 16.65 5.035 ;
     RECT  17.424 4.999 19.962 5.035 ;
     RECT  15.048 4.729 15.102 5.071 ;
     RECT  7.164 4.963 8.097 5.117 ;
     RECT  2.304 4.801 3.006 5.197 ;
     RECT  15.048 5.071 15.174 5.197 ;
     RECT  4.032 4.919 5.562 5.233 ;
     RECT  12.492 4.531 13.497 5.233 ;
     RECT  14.328 5.197 15.174 5.233 ;
     RECT  15.915 5.035 19.962 5.261 ;
     RECT  12.492 5.233 13.518 5.269 ;
     RECT  14.292 5.233 15.174 5.269 ;
     RECT  15.915 5.261 16.254 5.269 ;
     RECT  10.515 2.291 10.797 5.431 ;
     RECT  2.196 5.197 3.006 5.495 ;
     RECT  2.268 5.495 3.006 5.515 ;
     RECT  3.78 5.233 5.562 5.515 ;
     RECT  17.424 5.261 19.962 5.729 ;
     RECT  12.492 5.269 16.254 5.809 ;
     RECT  7.815 5.117 8.097 5.845 ;
     RECT  12.096 5.809 16.254 6.035 ;
     RECT  0.216 5.947 0.234 6.043 ;
     RECT  19.944 5.729 19.962 6.043 ;
     RECT  7.092 5.845 8.097 6.079 ;
     RECT  14.868 6.035 16.254 6.151 ;
     RECT  12.096 6.035 13.914 6.179 ;
     RECT  0.216 6.043 0.414 6.221 ;
     RECT  14.868 6.151 16.506 6.241 ;
     RECT  17.424 5.729 19.098 6.241 ;
     RECT  14.868 6.241 19.098 6.275 ;
     RECT  19.944 6.043 19.998 6.313 ;
     RECT  10.515 5.431 10.854 6.449 ;
     RECT  15.732 6.275 19.098 6.511 ;
     RECT  19.944 6.313 20.034 6.511 ;
     RECT  15.732 6.511 20.034 6.557 ;
     RECT  12.096 6.179 13.518 6.667 ;
     RECT  0.216 6.221 0.306 6.719 ;
     RECT  12.024 6.667 13.518 6.719 ;
     RECT  12.096 6.719 13.518 6.749 ;
     RECT  6.948 6.079 8.097 6.817 ;
     RECT  0.216 6.719 0.234 6.893 ;
     RECT  2.268 5.515 5.562 6.925 ;
     RECT  14.868 6.275 14.886 7.099 ;
     RECT  15.732 6.557 19.962 7.099 ;
     RECT  12.132 6.749 13.518 7.123 ;
     RECT  14.868 7.099 19.962 7.123 ;
     RECT  12.132 7.123 19.962 7.259 ;
     RECT  12.132 7.259 19.026 7.349 ;
     RECT  14.256 7.349 19.026 7.385 ;
     RECT  2.268 6.925 5.814 7.429 ;
     RECT  10.515 6.449 10.797 7.429 ;
     RECT  12.132 7.349 13.518 7.619 ;
     RECT  14.256 7.385 15.03 7.619 ;
     RECT  12.132 7.619 13.497 7.627 ;
     RECT  12.06 7.627 13.497 7.691 ;
     RECT  1.908 7.429 5.814 7.771 ;
     RECT  6.66 6.817 8.097 7.771 ;
     RECT  19.944 7.259 19.962 7.771 ;
     RECT  0.252 7.531 0.27 7.901 ;
     RECT  12.276 7.691 13.497 7.925 ;
     RECT  15.915 7.385 19.026 8.005 ;
     RECT  15.915 8.005 19.098 8.059 ;
     RECT  19.944 7.771 19.998 8.059 ;
     RECT  14.4 7.619 15.03 8.155 ;
     RECT  15.915 8.059 19.998 8.155 ;
     RECT  14.4 8.155 19.998 8.303 ;
     RECT  10.515 7.429 10.854 8.339 ;
     RECT  12.348 7.925 13.497 8.395 ;
     RECT  14.4 8.303 19.962 8.395 ;
     RECT  0.216 8.347 0.234 8.477 ;
     RECT  12.348 8.395 19.962 8.731 ;
     RECT  1.908 7.771 8.097 8.743 ;
     RECT  12.06 8.731 19.962 8.807 ;
     RECT  12.06 8.807 19.062 9.113 ;
     RECT  19.944 8.807 19.962 9.307 ;
     RECT  12.06 9.113 19.026 9.509 ;
     RECT  12.06 9.509 14.562 9.545 ;
     RECT  15.3 9.509 19.026 9.895 ;
     RECT  1.872 8.743 8.097 10.201 ;
     RECT  12.06 9.545 14.454 10.253 ;
     RECT  10.515 8.339 10.797 10.291 ;
     RECT  10.515 10.291 10.854 10.391 ;
     RECT  12.564 10.253 14.454 10.471 ;
     RECT  15.3 9.895 19.098 10.471 ;
     RECT  12.564 10.471 19.098 10.555 ;
     RECT  19.944 9.307 19.998 10.555 ;
     RECT  0.216 10.843 0.234 10.973 ;
     RECT  12.564 10.555 19.998 11.003 ;
     RECT  12.564 11.003 19.962 11.209 ;
     RECT  12.06 11.209 19.962 11.261 ;
     RECT  10.515 10.391 10.797 12.091 ;
     RECT  12.564 11.261 19.962 12.523 ;
     RECT  12.096 12.523 19.962 12.749 ;
     RECT  12.24 12.749 19.962 12.857 ;
     RECT  19.944 12.857 19.962 13.051 ;
     RECT  12.24 12.857 19.026 13.091 ;
     RECT  10.515 12.091 10.854 13.135 ;
     RECT  1.692 10.201 8.097 13.171 ;
     RECT  19.944 13.051 19.998 13.361 ;
     RECT  10.515 13.135 10.926 13.469 ;
     RECT  15.915 13.091 19.026 13.579 ;
     RECT  19.944 13.361 19.962 13.579 ;
     RECT  12.24 13.091 15.138 13.675 ;
     RECT  0.54 13.441 0.558 13.709 ;
     RECT  12.06 13.675 15.138 13.909 ;
     RECT  15.915 13.579 19.962 13.909 ;
     RECT  12.06 13.909 19.962 14.189 ;
     RECT  0.216 14.011 0.27 14.279 ;
     RECT  12.564 14.189 19.962 14.477 ;
     RECT  10.515 13.469 10.797 14.611 ;
     RECT  13.032 14.477 19.962 14.747 ;
     RECT  13.032 14.747 19.026 14.819 ;
     RECT  0.252 14.279 0.27 15.163 ;
     RECT  0.216 15.163 0.27 15.307 ;
     RECT  0.216 15.307 0.306 15.359 ;
     RECT  0.216 15.359 0.27 15.389 ;
     RECT  10.515 14.611 10.854 15.457 ;
     RECT  14.544 14.819 19.026 15.485 ;
     RECT  13.032 14.819 13.698 15.493 ;
     RECT  14.652 15.485 19.026 15.595 ;
     RECT  19.944 14.747 19.962 15.595 ;
     RECT  12.348 15.493 13.698 15.601 ;
     RECT  10.515 15.457 10.926 15.629 ;
     RECT  0.252 15.389 0.27 15.725 ;
     RECT  12.276 15.601 13.878 15.739 ;
     RECT  12.06 15.739 13.878 16.259 ;
     RECT  14.652 15.595 19.962 16.315 ;
     RECT  10.515 15.629 10.854 16.367 ;
     RECT  14.652 16.315 19.998 16.375 ;
     RECT  14.472 16.375 19.998 16.709 ;
     RECT  0.252 16.699 0.27 16.829 ;
     RECT  21.384 16.996 21.402 17.117 ;
     RECT  10.515 16.367 10.797 17.419 ;
     RECT  12.06 16.259 13.698 17.491 ;
     RECT  14.544 16.709 19.998 17.491 ;
     RECT  1.296 13.171 8.097 17.515 ;
     RECT  10.515 17.419 10.854 17.519 ;
     RECT  12.06 17.491 19.998 17.609 ;
     RECT  14.544 17.609 19.998 17.681 ;
     RECT  1.152 17.515 8.097 17.789 ;
     RECT  12.06 17.609 13.698 17.933 ;
     RECT  12.168 17.933 13.698 18.463 ;
     RECT  10.515 17.519 10.797 18.499 ;
     RECT  14.544 17.681 19.962 18.563 ;
     RECT  12.168 18.463 13.734 18.571 ;
     RECT  10.515 18.499 10.854 18.599 ;
     RECT  12.168 18.571 13.878 18.797 ;
     RECT  0.252 18.859 0.27 18.989 ;
     RECT  14.652 18.563 19.962 19.345 ;
     RECT  10.515 18.599 10.797 19.381 ;
     RECT  12.168 18.797 13.734 19.381 ;
     RECT  12.132 19.381 13.734 19.651 ;
     RECT  14.508 19.345 19.962 19.651 ;
     RECT  12.132 19.651 19.962 19.723 ;
     RECT  12.096 19.723 19.962 19.769 ;
     RECT  12.132 19.769 19.962 20.107 ;
     RECT  12.132 20.107 19.998 20.381 ;
     RECT  12.132 20.381 19.962 20.587 ;
     RECT  0.216 19.819 0.234 20.651 ;
     RECT  12.06 20.587 19.962 20.651 ;
     RECT  12.24 20.651 19.962 20.723 ;
     RECT  1.296 17.789 8.097 20.731 ;
     RECT  12.24 20.723 12.294 20.957 ;
     RECT  10.515 19.381 10.854 21.091 ;
     RECT  13.032 20.723 19.962 21.115 ;
     RECT  10.515 21.091 10.926 21.127 ;
     RECT  10.515 21.127 10.998 21.263 ;
     RECT  13.032 21.115 19.998 21.355 ;
     RECT  13.032 21.355 20.034 21.461 ;
     RECT  13.032 21.461 19.998 21.505 ;
     RECT  10.515 21.263 10.926 21.569 ;
     RECT  12.564 21.505 19.998 21.691 ;
     RECT  12.06 21.691 19.998 21.731 ;
     RECT  10.515 21.569 10.797 22.072 ;
     RECT  10.404 22.072 10.797 22.109 ;
     RECT  0.288 22.363 0.306 22.493 ;
     RECT  1.116 20.731 8.097 22.513 ;
     RECT  10.515 22.109 10.797 22.513 ;
     RECT  10.515 22.513 10.854 22.613 ;
     RECT  12.384 21.731 19.998 22.811 ;
     RECT  1.08 22.513 8.097 23.053 ;
     RECT  12.384 22.811 19.962 23.089 ;
     RECT  1.08 23.053 8.262 23.179 ;
     RECT  0.576 23.179 8.262 23.729 ;
     RECT  10.515 22.613 10.797 24.133 ;
     RECT  12.096 23.089 19.962 24.139 ;
     RECT  12.096 24.139 19.998 24.431 ;
     RECT  0.216 23.995 0.234 24.461 ;
     RECT  10.515 24.133 10.854 24.511 ;
     RECT  10.515 24.511 10.926 24.809 ;
     RECT  0.252 24.859 0.27 24.989 ;
     RECT  1.08 23.729 8.262 25.321 ;
     RECT  9.108 25.321 9.126 25.439 ;
     RECT  10.515 24.809 10.797 25.753 ;
     RECT  12.096 24.431 19.962 25.817 ;
     RECT  10.515 25.753 10.926 25.889 ;
     RECT  12.096 25.817 19.026 26.761 ;
     RECT  10.515 25.889 10.797 26.824 ;
     RECT  10.515 26.824 10.854 26.827 ;
     RECT  19.944 25.817 19.962 26.86 ;
     RECT  12.06 26.761 19.026 26.869 ;
     RECT  19.944 26.86 19.998 26.869 ;
     RECT  10.515 26.827 10.998 26.897 ;
     RECT  1.08 25.321 8.298 26.941 ;
     RECT  0.54 26.941 8.298 27.019 ;
     RECT  9.108 26.941 9.126 27.059 ;
     RECT  12.06 26.869 19.998 27.329 ;
     RECT  12.06 27.329 19.098 27.365 ;
     RECT  0.288 27.019 8.298 27.547 ;
     RECT  0.216 27.547 8.298 27.677 ;
     RECT  10.515 26.897 10.926 27.779 ;
     RECT  12.06 27.365 19.026 28.561 ;
     RECT  19.944 27.329 19.998 28.561 ;
     RECT  0.504 27.677 8.298 28.589 ;
     RECT  10.515 27.779 10.797 28.759 ;
     RECT  0.252 28.795 0.27 28.925 ;
     RECT  12.06 28.561 19.998 29.597 ;
     RECT  10.515 28.759 10.854 29.939 ;
     RECT  12.06 29.597 19.962 30.065 ;
     RECT  1.08 28.589 8.298 30.073 ;
     RECT  0.54 30.073 8.298 30.269 ;
     RECT  12.276 30.065 19.962 30.335 ;
     RECT  12.888 30.335 19.962 30.667 ;
     RECT  12.888 30.667 20.034 30.794 ;
     RECT  12.06 31.189 12.078 31.195 ;
     RECT  11.952 31.195 12.078 31.261 ;
     RECT  12.888 30.794 19.962 31.261 ;
     RECT  11.952 31.261 19.962 31.289 ;
     RECT  0.216 31.483 0.234 31.613 ;
     RECT  12.06 31.289 19.962 31.675 ;
     RECT  10.515 29.939 10.797 31.693 ;
     RECT  1.08 30.269 8.298 31.801 ;
     RECT  10.515 31.693 10.854 31.829 ;
     RECT  12.06 31.675 19.998 31.991 ;
     RECT  0.252 31.801 8.298 32.428 ;
     RECT  0.216 32.428 8.298 32.573 ;
     RECT  12.06 31.991 19.962 33.071 ;
     RECT  0.216 32.573 0.306 33.245 ;
     RECT  0.216 33.245 0.234 33.773 ;
     RECT  12.06 33.071 18.954 33.931 ;
     RECT  19.944 33.071 19.962 33.931 ;
     RECT  1.08 32.573 8.298 34.195 ;
     RECT  10.515 31.829 10.797 34.231 ;
     RECT  12.06 33.931 19.962 34.411 ;
     RECT  10.515 34.231 10.926 34.493 ;
     RECT  0.252 34.555 0.27 34.732 ;
     RECT  0.216 34.732 0.27 34.925 ;
     RECT  12.06 34.411 19.998 35.159 ;
     RECT  0.288 34.939 0.306 35.401 ;
     RECT  1.08 34.195 8.406 35.401 ;
     RECT  0.288 35.401 8.406 35.453 ;
     RECT  10.515 34.493 10.854 35.509 ;
     RECT  0.288 35.453 0.306 35.597 ;
     RECT  10.515 35.509 10.926 35.609 ;
     RECT  19.944 35.159 19.998 35.815 ;
     RECT  0.216 35.851 0.234 35.933 ;
     RECT  12.06 35.159 18.99 36.005 ;
     RECT  13.032 36.005 18.99 36.049 ;
     RECT  13.032 36.049 19.098 36.319 ;
     RECT  13.032 36.319 19.17 36.419 ;
     RECT  19.944 35.815 20.034 36.427 ;
     RECT  19.944 36.427 20.538 36.581 ;
     RECT  0.252 36.619 0.27 36.749 ;
     RECT  19.944 36.581 20.034 36.851 ;
     RECT  12.06 36.005 12.258 36.931 ;
     RECT  13.032 36.419 19.098 36.931 ;
     RECT  0.216 37.021 0.234 37.421 ;
     RECT  12.06 36.931 19.098 37.435 ;
     RECT  19.944 36.851 19.998 37.435 ;
     RECT  12.06 37.435 19.998 37.597 ;
     RECT  12.06 37.597 20.538 37.709 ;
     RECT  10.515 35.609 10.854 37.867 ;
     RECT  10.515 37.867 10.89 37.939 ;
     RECT  12.06 37.709 19.962 38.129 ;
     RECT  12.06 38.129 19.098 38.165 ;
     RECT  19.944 38.129 19.962 38.443 ;
     RECT  10.515 37.939 10.926 38.579 ;
     RECT  19.944 38.443 20.034 38.713 ;
     RECT  12.06 38.165 18.897 39.011 ;
     RECT  0.252 38.443 0.27 39.091 ;
     RECT  1.08 35.453 8.406 39.091 ;
     RECT  0.252 39.091 8.406 39.181 ;
     RECT  12.24 39.011 18.897 39.209 ;
     RECT  12.78 39.209 18.897 39.293 ;
     RECT  0.216 39.181 8.406 39.437 ;
     RECT  13.104 39.293 18.897 39.488 ;
     RECT  10.515 38.579 10.797 39.631 ;
     RECT  10.515 39.631 10.854 39.749 ;
     RECT  19.944 38.713 20.538 39.869 ;
     RECT  13.215 39.488 18.897 40.135 ;
     RECT  13.215 40.135 18.954 40.559 ;
     RECT  0.54 39.437 8.406 40.588 ;
     RECT  0.504 40.588 8.406 41.069 ;
     RECT  19.944 39.869 19.962 41.071 ;
     RECT  10.515 39.749 10.797 41.215 ;
     RECT  10.515 41.215 10.926 41.369 ;
     RECT  0.54 41.069 8.406 41.917 ;
     RECT  0.54 41.917 8.694 41.947 ;
     RECT  0.252 41.947 8.694 42.089 ;
     RECT  19.944 41.071 20.502 42.365 ;
     RECT  10.515 41.369 10.797 42.601 ;
     RECT  20.016 42.365 20.502 42.691 ;
     RECT  10.515 42.601 10.854 42.719 ;
     RECT  13.215 40.559 18.897 42.835 ;
     RECT  13.215 42.835 19.17 42.989 ;
     RECT  20.016 42.691 20.538 43.231 ;
     RECT  10.515 42.719 10.797 43.645 ;
     RECT  10.515 43.645 10.926 43.799 ;
     RECT  0.252 42.089 8.406 43.853 ;
     RECT  0.324 43.853 8.406 44.093 ;
     RECT  19.944 43.231 20.538 44.381 ;
     RECT  1.152 44.093 8.406 44.717 ;
     RECT  10.515 43.799 10.797 44.761 ;
     RECT  20.52 44.381 20.538 44.851 ;
     RECT  10.515 44.761 10.854 44.879 ;
     RECT  13.215 42.989 18.897 44.995 ;
     RECT  0.036 44.617 0.054 45.067 ;
     RECT  13.215 44.995 19.026 45.149 ;
     RECT  20.52 44.851 20.574 45.149 ;
     RECT  0.036 45.067 0.27 45.259 ;
     RECT  0.036 45.259 0.306 45.437 ;
     RECT  1.296 44.717 8.406 45.661 ;
     RECT  20.52 45.149 20.538 45.689 ;
     RECT  1.296 45.661 8.442 45.725 ;
     RECT  10.515 44.879 10.797 45.805 ;
     RECT  10.515 45.805 10.818 45.841 ;
     RECT  13.215 45.149 18.897 45.883 ;
     RECT  10.515 45.841 10.926 45.995 ;
     RECT  10.515 45.995 10.818 46.031 ;
     RECT  13.215 45.883 19.422 46.139 ;
     RECT  20.484 46.123 20.502 46.229 ;
     RECT  13.215 46.139 18.954 46.337 ;
     RECT  1.296 45.725 8.406 46.471 ;
     RECT  1.296 46.471 8.658 46.571 ;
     RECT  1.296 46.571 8.37 46.699 ;
     RECT  10.515 46.031 10.797 46.813 ;
     RECT  10.515 46.813 10.926 46.913 ;
     RECT  20.52 46.603 20.538 46.925 ;
     RECT  13.215 46.337 18.897 47.191 ;
     RECT  1.152 46.699 8.37 47.261 ;
     RECT  13.215 47.191 18.954 47.309 ;
     RECT  10.515 46.913 10.797 47.695 ;
     RECT  1.296 47.261 8.37 48.043 ;
     RECT  19.944 47.131 19.962 48.127 ;
     RECT  1.152 48.043 8.37 48.173 ;
     RECT  0.036 45.437 0.054 48.379 ;
     RECT  19.944 48.127 20.502 48.695 ;
     RECT  0.036 48.379 0.234 48.763 ;
     RECT  20.124 48.695 20.502 48.859 ;
     RECT  0.036 48.763 0.27 48.893 ;
     RECT  20.124 48.859 20.538 48.965 ;
     RECT  13.215 47.309 18.897 49.081 ;
     RECT  13.215 49.081 18.954 49.351 ;
     RECT  10.515 47.695 10.854 49.469 ;
     RECT  13.215 49.351 19.098 49.505 ;
     RECT  20.124 48.965 20.502 49.627 ;
     RECT  19.944 49.627 20.502 49.883 ;
     RECT  19.98 49.883 20.502 49.901 ;
     RECT  0.036 48.893 0.054 50.089 ;
     RECT  1.296 48.173 8.37 50.251 ;
     RECT  13.215 49.505 18.897 50.395 ;
     RECT  13.215 50.395 19.098 50.635 ;
     RECT  13.215 50.635 19.422 50.729 ;
     RECT  0.036 50.089 0.27 51.293 ;
     RECT  13.215 50.729 18.954 51.539 ;
     RECT  20.484 49.901 20.502 51.628 ;
     RECT  20.484 51.628 20.538 51.737 ;
     RECT  19.944 52.051 19.962 52.205 ;
     RECT  13.215 51.539 18.897 52.405 ;
     RECT  0.036 51.293 0.09 52.411 ;
     RECT  13.215 52.405 19.422 52.445 ;
     RECT  0.036 52.411 0.558 52.733 ;
     RECT  0.072 52.733 0.558 52.795 ;
     RECT  1.296 50.251 8.838 52.795 ;
     RECT  20.52 52.651 20.538 52.853 ;
     RECT  0.072 52.795 8.838 52.973 ;
     RECT  0.072 52.973 0.234 53.117 ;
     RECT  20.484 53.131 20.502 53.249 ;
     RECT  13.215 52.445 18.897 53.789 ;
     RECT  0.072 53.117 0.09 53.851 ;
     RECT  14.58 53.789 18.897 53.899 ;
     RECT  14.58 53.899 19.422 53.939 ;
     RECT  0.072 53.851 0.234 54.409 ;
     RECT  20.52 53.659 20.538 54.481 ;
     RECT  0.036 54.409 0.234 54.571 ;
     RECT  14.58 53.939 18.897 54.599 ;
     RECT  20.52 54.481 20.574 54.701 ;
     RECT  0.036 54.571 0.558 54.751 ;
     RECT  1.296 52.973 8.838 54.751 ;
     RECT  20.52 54.701 20.538 54.779 ;
     RECT  20.484 54.904 20.502 54.941 ;
     RECT  0.036 54.751 8.838 55.049 ;
     RECT  15.012 54.599 18.897 55.381 ;
     RECT  19.944 55.111 19.962 55.381 ;
     RECT  15.012 55.381 19.962 55.553 ;
     RECT  15.084 55.553 19.962 55.589 ;
     RECT  0.036 55.049 0.522 55.831 ;
     RECT  15.084 55.589 17.046 56.021 ;
     RECT  18 55.589 19.962 56.429 ;
     RECT  18 56.429 19.422 56.641 ;
     RECT  17.64 56.641 19.422 56.795 ;
     RECT  0.036 55.831 0.558 57.067 ;
     RECT  1.296 55.049 8.838 57.067 ;
     RECT  0.036 57.067 8.838 57.073 ;
     RECT  15.084 56.021 16.722 57.073 ;
     RECT  20.52 56.923 20.538 57.173 ;
     RECT  14.832 57.073 16.722 57.209 ;
     RECT  17.82 56.795 19.422 57.209 ;
     RECT  0.036 57.073 8.946 57.293 ;
     RECT  1.296 57.293 8.946 57.299 ;
     RECT  1.296 57.299 8.91 57.407 ;
     RECT  17.82 57.209 19.098 57.541 ;
     RECT  20.484 57.403 20.502 57.541 ;
     RECT  17.568 57.541 19.098 57.641 ;
     RECT  0.036 57.293 0.558 57.725 ;
     RECT  19.944 57.541 20.502 57.725 ;
     RECT  20.484 57.725 20.502 57.839 ;
     RECT  17.712 57.641 19.098 57.955 ;
     RECT  10.515 49.469 10.797 57.991 ;
     RECT  10.515 57.991 10.926 58.109 ;
     RECT  14.22 57.955 14.238 58.109 ;
     RECT  17.712 57.955 19.422 58.109 ;
     RECT  15.084 57.209 16.722 58.181 ;
     RECT  17.892 58.109 19.422 58.205 ;
     RECT  20.52 57.931 20.538 58.445 ;
     RECT  15.915 58.181 16.722 58.621 ;
     RECT  0.216 57.725 0.558 58.637 ;
     RECT  15.915 58.621 17.082 58.685 ;
     RECT  19.944 58.621 19.962 58.733 ;
     RECT  17.892 58.205 19.062 58.891 ;
     RECT  15.084 58.181 15.174 58.919 ;
     RECT  17.532 58.891 19.062 58.927 ;
     RECT  0.432 58.637 0.558 58.963 ;
     RECT  1.296 57.407 8.37 58.963 ;
     RECT  17.532 58.927 19.422 59.189 ;
     RECT  0.432 58.963 8.37 59.309 ;
     RECT  10.515 58.109 10.797 59.611 ;
     RECT  10.515 59.611 10.854 59.729 ;
     RECT  17.892 59.189 19.422 59.801 ;
     RECT  15.915 58.685 16.722 59.809 ;
     RECT  17.928 59.801 19.422 59.971 ;
     RECT  20.484 59.419 20.502 59.971 ;
     RECT  15.084 58.919 15.102 60.143 ;
     RECT  17.928 59.971 20.502 60.221 ;
     RECT  0.54 59.309 8.37 60.317 ;
     RECT  0.54 60.317 0.558 60.461 ;
     RECT  17.928 60.221 19.422 60.539 ;
     RECT  20.484 60.221 20.502 60.539 ;
     RECT  15.915 59.809 16.83 60.691 ;
     RECT  0.252 60.667 0.27 60.797 ;
     RECT  20.52 60.691 20.538 60.989 ;
     RECT  18.216 60.539 19.422 61.079 ;
     RECT  15.915 60.691 17.37 61.151 ;
     RECT  13.215 53.789 13.497 61.159 ;
     RECT  13.215 61.159 13.806 61.349 ;
     RECT  14.688 61.321 14.706 61.421 ;
     RECT  0.504 61.321 0.522 61.429 ;
     RECT  17.784 61.591 17.802 61.691 ;
     RECT  0.504 61.429 0.558 61.699 ;
     RECT  20.484 61.435 20.502 61.963 ;
     RECT  0.252 61.699 0.558 62.011 ;
     RECT  1.584 60.317 8.37 62.159 ;
     RECT  10.515 59.729 10.797 62.203 ;
     RECT  15.915 61.151 16.83 62.203 ;
     RECT  14.868 61.429 14.886 62.231 ;
     RECT  18.615 61.079 19.422 62.239 ;
     RECT  20.484 61.963 20.538 62.239 ;
     RECT  10.515 62.203 10.854 62.303 ;
     RECT  18.615 62.239 20.538 62.303 ;
     RECT  0.216 62.011 0.558 62.311 ;
     RECT  15.915 62.203 17.01 62.311 ;
     RECT  18.615 62.303 20.502 62.339 ;
     RECT  18.615 62.339 19.962 62.509 ;
     RECT  0.216 62.311 1.17 62.699 ;
     RECT  18.144 62.509 19.962 62.699 ;
     RECT  18.615 62.699 19.962 62.813 ;
     RECT  21.384 62.683 21.402 62.813 ;
     RECT  15.3 62.311 17.01 62.815 ;
     RECT  15.3 62.815 17.118 62.879 ;
     RECT  15.3 62.879 16.83 63.049 ;
     RECT  14.868 63.049 16.83 63.077 ;
     RECT  0.216 62.699 0.558 63.149 ;
     RECT  14.868 63.077 16.197 63.149 ;
     RECT  20.484 63.205 20.538 63.245 ;
     RECT  18.615 62.813 19.422 63.481 ;
     RECT  20.484 63.245 20.502 63.509 ;
     RECT  18 63.481 19.422 63.581 ;
     RECT  10.515 62.303 10.797 63.661 ;
     RECT  10.515 63.661 10.854 63.779 ;
     RECT  0.252 63.149 0.558 63.835 ;
     RECT  17.568 63.751 17.586 63.851 ;
     RECT  0.252 63.835 1.17 63.965 ;
     RECT  18.615 63.581 19.422 63.965 ;
     RECT  14.94 63.149 16.197 64.021 ;
     RECT  14.472 64.021 16.197 64.121 ;
     RECT  0.252 63.965 0.558 64.171 ;
     RECT  2.016 62.159 8.37 64.499 ;
     RECT  18.615 63.965 18.954 64.561 ;
     RECT  0.216 64.171 0.558 64.637 ;
     RECT  18.108 64.561 18.954 64.661 ;
     RECT  18.396 64.661 18.954 64.699 ;
     RECT  17.136 64.831 17.154 64.931 ;
     RECT  20.52 64.021 20.538 64.973 ;
     RECT  10.515 63.779 10.797 65.011 ;
     RECT  2.052 64.499 8.37 65.201 ;
     RECT  18.396 64.699 19.422 65.273 ;
     RECT  0.216 64.637 0.522 65.443 ;
     RECT  19.944 65.371 19.998 65.501 ;
     RECT  18.396 65.273 18.99 65.543 ;
     RECT  19.98 65.501 19.998 65.741 ;
     RECT  10.515 65.011 10.854 65.939 ;
     RECT  0.216 65.443 0.558 66.125 ;
     RECT  15.915 64.121 16.197 66.181 ;
     RECT  18.576 65.543 18.99 66.235 ;
     RECT  14.796 66.289 14.814 66.389 ;
     RECT  20.484 66.451 20.502 66.509 ;
     RECT  18.576 66.235 19.422 66.721 ;
     RECT  17.712 66.721 19.422 66.755 ;
     RECT  17.712 66.755 18.897 66.821 ;
     RECT  15.912 66.181 16.197 66.991 ;
     RECT  15.012 66.991 15.03 67.027 ;
     RECT  15.912 66.991 16.506 67.027 ;
     RECT  10.515 65.939 10.797 67.063 ;
     RECT  15.012 67.027 16.506 67.091 ;
     RECT  10.515 67.063 10.926 67.163 ;
     RECT  15.336 67.091 16.326 67.163 ;
     RECT  20.52 67.099 20.538 67.229 ;
     RECT  0.432 66.125 0.558 67.277 ;
     RECT  2.088 65.201 8.37 67.289 ;
     RECT  19.944 67.441 19.962 67.517 ;
     RECT  0.54 67.277 0.558 67.613 ;
     RECT  18.615 66.821 18.897 67.711 ;
     RECT  17.928 67.711 19.458 67.801 ;
     RECT  15.408 67.163 16.326 67.901 ;
     RECT  10.515 67.163 10.797 67.909 ;
     RECT  17.748 67.801 19.458 67.973 ;
     RECT  10.515 67.909 10.854 67.981 ;
     RECT  17.82 67.973 19.458 67.997 ;
     RECT  15.408 67.901 16.197 68.071 ;
     RECT  15.192 68.071 16.197 68.171 ;
     RECT  17.82 67.997 18.918 68.171 ;
     RECT  10.515 67.981 10.926 68.243 ;
     RECT  16.992 67.909 17.01 68.243 ;
     RECT  0.54 68.341 0.558 68.491 ;
     RECT  2.16 67.289 8.37 68.549 ;
     RECT  20.52 67.981 20.538 68.731 ;
     RECT  18.144 68.171 18.918 68.791 ;
     RECT  0.252 68.491 0.558 68.881 ;
     RECT  18.144 68.791 18.954 68.881 ;
     RECT  19.944 68.731 20.538 68.881 ;
     RECT  17.28 68.881 17.298 68.981 ;
     RECT  18.144 68.881 20.538 69.005 ;
     RECT  18.144 69.005 19.062 69.061 ;
     RECT  15.915 68.171 16.197 69.151 ;
     RECT  17.784 69.061 19.062 69.179 ;
     RECT  2.16 68.549 8.097 69.251 ;
     RECT  15.552 69.151 16.197 69.251 ;
     RECT  15.915 69.251 16.197 69.601 ;
     RECT  18.615 69.179 19.062 69.727 ;
     RECT  19.944 69.005 20.538 69.727 ;
     RECT  18.615 69.727 20.538 69.773 ;
     RECT  17.784 69.179 17.802 69.791 ;
     RECT  13.215 61.349 13.497 69.871 ;
     RECT  0.216 68.881 0.558 69.965 ;
     RECT  13.215 69.871 13.914 69.989 ;
     RECT  15.915 69.601 16.83 69.997 ;
     RECT  15.915 69.997 17.19 70.025 ;
     RECT  19.944 69.773 20.538 70.025 ;
     RECT  14.796 69.961 14.814 70.061 ;
     RECT  17.172 70.025 17.19 70.169 ;
     RECT  0.504 69.965 0.558 70.301 ;
     RECT  18.615 69.773 18.897 70.411 ;
     RECT  2.196 69.251 8.097 70.439 ;
     RECT  19.944 70.025 19.962 70.541 ;
     RECT  10.515 68.243 10.797 70.681 ;
     RECT  18 70.411 18.897 70.681 ;
     RECT  0.54 70.301 0.558 70.781 ;
     RECT  17.64 70.681 18.897 70.835 ;
     RECT  2.196 70.439 6.246 70.871 ;
     RECT  17.892 70.835 18.897 70.871 ;
     RECT  15.915 70.025 16.197 70.951 ;
     RECT  15.48 70.951 16.197 71.041 ;
     RECT  18.615 70.871 18.897 71.077 ;
     RECT  15.408 71.041 16.197 71.141 ;
     RECT  6.984 70.439 8.097 71.221 ;
     RECT  20.52 70.951 20.538 71.221 ;
     RECT  0.216 71.149 0.234 71.261 ;
     RECT  20.52 71.221 20.574 71.491 ;
     RECT  19.944 71.491 20.574 71.501 ;
     RECT  6.588 71.221 8.097 71.609 ;
     RECT  14.868 71.491 14.886 71.609 ;
     RECT  10.515 70.681 10.854 71.645 ;
     RECT  2.196 70.871 5.706 71.681 ;
     RECT  17.676 71.581 17.694 71.681 ;
     RECT  6.588 71.609 6.93 71.761 ;
     RECT  18.615 71.077 18.954 71.761 ;
     RECT  19.944 71.501 19.962 71.761 ;
     RECT  6.408 71.761 6.93 71.789 ;
     RECT  18.615 71.761 19.962 71.789 ;
     RECT  6.408 71.789 6.786 71.915 ;
     RECT  2.196 71.681 5.397 71.951 ;
     RECT  15.915 71.141 16.197 71.995 ;
     RECT  13.215 69.989 13.497 72.031 ;
     RECT  6.516 71.915 6.786 72.059 ;
     RECT  15.912 71.995 16.197 72.121 ;
     RECT  13.215 72.031 14.022 72.149 ;
     RECT  15.408 72.121 16.197 72.221 ;
     RECT  6.516 72.059 6.606 72.257 ;
     RECT  18.615 71.789 19.422 72.269 ;
     RECT  6.516 72.257 6.534 72.461 ;
     RECT  2.304 71.951 5.397 72.563 ;
     RECT  15.915 72.221 16.197 72.661 ;
     RECT  20.52 72.301 20.538 72.76 ;
     RECT  2.304 72.563 4.374 72.761 ;
     RECT  15.915 72.661 16.722 72.761 ;
     RECT  18.615 72.269 19.098 72.761 ;
     RECT  20.484 72.76 20.538 72.797 ;
     RECT  0.54 71.581 0.558 72.931 ;
     RECT  2.304 72.761 3.906 72.941 ;
     RECT  20.52 72.797 20.538 73.037 ;
     RECT  0.216 72.931 0.558 73.133 ;
     RECT  2.415 72.941 3.906 73.229 ;
     RECT  0.216 73.133 0.234 73.277 ;
     RECT  3.42 73.229 3.438 73.301 ;
     RECT  16.92 73.201 16.938 73.301 ;
     RECT  2.415 73.229 2.697 75.347 ;
     RECT  5.115 72.563 5.397 75.347 ;
     RECT  7.815 71.609 8.097 75.347 ;
     RECT  10.515 71.645 10.797 75.347 ;
     RECT  13.215 72.149 13.497 75.347 ;
     RECT  15.915 72.761 16.197 75.347 ;
     RECT  18.615 72.761 18.897 75.347 ;
     RECT  2.415 75.347 2.505 75.617 ;
     RECT  5.115 75.347 5.205 75.617 ;
     RECT  7.815 75.347 7.905 75.617 ;
     RECT  10.515 75.347 10.605 75.617 ;
     RECT  13.215 75.347 13.305 75.617 ;
     RECT  15.915 75.347 16.005 75.617 ;
     RECT  18.615 75.347 18.705 75.617 ;
    LAYER M4 ;
     RECT  0.025 52.704 0.156 52.728 ;
     RECT  0.061 54.192 0.156 54.216 ;
     RECT  0.025 57.696 0.156 57.72 ;
     RECT  0.156 4.512 0.245 73.272 ;
     RECT  0.245 4.512 0.569 73.128 ;
     RECT  0.569 4.512 2.408 72.936 ;
     RECT  2.408 2.148 2.512 75.612 ;
     RECT  2.512 2.418 2.704 75.342 ;
     RECT  2.704 71.088 2.729 72.792 ;
     RECT  2.704 4.512 2.837 57.384 ;
     RECT  2.837 4.512 3.089 55.992 ;
     RECT  3.089 23.856 3.1 55.992 ;
     RECT  3.089 4.512 3.413 22.776 ;
     RECT  3.1 41.424 3.449 55.992 ;
     RECT  3.449 48.144 3.485 55.992 ;
     RECT  2.837 57.024 3.725 57.384 ;
     RECT  2.704 58.512 3.725 70.104 ;
     RECT  3.449 41.424 3.772 47.16 ;
     RECT  3.725 57.024 3.809 70.104 ;
     RECT  3.772 41.424 3.989 43.128 ;
     RECT  2.729 71.088 3.989 72.504 ;
     RECT  3.413 5.856 4.025 22.776 ;
     RECT  3.772 44.112 4.025 47.16 ;
     RECT  3.809 58.512 4.025 70.104 ;
     RECT  3.485 53.28 4.057 55.992 ;
     RECT  3.809 57.024 4.057 57.384 ;
     RECT  3.485 48.144 4.061 52.296 ;
     RECT  4.025 6.528 4.133 22.776 ;
     RECT  4.025 47.04 4.133 47.16 ;
     RECT  3.1 23.856 4.301 40.392 ;
     RECT  3.989 41.424 4.301 42.744 ;
     RECT  4.133 10.848 4.316 22.776 ;
     RECT  4.301 23.856 4.316 42.744 ;
     RECT  4.061 50.064 4.705 52.296 ;
     RECT  4.057 53.28 4.705 57.384 ;
     RECT  3.413 4.512 5.108 4.824 ;
     RECT  4.133 6.528 5.108 9.864 ;
     RECT  4.316 10.848 5.108 42.744 ;
     RECT  4.025 44.112 5.108 45.72 ;
     RECT  4.133 47.04 5.108 47.064 ;
     RECT  4.061 48.144 5.108 49.032 ;
     RECT  4.705 50.064 5.108 57.384 ;
     RECT  4.025 58.512 5.108 60.696 ;
     RECT  4.025 61.68 5.108 62.856 ;
     RECT  4.025 63.84 5.108 70.104 ;
     RECT  3.989 71.088 5.108 72.456 ;
     RECT  5.108 2.148 5.212 75.612 ;
     RECT  5.212 2.418 5.404 75.342 ;
     RECT  5.404 18 5.465 22.824 ;
     RECT  5.404 28.8 5.465 29.592 ;
     RECT  5.404 31.152 5.565 36.12 ;
     RECT  5.465 20.352 5.603 22.824 ;
     RECT  5.404 37.632 5.603 39.768 ;
     RECT  5.404 71.088 5.609 71.448 ;
     RECT  5.404 9.312 5.645 9.864 ;
     RECT  5.404 11.232 5.681 11.256 ;
     RECT  5.404 50.736 5.681 51.672 ;
     RECT  5.603 37.872 5.717 39.768 ;
     RECT  5.404 66.048 5.717 66.6 ;
     RECT  5.404 68.496 5.753 69.288 ;
     RECT  5.404 63.84 5.789 63.864 ;
     RECT  5.681 50.88 5.891 51.672 ;
     RECT  5.404 16.032 5.897 16.872 ;
     RECT  5.404 53.04 5.987 55.272 ;
     RECT  5.404 45.456 6.035 45.72 ;
     RECT  5.897 16.32 6.185 16.872 ;
     RECT  5.465 18 6.185 18.888 ;
     RECT  5.404 24.096 6.185 26.136 ;
     RECT  5.565 31.152 6.221 35.736 ;
     RECT  5.753 68.736 6.257 69.288 ;
     RECT  6.185 18 6.293 18.84 ;
     RECT  6.221 34.944 6.437 35.736 ;
     RECT  5.404 41.424 6.469 41.928 ;
     RECT  5.404 61.68 6.545 62.04 ;
     RECT  5.404 72.432 6.545 72.456 ;
     RECT  5.609 71.424 6.617 71.448 ;
     RECT  6.469 41.424 6.689 42.792 ;
     RECT  5.987 53.856 6.689 55.272 ;
     RECT  5.891 51.648 6.761 51.672 ;
     RECT  5.404 27.264 6.829 27.624 ;
     RECT  5.465 28.8 6.829 28.824 ;
     RECT  6.221 31.152 6.829 33.624 ;
     RECT  5.404 47.04 6.829 47.064 ;
     RECT  6.829 46.848 6.973 47.064 ;
     RECT  5.404 13.824 7.009 15 ;
     RECT  5.717 37.872 7.109 39.576 ;
     RECT  5.603 21.984 7.225 22.824 ;
     RECT  6.829 30.816 7.285 33.624 ;
     RECT  7.109 5.088 7.808 5.112 ;
     RECT  6.937 6.24 7.808 6.264 ;
     RECT  5.404 8.208 7.808 8.232 ;
     RECT  5.645 9.312 7.808 9.336 ;
     RECT  7.009 13.056 7.808 15 ;
     RECT  6.185 16.368 7.808 16.872 ;
     RECT  6.293 18.192 7.808 18.84 ;
     RECT  5.603 20.352 7.808 20.376 ;
     RECT  7.225 21.984 7.808 22.92 ;
     RECT  6.185 24.096 7.808 25.464 ;
     RECT  6.829 27.264 7.808 28.824 ;
     RECT  7.285 30.72 7.808 33.624 ;
     RECT  6.437 34.944 7.808 35.496 ;
     RECT  6.793 36.576 7.808 36.6 ;
     RECT  7.109 37.632 7.808 39.576 ;
     RECT  6.689 41.424 7.808 41.928 ;
     RECT  6.035 45.552 7.808 45.72 ;
     RECT  6.973 46.752 7.808 47.064 ;
     RECT  5.404 48.144 7.808 48.168 ;
     RECT  6.865 49.44 7.808 49.464 ;
     RECT  6.689 54.624 7.808 55.272 ;
     RECT  6.545 61.68 7.808 61.704 ;
     RECT  5.717 66.576 7.808 66.6 ;
     RECT  6.257 69.264 7.808 69.288 ;
     RECT  7.261 70.704 7.808 70.728 ;
     RECT  7.808 2.148 7.912 75.612 ;
     RECT  7.912 2.418 8.104 75.342 ;
     RECT  8.104 47.04 8.129 47.064 ;
     RECT  8.104 45.696 8.453 45.72 ;
     RECT  8.104 13.056 10.508 15 ;
     RECT  8.104 16.368 10.508 16.68 ;
     RECT  8.104 18.192 10.508 18.216 ;
     RECT  8.104 20.352 10.508 20.376 ;
     RECT  8.104 21.984 10.508 22.104 ;
     RECT  8.104 24.672 10.508 25.464 ;
     RECT  8.104 31.392 10.508 32.28 ;
     RECT  8.104 35.472 10.508 35.496 ;
     RECT  8.104 37.872 10.508 37.896 ;
     RECT  8.104 39.552 10.508 39.576 ;
     RECT  8.104 61.68 10.508 61.704 ;
     RECT  10.508 2.148 10.612 75.612 ;
     RECT  10.612 2.148 10.748 75.342 ;
     RECT  10.748 1.728 10.804 75.342 ;
     RECT  10.804 1.728 10.835 1.752 ;
     RECT  10.804 37.872 10.901 37.992 ;
     RECT  10.804 26.832 11.009 26.856 ;
     RECT  10.804 31.392 11.941 32.472 ;
     RECT  10.804 13.056 12.037 15 ;
     RECT  10.804 16.368 12.037 16.68 ;
     RECT  12.013 6.672 12.044 6.696 ;
     RECT  10.804 20.448 12.044 20.472 ;
     RECT  10.804 21.984 12.044 22.104 ;
     RECT  10.804 18.192 12.049 18.216 ;
     RECT  12.037 13.056 12.085 16.68 ;
     RECT  12.049 17.904 12.085 18.216 ;
     RECT  12.044 19.728 12.085 20.616 ;
     RECT  12.085 12.528 12.124 16.68 ;
     RECT  12.044 6.672 12.131 7.656 ;
     RECT  12.044 8.736 12.131 8.76 ;
     RECT  12.044 11.232 12.131 11.256 ;
     RECT  12.085 17.904 12.131 20.616 ;
     RECT  12.044 21.696 12.131 22.104 ;
     RECT  12.049 10.224 12.133 10.248 ;
     RECT  12.124 12.528 12.169 15 ;
     RECT  12.131 17.904 12.197 18.792 ;
     RECT  10.804 35.472 12.373 35.496 ;
     RECT  10.804 39.456 12.769 39.48 ;
     RECT  10.804 24.672 12.805 25.464 ;
     RECT  12.157 26.448 12.805 26.472 ;
     RECT  11.941 31.2 12.877 32.472 ;
     RECT  12.124 16.368 12.913 16.68 ;
     RECT  12.877 30.96 13.021 32.472 ;
     RECT  12.841 5.568 13.208 5.592 ;
     RECT  12.131 6.672 13.208 6.696 ;
     RECT  12.337 9.072 13.208 9.096 ;
     RECT  12.697 10.704 13.208 10.824 ;
     RECT  12.169 13.056 13.208 15 ;
     RECT  12.913 16.368 13.208 16.872 ;
     RECT  12.197 17.904 13.208 18.216 ;
     RECT  12.131 20.448 13.208 20.472 ;
     RECT  12.131 21.984 13.208 22.104 ;
     RECT  12.805 24.672 13.208 26.904 ;
     RECT  12.985 28.176 13.208 28.2 ;
     RECT  13.021 30.96 13.208 33.336 ;
     RECT  12.373 35.184 13.208 35.496 ;
     RECT  10.901 37.968 13.208 37.992 ;
     RECT  12.769 39.264 13.208 39.48 ;
     RECT  10.804 61.68 13.208 61.704 ;
     RECT  13.208 2.148 13.312 75.612 ;
     RECT  13.312 2.418 13.504 75.342 ;
     RECT  13.504 24.528 13.529 26.904 ;
     RECT  13.504 17.904 13.601 18.216 ;
     RECT  13.504 30.96 13.637 36.6 ;
     RECT  13.529 26.736 13.673 26.904 ;
     RECT  13.504 28.08 13.673 28.2 ;
     RECT  13.637 31.392 13.673 36.6 ;
     RECT  13.504 8.4 13.715 9.096 ;
     RECT  13.504 10.56 13.753 10.728 ;
     RECT  13.504 5.568 13.763 5.88 ;
     RECT  13.504 7.296 13.763 7.32 ;
     RECT  13.715 8.4 13.763 8.424 ;
     RECT  13.504 21.552 14.177 22.104 ;
     RECT  13.529 24.528 14.717 25.464 ;
     RECT  13.673 26.832 14.717 26.904 ;
     RECT  13.504 39.456 14.821 39.48 ;
     RECT  13.673 34.512 14.825 36.6 ;
     RECT  13.763 5.568 14.861 5.592 ;
     RECT  14.821 39.456 14.861 39.576 ;
     RECT  14.825 34.896 14.897 36.6 ;
     RECT  14.897 36.576 14.933 36.6 ;
     RECT  13.673 31.392 15.26 33.336 ;
     RECT  13.601 18.192 15.289 18.216 ;
     RECT  14.717 24.672 15.289 25.464 ;
     RECT  14.717 26.832 15.289 26.856 ;
     RECT  15.26 7.104 15.301 7.128 ;
     RECT  15.26 8.16 15.301 8.184 ;
     RECT  15.289 9.36 15.301 9.384 ;
     RECT  15.289 18.192 15.301 18.84 ;
     RECT  13.504 16.368 15.361 16.872 ;
     RECT  15.301 18.048 15.361 18.84 ;
     RECT  14.177 21.984 15.596 22.104 ;
     RECT  13.504 13.056 15.637 15 ;
     RECT  15.361 16.368 15.637 18.84 ;
     RECT  15.596 21.888 15.637 22.104 ;
     RECT  13.504 20.448 15.793 20.472 ;
     RECT  15.301 6.24 15.908 7.128 ;
     RECT  15.301 8.16 15.908 9.384 ;
     RECT  13.753 10.704 15.908 10.728 ;
     RECT  15.637 13.056 15.908 18.84 ;
     RECT  15.793 20.352 15.908 20.472 ;
     RECT  15.637 21.744 15.908 22.104 ;
     RECT  15.289 24.672 15.908 26.856 ;
     RECT  13.673 28.176 15.908 28.2 ;
     RECT  15.26 30.672 15.908 33.336 ;
     RECT  14.897 34.896 15.908 35.496 ;
     RECT  13.504 37.968 15.908 37.992 ;
     RECT  14.861 39.552 15.908 39.576 ;
     RECT  15.325 51.984 15.908 52.008 ;
     RECT  13.504 61.68 15.908 61.704 ;
     RECT  15.908 2.148 16.012 75.612 ;
     RECT  16.012 2.418 16.204 75.342 ;
     RECT  16.204 9.024 16.381 10.968 ;
     RECT  16.204 21.744 16.403 23.064 ;
     RECT  16.204 27.552 16.403 28.2 ;
     RECT  16.204 33.312 16.403 35.496 ;
     RECT  16.204 6.288 16.481 7.944 ;
     RECT  16.204 13.056 16.661 20.376 ;
     RECT  16.204 25.104 16.697 26.28 ;
     RECT  16.403 27.552 16.697 27.576 ;
     RECT  16.481 6.288 16.769 6.936 ;
     RECT  16.697 25.104 16.769 25.464 ;
     RECT  16.204 30.816 16.769 32.328 ;
     RECT  16.403 34.368 16.769 35.496 ;
     RECT  16.661 14.112 16.835 20.376 ;
     RECT  16.769 34.368 16.841 34.92 ;
     RECT  16.204 5.232 16.931 5.256 ;
     RECT  16.769 6.288 16.931 6.696 ;
     RECT  16.481 7.92 16.931 7.944 ;
     RECT  16.381 9.024 16.931 9.912 ;
     RECT  16.381 10.944 16.931 10.968 ;
     RECT  16.204 12.048 16.931 12.072 ;
     RECT  16.835 18 16.931 20.376 ;
     RECT  16.403 21.984 16.931 23.064 ;
     RECT  16.769 25.104 16.957 25.224 ;
     RECT  16.769 30.816 17.057 31.512 ;
     RECT  16.835 14.112 17.129 16.68 ;
     RECT  16.204 39.552 17.129 39.576 ;
     RECT  17.233 8.592 17.597 8.616 ;
     RECT  16.931 18.144 17.597 18.216 ;
     RECT  16.204 36.96 17.809 36.984 ;
     RECT  16.841 34.368 17.845 34.392 ;
     RECT  17.845 34.368 17.953 34.968 ;
     RECT  16.204 51.888 18.061 51.912 ;
     RECT  16.931 21.984 18.469 22.2 ;
     RECT  17.449 5.376 18.608 5.4 ;
     RECT  16.931 6.672 18.608 6.696 ;
     RECT  16.661 13.056 18.608 13.08 ;
     RECT  17.129 14.112 18.608 15 ;
     RECT  17.129 16.368 18.608 16.68 ;
     RECT  17.597 18.192 18.608 18.216 ;
     RECT  16.931 19.248 18.608 19.32 ;
     RECT  16.931 20.352 18.608 20.376 ;
     RECT  18.469 21.696 18.608 22.2 ;
     RECT  16.957 25.2 18.608 25.224 ;
     RECT  17.809 26.736 18.608 26.76 ;
     RECT  17.449 30.288 18.608 30.312 ;
     RECT  17.057 31.488 18.608 31.512 ;
     RECT  17.953 34.368 18.608 35.064 ;
     RECT  17.809 36.864 18.608 36.984 ;
     RECT  18.061 51.888 18.608 51.96 ;
     RECT  18.373 56.016 18.608 56.04 ;
     RECT  16.204 61.68 18.608 61.704 ;
     RECT  18.608 2.148 18.712 75.612 ;
     RECT  18.712 2.418 18.904 75.342 ;
     RECT  18.904 5.04 19.933 5.064 ;
     RECT  18.904 7.056 19.933 7.08 ;
     RECT  18.904 8.064 19.933 8.568 ;
     RECT  18.904 9.552 19.933 9.576 ;
     RECT  18.904 10.56 19.933 11.592 ;
     RECT  18.904 12.576 19.933 12.6 ;
     RECT  18.904 13.584 19.933 14.616 ;
     RECT  18.904 15.6 19.933 16.632 ;
     RECT  18.904 17.616 19.933 19.608 ;
     RECT  18.904 20.592 19.933 20.616 ;
     RECT  18.904 21.6 19.933 23.4 ;
     RECT  18.904 24.384 19.933 24.408 ;
     RECT  18.904 25.392 19.933 25.416 ;
     RECT  18.904 27.888 19.933 27.912 ;
     RECT  18.904 28.896 19.933 30.936 ;
     RECT  18.904 31.92 19.933 32.952 ;
     RECT  18.904 33.936 19.933 33.96 ;
     RECT  18.904 35.424 19.933 35.448 ;
     RECT  18.904 37.44 19.933 37.464 ;
     RECT  18.904 40.368 19.933 40.632 ;
     RECT  18.904 42.624 19.933 42.648 ;
     RECT  18.904 45.36 19.933 46.392 ;
     RECT  18.904 50.4 19.933 53.928 ;
     RECT  18.904 55.44 19.933 57.192 ;
     RECT  18.904 58.176 19.933 61.704 ;
     RECT  18.904 62.976 19.933 67.992 ;
     RECT  18.904 68.976 19.933 69.768 ;
     RECT  18.904 70.752 19.933 70.776 ;
     RECT  18.904 72 19.933 72.264 ;
     RECT  19.933 4.512 19.969 16.632 ;
     RECT  19.933 17.616 19.969 35.976 ;
     RECT  19.933 37.2 19.969 44.376 ;
     RECT  19.933 45.36 20.113 48.648 ;
     RECT  19.933 49.632 20.113 53.928 ;
     RECT  19.933 55.152 20.473 70.776 ;
     RECT  19.933 71.76 20.473 72.264 ;
     RECT  18.904 73.248 20.473 73.272 ;
     RECT  19.969 4.512 20.509 44.376 ;
     RECT  20.113 45.36 20.509 53.928 ;
     RECT  20.473 54.912 20.509 70.776 ;
     RECT  20.473 71.76 20.509 73.272 ;
     RECT  20.509 4.512 21.42 73.272 ;
    LAYER M5 ;
     RECT  10.8 0.144 10.824 1.763 ;
     RECT  10.8 1.763 10.812 2.137 ;
     RECT  2.4 2.137 2.52 2.151 ;
     RECT  5.1 2.137 5.22 2.151 ;
     RECT  7.8 2.137 7.92 2.151 ;
     RECT  13.2 2.137 13.32 2.151 ;
     RECT  15.9 2.137 16.02 2.151 ;
     RECT  18.6 2.137 18.72 2.151 ;
     RECT  7.8 2.151 8.112 5.077 ;
     RECT  15.9 2.151 16.212 5.221 ;
     RECT  13.2 2.151 13.512 5.845 ;
     RECT  7.152 5.077 8.112 6.229 ;
     RECT  15.9 5.221 16.92 6.229 ;
     RECT  13.2 5.845 13.752 8.435 ;
     RECT  12.096 6.709 12.12 8.771 ;
     RECT  15.312 6.229 16.92 9.155 ;
     RECT  13.2 8.435 13.704 10.595 ;
     RECT  15.9 9.155 16.92 10.693 ;
     RECT  15.744 10.693 16.92 12.083 ;
     RECT  12.096 10.213 12.12 12.563 ;
     RECT  2.4 2.151 2.712 13.813 ;
     RECT  5.1 2.151 5.412 14.197 ;
     RECT  15.744 12.083 16.212 14.197 ;
     RECT  5.1 14.197 5.88 14.821 ;
     RECT  15.36 14.197 16.92 14.867 ;
     RECT  15.36 14.867 16.212 14.915 ;
     RECT  12.048 14.149 12.072 15.779 ;
     RECT  1.68 13.813 2.712 15.829 ;
     RECT  15.648 14.915 16.212 15.925 ;
     RECT  4.992 14.821 5.88 15.973 ;
     RECT  4.272 15.973 5.88 16.501 ;
     RECT  6.96 6.229 8.112 16.501 ;
     RECT  15.648 15.925 16.824 17.989 ;
     RECT  15.648 17.989 16.92 18.037 ;
     RECT  1.68 15.829 2.856 18.181 ;
     RECT  4.272 16.501 8.112 18.181 ;
     RECT  18.6 2.151 18.912 18.181 ;
     RECT  15.312 18.037 16.92 18.851 ;
     RECT  15.648 18.851 16.92 20.147 ;
     RECT  12.096 18.757 12.12 21.731 ;
     RECT  15.648 20.147 16.212 21.733 ;
     RECT  15.648 21.733 16.392 21.923 ;
     RECT  15.9 21.923 16.392 23.029 ;
     RECT  15.9 23.029 16.92 25.139 ;
     RECT  15.9 25.139 16.392 26.245 ;
     RECT  13.2 10.595 13.512 26.725 ;
     RECT  15.9 26.245 16.68 27.587 ;
     RECT  13.2 26.725 13.656 28.115 ;
     RECT  15.9 27.587 16.392 30.661 ;
     RECT  15.312 30.661 16.392 32.531 ;
     RECT  1.68 18.181 8.112 33.107 ;
     RECT  13.2 28.115 13.512 33.589 ;
     RECT  15.9 32.531 16.392 33.683 ;
     RECT  13.2 33.589 13.656 35.219 ;
     RECT  2.256 33.107 8.112 36.085 ;
     RECT  0.192 38.629 0.216 38.725 ;
     RECT  0.192 38.725 0.312 38.771 ;
     RECT  0.288 38.771 0.312 38.915 ;
     RECT  18.096 18.181 18.912 51.971 ;
     RECT  1.68 36.085 8.112 53.075 ;
     RECT  6.816 53.075 8.112 55.283 ;
     RECT  0.432 55.813 0.456 56.003 ;
     RECT  1.68 53.075 5.412 57.059 ;
     RECT  2.304 57.059 5.412 59.459 ;
     RECT  18.384 51.971 18.912 61.715 ;
     RECT  2.4 59.459 5.412 65.749 ;
     RECT  2.304 65.749 5.412 65.939 ;
     RECT  2.4 65.939 5.412 66.083 ;
     RECT  2.4 66.083 3.624 66.755 ;
     RECT  2.4 66.755 2.904 71.843 ;
     RECT  2.4 71.843 2.712 75.609 ;
     RECT  5.1 66.083 5.412 75.609 ;
     RECT  7.8 55.283 8.112 75.609 ;
     RECT  10.5 2.137 10.812 75.609 ;
     RECT  13.2 35.219 13.512 75.609 ;
     RECT  15.9 33.683 16.212 75.609 ;
     RECT  18.6 61.715 18.912 75.609 ;
     RECT  2.4 75.609 2.52 75.623 ;
     RECT  5.1 75.609 5.22 75.623 ;
     RECT  7.8 75.609 7.92 75.623 ;
     RECT  10.5 75.609 10.62 75.623 ;
     RECT  13.2 75.609 13.32 75.623 ;
     RECT  15.9 75.609 16.02 75.623 ;
     RECT  18.6 75.609 18.72 75.623 ;
  END
END hbfd_rly_136_EW_fc_f4
END LIBRARY
